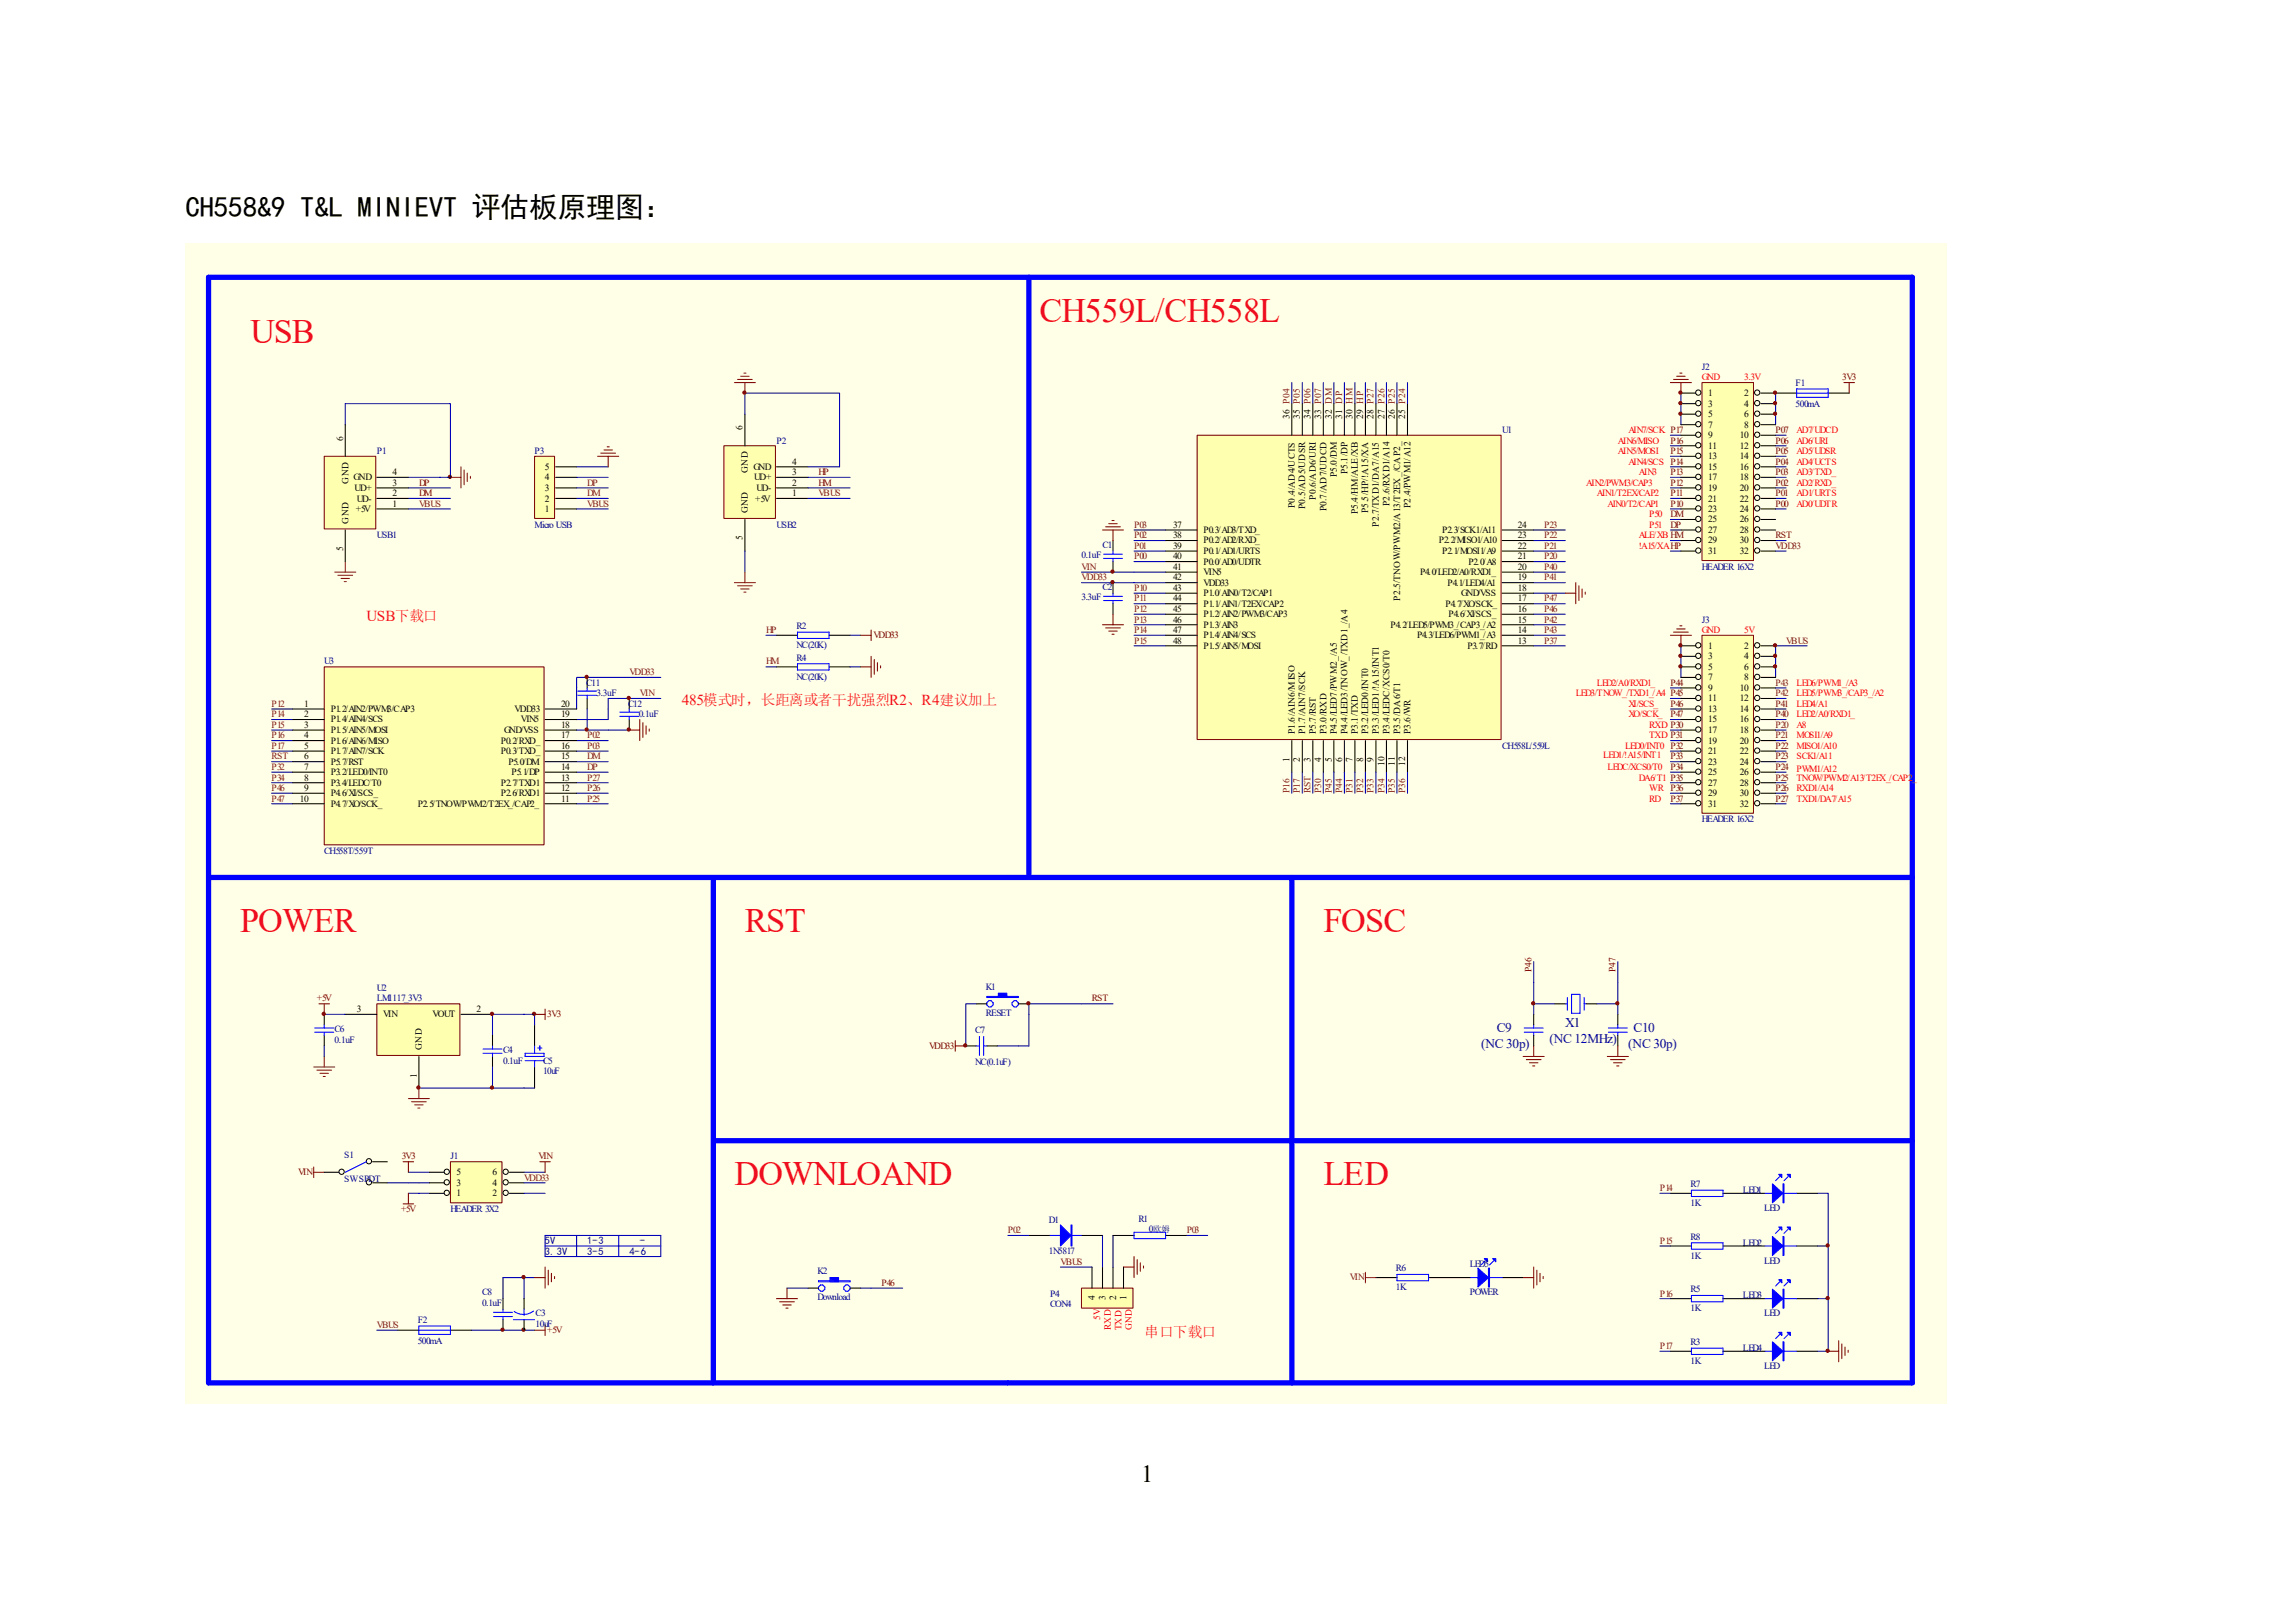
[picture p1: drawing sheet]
<svg xmlns="http://www.w3.org/2000/svg" width="297mm" height="210mm" viewBox="0 0 297 210" stroke-linecap="round" stroke-linejoin="round" font-family="sans-serif">
<defs><g id="words">
<g font-size="4.4" fill="#ee0e22">
<text x="134.5" y="41.7">CH559L/CH558L</text>
<text x="32.4" y="44.4">USB</text>
<text x="31.1" y="120.6">POWER</text>
<text x="96.4" y="120.6">RST</text>
<text x="171.3" y="120.6">FOSC</text>
<text x="95" y="153.4">DOWNLOAND</text>
<text x="171.3" y="153.4">LED</text>
</g>
<text font-size="3.7" x="24" y="28.1">CH558&amp;9 T&amp;L MINIEVT 评估板原理图：</text>
<text font-size="3.2" x="147.7" y="191.7">1</text>
<g font-size="2" fill="#ee0e22">
<text x="47.4" y="80.4">USB下载口</text>
<text x="88.2" y="91.3">485模式时，长距离或者干扰强烈R2、R4建议加上</text>
</g>
<text font-size="1.9" fill="#ee0e22" x="148.1" y="173">串口下载口</text>
<g font-size="1.7" fill="#000080">
<text x="191.7" y="135.6">(NC 30p)</text>
<text x="193.7" y="133.6">C9</text>
<text x="200.5" y="135">(NC 12MHz)</text>
<text x="202.6" y="132.9">X1</text>
<text x="210.7" y="135.6">(NC 30p)</text>
<text x="211.4" y="133.6">C10</text>
</g>
<g font-size="1.4" fill="#000080">
<text x="70.5" y="161">5V</text>
<text x="76" y="161">1-3</text>
<text x="82.8" y="161">-</text>
<text x="70.5" y="162.4">3.3V</text>
<text x="76" y="162.4">3-5</text>
<text x="81.4" y="162.4">4-6</text>
</g>
<g font-size="1.2" fill="#000080">
<text x="220.3" y="47.8">J2</text>
<text x="232.4" y="49.9">F1</text>
<text x="232.4" y="52.6">500mA</text>
<text x="48.8" y="58.8">P1</text>
<text x="69.2" y="58.8">P3</text>
<text x="100.5" y="57.4">P2</text>
<text x="194.4" y="56">U1</text>
<text x="48.8" y="69.6">USB1</text>
<text x="69.2" y="68.3">Micro USB</text>
<text x="100.5" y="68.3">USB2</text>
<text x="142.7" y="70.9">C1</text>
<text x="140" y="72.2">0.1uF</text>
<text x="140" y="77.7">3.3uF</text>
<text x="142.7" y="76.3">C2</text>
<text x="220.3" y="73.7">HEADER 16X2</text>
<text x="103.1" y="81.4">R2</text>
<text x="103.1" y="83.8">NC(20K)</text>
<text x="220.3" y="80.6">J3</text>
<text x="42" y="86">U3</text>
<text x="75.9" y="88.7">C11</text>
<text x="103.1" y="85.5">R4</text>
<text x="103.1" y="87.9">NC(20K)</text>
<text x="77.2" y="90.1">3.3uF</text>
<text x="81.3" y="91.4">C12</text>
<text x="82.7" y="92.8">0.1uF</text>
<text x="194.4" y="96.9">CH558L/559L</text>
<text x="220.3" y="106.4">HEADER 16X2</text>
<text x="42" y="110.5">CH558T/559T</text>
<text x="48.8" y="128.2">U2</text>
<text x="48.8" y="129.6">LM1117_3V3</text>
<text x="127.6" y="128.1">K1</text>
<text x="127.6" y="131.5">RESET</text>
<text x="43.3" y="133.6">C6</text>
<text x="43.3" y="134.9">0.1uF</text>
<text x="65.1" y="136.3">C4</text>
<text x="65.1" y="137.6">0.1uF</text>
<text x="70.3" y="137.6">C5</text>
<text x="126.2" y="133.7">C7</text>
<text x="126.2" y="137.8">NC(0.1uF)</text>
<text x="70.3" y="139">10uF</text>
<text x="44.5" y="149.9">S1</text>
<text x="44.5" y="152.9">SW SPDT</text>
<text x="58.3" y="150">J1</text>
<text x="218.8" y="153.6">R7</text>
<text x="225.6" y="154.4">LED1</text>
<text x="58.3" y="156.8">HEADER 3X2</text>
<text x="135.7" y="158.2">D1</text>
<text x="147.3" y="158.1">R1</text>
<text x="148.7" y="159.4">0</text>
<text x="218.8" y="160.4">R8</text>
<text x="218.8" y="156">1K</text>
<text x="225.6" y="161.2">LED2</text>
<text x="228.3" y="156.7">LED</text>
<text x="62.4" y="167.6">C8</text>
<text x="105.8" y="164.9">K2</text>
<text x="135.7" y="162.3">1N5817</text>
<text x="135.9" y="167.8">P4</text>
<text x="180.6" y="164.5">R6</text>
<text x="180.6" y="166.9">1K</text>
<text x="190.2" y="163.9">LED5</text>
<text x="190.2" y="167.6">POWER</text>
<text x="218.8" y="167.2">R5</text>
<text x="218.8" y="162.9">1K</text>
<text x="228.3" y="163.5">LED</text>
<text x="54.1" y="171.2">F2</text>
<text x="54.1" y="173.9">500mA</text>
<text x="62.4" y="169">0.1uF</text>
<text x="69.3" y="170.4">C3</text>
<text x="69.3" y="171.7">10uF</text>
<text x="105.8" y="168.3">Download</text>
<text x="135.9" y="169.1">CON4</text>
<text x="218.8" y="169.7">1K</text>
<text x="225.6" y="168">LED3</text>
<text x="228.3" y="170.4">LED</text>
<text x="218.8" y="174">R3</text>
<text x="218.8" y="176.5">1K</text>
<text x="225.6" y="174.8">LED4</text>
<text x="228.3" y="177.2">LED</text>
</g>
<g font-size="1.2" fill="#f00">
<text x="220.3" y="49.2">GND</text>
<text x="225.7" y="49.2">3.3V</text>
<text x="209.4" y="58.8">AIN5/MOSI</text>
<text x="209.4" y="57.4">AIN6/MISO</text>
<text x="210.7" y="56">AIN7/SCK P17</text>
<text x="232.5" y="58.8">AD5/UDSR</text>
<text x="232.5" y="57.4">AD6/URI</text>
<text x="232.5" y="56">AD7/UDCD</text>
<text x="205.3" y="62.8">AIN2/PWM3/CAP3</text>
<text x="206.7" y="64.2">AIN1/T2EX/CAP2</text>
<text x="208" y="65.6">AIN0/T2/CAP1</text>
<text x="210.7" y="60.1">AIN4/SCS P14</text>
<text x="212.1" y="61.5">AIN3</text>
<text x="232.5" y="65.6">AD0/UDTR</text>
<text x="232.5" y="64.2">AD1/URTS</text>
<text x="232.5" y="62.8">AD2/RXD_</text>
<text x="232.5" y="61.5">AD3/TXD_</text>
<text x="232.5" y="60.1">AD4/UCTS</text>
<text x="212.1" y="69.6">ALE/XB HM</text>
<text x="212.1" y="71">!A15/XAHP</text>
<text x="213.4" y="66.9">P50</text>
<text x="213.4" y="68.3">P51</text>
<text x="220.3" y="81.9">GND</text>
<text x="225.7" y="81.9">5V</text>
<text x="206.7" y="88.7">LED2/A0/RXD1_</text>
<text x="232.5" y="88.7">LED6/PWM1_/A3</text>
<text x="203.9" y="90.1">LED3/TNOW_/TXD1_/A4 P45</text>
<text x="210.7" y="92.8">XO/SCK_</text>
<text x="210.7" y="91.4">XI/SCS_</text>
<text x="213.4" y="94.2">RXD P30</text>
<text x="213.4" y="95.5">TXD P31</text>
<text x="232.5" y="94.2">A8</text>
<text x="232.5" y="95.5">MOSI1/A9</text>
<text x="232.5" y="92.8">LED2/A0/RXD1_</text>
<text x="232.5" y="91.4">LED4/A1</text>
<text x="232.5" y="90.1">LED5/PWM3_/CAP3_/A2</text>
<text x="207.5" y="98.1">LED1/!A15/INT1</text>
<text x="208" y="99.6">LEDC/XCS0/T0</text>
<text x="210.3" y="96.9">LED0/INT0 P32</text>
<text x="212.1" y="101">DA6/T1 P35</text>
<text x="232.5" y="96.9">MISO1/A10</text>
<text x="232.5" y="98.3">SCK1/A11</text>
<text x="232.5" y="99.9">PWM1/A12</text>
<text x="232.5" y="101">TNOW/PWM2/A13/T2EX_/CAP2_</text>
<text x="213.4" y="102.4">WR P36</text>
<text x="213.4" y="103.7">RD</text>
<text x="232.5" y="102.4">RXD1/A14</text>
<text x="232.5" y="103.7">TXD1/DA7/A15</text>
<text x="142.4" y="170.8" transform="rotate(-90 142.4 170.8)">5V</text>
<text x="143.8" y="172.1" transform="rotate(-90 143.8 172.1)">RXD</text>
<text x="145.1" y="172.1" transform="rotate(-90 145.1 172.1)">TXD</text>
<text x="146.5" y="172.1" transform="rotate(-90 146.5 172.1)">GND</text>
</g>
<g font-size="1.2">
<text x="221.1" y="51.3">1</text>
<text x="221.1" y="52.6">3</text>
<text x="221.1" y="54">5</text>
<text x="225.7" y="51.3">2</text>
<text x="225.7" y="52.6">4</text>
<text x="225.7" y="54">6</text>
<text x="44.4" y="57" transform="rotate(-90 44.4 57)">6</text>
<text x="96.1" y="55.6" transform="rotate(-90 96.1 55.6)">6</text>
<text x="166.9" y="54.3" transform="rotate(-90 166.9 54.3)">36 P04</text>
<text x="168.2" y="54.3" transform="rotate(-90 168.2 54.3)">35 P05</text>
<text x="169.6" y="54.3" transform="rotate(-90 169.6 54.3)">34 P06</text>
<text x="171" y="54.3" transform="rotate(-90 171 54.3)">33 P07</text>
<text x="172.3" y="54.3" transform="rotate(-90 172.3 54.3)">32 DM</text>
<text x="173.7" y="54.3" transform="rotate(-90 173.7 54.3)">31 DP</text>
<text x="175.1" y="54.3" transform="rotate(-90 175.1 54.3)">30 HM</text>
<text x="176.4" y="54.3" transform="rotate(-90 176.4 54.3)">29 HP</text>
<text x="177.8" y="54.3" transform="rotate(-90 177.8 54.3)">28 P27</text>
<text x="179.2" y="54.3" transform="rotate(-90 179.2 54.3)">27 P26</text>
<text x="180.5" y="54.3" transform="rotate(-90 180.5 54.3)">26 P25</text>
<text x="181.9" y="54.3" transform="rotate(-90 181.9 54.3)">25 P24</text>
<text x="221.1" y="55.3">7</text>
<text x="221.1" y="56.7">9</text>
<text x="221.1" y="58.1">11</text>
<text x="221.1" y="59.4">13</text>
<text x="225.2" y="56.7">10</text>
<text x="225.2" y="58.1">12</text>
<text x="225.2" y="59.4">14</text>
<text x="225.7" y="55.3">8</text>
<text x="45.1" y="62.6" transform="rotate(-90 45.1 62.6)">GND</text>
<text x="45.8" y="62.1">GND</text>
<text x="45.9" y="63.5">UD+</text>
<text x="46.2" y="64.9">UD-</text>
<text x="50.8" y="65.6">1</text>
<text x="50.8" y="61.5">4</text>
<text x="50.8" y="62.8">3</text>
<text x="50.8" y="64.2">2</text>
<text x="70.5" y="64.9">2</text>
<text x="70.5" y="63.5">3</text>
<text x="70.5" y="62.1">4</text>
<text x="70.5" y="60.8">5</text>
<text x="96.8" y="61.2" transform="rotate(-90 96.8 61.2)">GND</text>
<text x="97.5" y="60.8">GND</text>
<text x="97.6" y="62.1">UD+</text>
<text x="97.7" y="64.9">+5V</text>
<text x="97.9" y="63.5">UD-</text>
<text x="102.5" y="64.2">1</text>
<text x="102.5" y="60.1">4</text>
<text x="102.5" y="61.5">3</text>
<text x="102.5" y="62.8">2</text>
<text x="167.6" y="65.7" transform="rotate(-90 167.6 65.7)">P0.4/AD4/UCTS</text>
<text x="168.9" y="65.9" transform="rotate(-90 168.9 65.9)">P0.5/AD5/UDSR</text>
<text x="170.3" y="64.6" transform="rotate(-90 170.3 64.6)">P0.6/AD6/URI</text>
<text x="173" y="61.8" transform="rotate(-90 173 61.8)">P5.0/DM</text>
<text x="174.4" y="61.3" transform="rotate(-90 174.4 61.3)">P5.1/DP</text>
<text x="179.8" y="65.4" transform="rotate(-90 179.8 65.4)">P2.6/RXD1/A14</text>
<text x="182.5" y="65.7" transform="rotate(-90 182.5 65.7)">P2.4/PWM1/A12</text>
<text x="221.1" y="60.8">15</text>
<text x="221.1" y="62.1">17</text>
<text x="221.1" y="63.5">19</text>
<text x="221.1" y="64.9">21</text>
<text x="225.2" y="60.8">16</text>
<text x="225.2" y="62.1">18</text>
<text x="225.2" y="63.5">20</text>
<text x="225.2" y="64.9">22</text>
<text x="44.4" y="71.3" transform="rotate(-90 44.4 71.3)">5</text>
<text x="45.1" y="67.8" transform="rotate(-90 45.1 67.8)">GND</text>
<text x="46.1" y="66.3">+5V</text>
<text x="70.5" y="66.3">1</text>
<text x="96.1" y="69.9" transform="rotate(-90 96.1 69.9)">5</text>
<text x="96.8" y="66.4" transform="rotate(-90 96.8 66.4)">GND</text>
<text x="151.8" y="68.3">37</text>
<text x="151.8" y="69.6">38</text>
<text x="151.8" y="71">39</text>
<text x="155.7" y="69">P0.3/AD3/TXD_</text>
<text x="155.7" y="70.3">P0.2/AD2/RXD_</text>
<text x="155.7" y="71.7">P0.1/AD1/URTS</text>
<text x="171.7" y="66.1" transform="rotate(-90 171.7 66.1)">P0.7/AD7/UDCD</text>
<text x="175.7" y="66.5" transform="rotate(-90 175.7 66.5)">P5.4/HM/ALE/XB</text>
<text x="177.1" y="66.4" transform="rotate(-90 177.1 66.4)">P5.5/HP/!A15/XA</text>
<text x="178.4" y="68.2" transform="rotate(-90 178.4 68.2)">P2.7/TXD1/DA7/A15</text>
<text x="186.2" y="70.3">P2.2/MISO1/A10</text>
<text x="186.7" y="71.7">P2.1/MOSI1/A9</text>
<text x="186.7" y="69">P2.3/SCK1/A11</text>
<text x="196.4" y="71">22</text>
<text x="196.4" y="69.6">23</text>
<text x="196.4" y="68.3">24</text>
<text x="221.1" y="66.3">23</text>
<text x="221.1" y="67.6">25</text>
<text x="221.1" y="69">27</text>
<text x="221.1" y="70.3">29</text>
<text x="221.1" y="71.7">31</text>
<text x="225.2" y="66.3">24</text>
<text x="225.2" y="67.6">26</text>
<text x="225.2" y="69">28</text>
<text x="225.2" y="70.3">30</text>
<text x="225.2" y="71.7">32</text>
<text x="151.8" y="72.4">40</text>
<text x="151.8" y="73.7">41</text>
<text x="151.8" y="75.1">42</text>
<text x="151.8" y="76.5">43</text>
<text x="151.8" y="77.8">44</text>
<text x="155.7" y="73.1">P0.0/AD0/UDTR</text>
<text x="155.7" y="74.4">VIN5</text>
<text x="155.7" y="75.8">VDD33</text>
<text x="155.7" y="77.1">P1.0/AIN0/T2/CAP1</text>
<text x="181.2" y="77.7" transform="rotate(-90 181.2 77.7)">P2.5/TNOW/PWM2/A13/T2EX_/CAP2_</text>
<text x="183.8" y="74.4">P4.0/LED2/A0/RXD1_</text>
<text x="187.3" y="75.8">P4.1/LED4/A1</text>
<text x="189.1" y="77.1">GND/VSS</text>
<text x="190" y="73.1">P2.0/A8</text>
<text x="196.4" y="77.8">17</text>
<text x="196.4" y="76.5">18</text>
<text x="196.4" y="73.7">20</text>
<text x="196.4" y="72.4">21</text>
<text x="196.4" y="75.1">19</text>
<text x="151.8" y="83.3">48</text>
<text x="151.8" y="79.2">45</text>
<text x="151.8" y="80.6">46</text>
<text x="151.8" y="81.9">47</text>
<text x="155.7" y="83.9">P1.5/AIN5/MOSI</text>
<text x="155.7" y="78.5">P1.1/AIN1/T2EX/CAP2</text>
<text x="155.7" y="79.9">P1.2/AIN2/PWM3/CAP3</text>
<text x="155.7" y="81.2">P1.3/AIN3</text>
<text x="155.7" y="82.6">P1.4/AIN4/SCS</text>
<text x="180" y="81.2">P4.2/LED5/PWM3_/CAP3_/A2</text>
<text x="183.4" y="82.6">P4.3/LED6/PWM1_/A3</text>
<text x="187.1" y="78.5">P4.7/XO/SCK_</text>
<text x="187.5" y="79.9">P4.6/XI/SCS_</text>
<text x="189.9" y="83.9">P3.7/RD</text>
<text x="196.4" y="83.3">13</text>
<text x="196.4" y="79.2">16</text>
<text x="196.4" y="81.9">14</text>
<text x="196.4" y="80.6">15</text>
<text x="221.1" y="83.9">1</text>
<text x="225.7" y="83.9">2</text>
<text x="221.1" y="85.3">3</text>
<text x="221.1" y="86.7">5</text>
<text x="221.1" y="88.1">7</text>
<text x="221.1" y="89.4">9</text>
<text x="225.2" y="89.4">10</text>
<text x="225.7" y="85.3">4</text>
<text x="225.7" y="86.7">6</text>
<text x="225.7" y="88.1">8</text>
<text x="39.4" y="94.2">3</text>
<text x="39.4" y="95.5">4</text>
<text x="39.4" y="91.4">1</text>
<text x="39.4" y="92.8">2</text>
<text x="42.8" y="94.9">P1.5/AIN5/MOSI</text>
<text x="42.8" y="92.1">P1.2/AIN2/PWM3/CAP3</text>
<text x="42.8" y="93.5">P1.4/AIN4/SCS</text>
<text x="65.2" y="94.9">GND/VSS</text>
<text x="66.6" y="92.1">VDD33</text>
<text x="67.4" y="93.5">VIN5</text>
<text x="72.6" y="94.2">18</text>
<text x="72.6" y="95.5">17</text>
<text x="72.6" y="92.8">19</text>
<text x="72.6" y="91.4">20</text>
<text x="167.6" y="95" transform="rotate(-90 167.6 95)">P1.6/AIN6/MISO</text>
<text x="168.9" y="95" transform="rotate(-90 168.9 95)">P1.7/AIN7/SCK</text>
<text x="170.3" y="95" transform="rotate(-90 170.3 95)">P5.7/RST</text>
<text x="171.7" y="95" transform="rotate(-90 171.7 95)">P3.0/RXD</text>
<text x="173" y="95" transform="rotate(-90 173 95)">P4.5/LED7/PWM2_/A5</text>
<text x="174.4" y="95" transform="rotate(-90 174.4 95)">P4.4/LED3/TNOW_/TXD1_/A4</text>
<text x="175.7" y="95" transform="rotate(-90 175.7 95)">P3.1/TXD</text>
<text x="177.1" y="95" transform="rotate(-90 177.1 95)">P3.2/LED0/INT0</text>
<text x="178.4" y="95" transform="rotate(-90 178.4 95)">P3.3/LED1/!A15/INT1</text>
<text x="179.8" y="95" transform="rotate(-90 179.8 95)">P3.4/LEDC/XCS0/T0</text>
<text x="181.2" y="95" transform="rotate(-90 181.2 95)">P3.5/DA6/T1</text>
<text x="182.5" y="95" transform="rotate(-90 182.5 95)">P3.6/WR</text>
<text x="221.1" y="90.8">11</text>
<text x="221.1" y="92.1">13</text>
<text x="221.1" y="93.5">15</text>
<text x="221.1" y="94.9">17</text>
<text x="225.2" y="90.8">12</text>
<text x="225.2" y="92.1">14</text>
<text x="225.2" y="93.5">16</text>
<text x="225.2" y="94.9">18</text>
<text x="39.4" y="96.9">5</text>
<text x="39.4" y="98.3">6</text>
<text x="39.4" y="99.6">7</text>
<text x="39.4" y="101">8</text>
<text x="42.8" y="96.2">P1.6/AIN6/MISO</text>
<text x="42.8" y="97.6">P1.7/AIN7/SCK</text>
<text x="42.8" y="98.9">P5.7/RST</text>
<text x="42.8" y="100.3">P3.2/LED0/INT0</text>
<text x="42.8" y="101.7">P3.4/LEDC/T0</text>
<text x="64.8" y="101.7">P2.7/TXD1</text>
<text x="64.8" y="97.6">P0.3/TXD_</text>
<text x="64.8" y="96.2">P0.2/RXD_</text>
<text x="65.8" y="98.9">P5.0/DM</text>
<text x="66.2" y="100.3">P5.1/DP</text>
<text x="72.6" y="101">13</text>
<text x="72.6" y="99.6">14</text>
<text x="72.6" y="98.3">15</text>
<text x="72.6" y="96.9">16</text>
<text x="166.9" y="98.6" transform="rotate(-90 166.9 98.6)">1</text>
<text x="168.2" y="98.6" transform="rotate(-90 168.2 98.6)">2</text>
<text x="169.6" y="98.6" transform="rotate(-90 169.6 98.6)">3</text>
<text x="171" y="98.6" transform="rotate(-90 171 98.6)">4</text>
<text x="172.3" y="98.6" transform="rotate(-90 172.3 98.6)">5</text>
<text x="173.7" y="98.6" transform="rotate(-90 173.7 98.6)">6</text>
<text x="175.1" y="98.6" transform="rotate(-90 175.1 98.6)">7</text>
<text x="176.4" y="98.6" transform="rotate(-90 176.4 98.6)">8</text>
<text x="177.8" y="98.6" transform="rotate(-90 177.8 98.6)">9</text>
<text x="179.2" y="99.1" transform="rotate(-90 179.2 99.1)">10</text>
<text x="180.5" y="99.1" transform="rotate(-90 180.5 99.1)">11</text>
<text x="181.9" y="99.1" transform="rotate(-90 181.9 99.1)">12</text>
<text x="221.1" y="96.2">19</text>
<text x="221.1" y="97.6">21</text>
<text x="221.1" y="98.9">23</text>
<text x="221.1" y="100.3">25</text>
<text x="221.1" y="101.7">27</text>
<text x="225.2" y="96.2">20</text>
<text x="225.2" y="97.6">22</text>
<text x="225.2" y="98.9">24</text>
<text x="225.2" y="100.3">26</text>
<text x="225.2" y="101.7">28</text>
<text x="38.8" y="103.7">10</text>
<text x="39.4" y="102.4">9</text>
<text x="42.8" y="103">P4.6/XI/SCS_</text>
<text x="42.8" y="104.4">P4.7/XO/SCK_</text>
<text x="54.1" y="104.4">P2.5/TNOW/PWM2/T2EX_/CAP2_</text>
<text x="64.8" y="103">P2.6/RXD1</text>
<text x="72.6" y="103.7">11</text>
<text x="72.6" y="102.4">12</text>
<text x="221.1" y="103">29</text>
<text x="221.1" y="104.4">31</text>
<text x="225.2" y="103">30</text>
<text x="225.2" y="104.4">32</text>
<text x="46.2" y="131">3</text>
<text x="49.6" y="131.7">VIN</text>
<text x="56" y="131.7">VOUT</text>
<text x="61.7" y="131">2</text>
<text x="54.6" y="135.9" transform="rotate(-90 54.6 135.9)">GND</text>
<text x="53.9" y="139.4" transform="rotate(-90 53.9 139.4)">1</text>
<text x="59.1" y="154.8">1</text>
<text x="59.1" y="153.5">3</text>
<text x="59.1" y="152.1">5</text>
<text x="63.8" y="154.8">2</text>
<text x="63.8" y="153.5">4</text>
<text x="63.8" y="152.1">6</text>
<text x="141.7" y="168.2" transform="rotate(-90 141.7 168.2)">4</text>
<text x="143.1" y="168.2" transform="rotate(-90 143.1 168.2)">3</text>
<text x="144.4" y="168.2" transform="rotate(-90 144.4 168.2)">2</text>
<text x="145.8" y="168.2" transform="rotate(-90 145.8 168.2)">1</text>
</g>
<g font-size="1.2" fill="#800000">
<text x="238.4" y="49.2">3V3</text>
<text x="216.2" y="58.8">P15</text>
<text x="216.2" y="57.4">P16</text>
<text x="229.8" y="58.8">P05</text>
<text x="229.8" y="57.4">P06</text>
<text x="229.8" y="56">P07</text>
<text x="54.2" y="62.8">DP</text>
<text x="54.2" y="64.2">DM</text>
<text x="105.9" y="61.5">HP</text>
<text x="105.9" y="62.8">HM</text>
<text x="216.2" y="65.6">P10</text>
<text x="216.2" y="64.2">P11</text>
<text x="216.2" y="62.8">P12</text>
<text x="216.2" y="61.5">P13</text>
<text x="229.8" y="65.6">P00</text>
<text x="229.8" y="64.2">P01</text>
<text x="229.8" y="62.8">P02</text>
<text x="229.8" y="61.5">P03</text>
<text x="229.8" y="60.1">P04</text>
<text x="216.2" y="66.9">DM</text>
<text x="216.2" y="68.3">DP</text>
<text x="229.8" y="69.6">RST</text>
<text x="113" y="82.6">VDD33</text>
<text x="216.2" y="88.7">P44</text>
<text x="216.2" y="91.4">P46</text>
<text x="216.2" y="92.8">P47</text>
<text x="229.8" y="92.8">P40</text>
<text x="229.8" y="91.4">P41</text>
<text x="216.2" y="98.3">P33</text>
<text x="216.2" y="99.6">P34</text>
<text x="229.8" y="96.9">P22</text>
<text x="229.8" y="98.3">P23</text>
<text x="229.8" y="99.6">P24</text>
<text x="229.8" y="101">P25</text>
<text x="216.2" y="103.7">P37</text>
<text x="229.8" y="102.4">P26</text>
<text x="229.8" y="103.7">P27</text>
<text x="198.2" y="125.8" transform="rotate(-90 198.2 125.8)">P46</text>
<text x="209.1" y="125.8" transform="rotate(-90 209.1 125.8)">P47</text>
<text x="41" y="129.6">+5V</text>
<text x="70.8" y="131.7">3V3</text>
<text x="141.3" y="129.6">RST</text>
<text x="120.2" y="135.7">VDD33</text>
<text x="38.6" y="152.1">VIN</text>
<text x="52" y="150">3V3</text>
<text x="69.7" y="150">VIN</text>
<text x="51.9" y="156.8">+5V</text>
<text x="114.1" y="166.4">P46</text>
<text x="70.8" y="172.5">+5V</text>
</g>
<g font-size="1.2" fill="#781915">
<text x="54.2" y="65.6">VBUS</text>
<text x="76" y="65.6">VBUS</text>
<text x="76" y="64.2">DM</text>
<text x="76" y="62.8">DP</text>
<text x="105.9" y="64.2">VBUS</text>
<text x="146.8" y="68.3">P03</text>
<text x="146.8" y="69.6">P02</text>
<text x="146.8" y="71">P01</text>
<text x="199.9" y="71">P21</text>
<text x="199.9" y="69.6">P22</text>
<text x="199.9" y="68.3">P23</text>
<text x="229.8" y="71">VDD33</text>
<text x="140" y="75.1">VDD33</text>
<text x="140" y="73.7">VIN</text>
<text x="146.8" y="72.4">P00</text>
<text x="146.8" y="76.5">P10</text>
<text x="146.8" y="77.8">P11</text>
<text x="199.9" y="72.4">P20</text>
<text x="199.9" y="73.7">P40</text>
<text x="199.9" y="75.1">P41</text>
<text x="199.9" y="77.8">P47</text>
<text x="99.1" y="81.9">HP</text>
<text x="146.8" y="79.2">P12</text>
<text x="146.8" y="80.6">P13</text>
<text x="146.8" y="81.9">P14</text>
<text x="146.8" y="83.3">P15</text>
<text x="199.9" y="79.2">P46</text>
<text x="199.9" y="83.3">P37</text>
<text x="199.9" y="80.6">P42</text>
<text x="199.9" y="81.9">P43</text>
<text x="231.1" y="83.3">VBUS</text>
<text x="81.5" y="87.4">VDD33</text>
<text x="99.1" y="86">HM</text>
<text x="229.8" y="88.7">P43</text>
<text x="35.1" y="91.4">P12</text>
<text x="35.1" y="92.8">P14</text>
<text x="35.1" y="94.2">P15</text>
<text x="35.1" y="95.5">P16</text>
<text x="76" y="95.5">P02</text>
<text x="82.8" y="90.1">VIN</text>
<text x="229.8" y="94.2">P20</text>
<text x="229.8" y="95.5">P21</text>
<text x="229.8" y="90.1">P42</text>
<text x="35.1" y="96.9">P17</text>
<text x="35.1" y="98.3">RST</text>
<text x="35.1" y="99.6">P32</text>
<text x="35.1" y="101">P34</text>
<text x="76" y="96.9">P03</text>
<text x="76" y="98.3">DM</text>
<text x="76" y="99.6">DP</text>
<text x="76" y="101">P27</text>
<text x="35.1" y="102.4">P46</text>
<text x="35.1" y="103.7">P47</text>
<text x="76" y="102.4">P26</text>
<text x="76" y="103.7">P25</text>
<text x="166.9" y="102.7" transform="rotate(-90 166.9 102.7)">P16</text>
<text x="168.2" y="102.7" transform="rotate(-90 168.2 102.7)">P17</text>
<text x="169.6" y="102.7" transform="rotate(-90 169.6 102.7)">RST</text>
<text x="171" y="102.7" transform="rotate(-90 171 102.7)">P30</text>
<text x="172.3" y="102.7" transform="rotate(-90 172.3 102.7)">P45</text>
<text x="173.7" y="102.7" transform="rotate(-90 173.7 102.7)">P44</text>
<text x="175.1" y="102.7" transform="rotate(-90 175.1 102.7)">P31</text>
<text x="176.4" y="102.7" transform="rotate(-90 176.4 102.7)">P32</text>
<text x="177.8" y="102.7" transform="rotate(-90 177.8 102.7)">P33</text>
<text x="179.2" y="102.7" transform="rotate(-90 179.2 102.7)">P34</text>
<text x="180.5" y="102.7" transform="rotate(-90 180.5 102.7)">P35</text>
<text x="181.9" y="102.7" transform="rotate(-90 181.9 102.7)">P36</text>
<text x="67.8" y="152.8">VDD33</text>
<text x="214.8" y="154.1">P14</text>
<text x="130.4" y="159.6">P02</text>
<text x="153.6" y="159.6">P03</text>
<text x="214.8" y="161">P15</text>
<text x="137.2" y="163.7">VBUS</text>
<text x="174.7" y="165.7">VIN</text>
<text x="214.8" y="167.8">P16</text>
<text x="48.8" y="171.8">VBUS</text>
<text x="214.8" y="174.5">P17</text>
</g>
<text font-size="1.1" fill="#000080" x="149.2" y="159.4">欧姆</text>
</g></defs>
<path d="M24 31.5h228v150.1h-228z" fill-rule="evenodd" fill="#ffffe8"/>
<g fill="none" stroke="#00f" stroke-width=".14">
<path d="M197.3 133.6h2.4M197.3 133h2.4M198.5 132.6v.4M198.5 133.6v.4M202.6 129.9h.2M202.8 129.1v1.6M203.4 128.7h1.1v2.4h-1.1zM205 129.1v1.6M205 129.9h.3M208.1 133.6h2.5M208.1 133h2.5M209.4 132.6v.4"/>
<path d="M209.4 133.6v.4"/>
</g>
<path d="M198.5 131.3v1.3M198.5 134v1.3M201.2 129.9h1.4M205.3 129.9h1.4M209.4 131.3v1.3M209.4 134v1.3" fill="none" stroke="#000" stroke-width=".14"/>
<path d="M197.1 136.7h2.7M197.5 137.1h1.9M197.9 137.5h1.1M198.3 137.9h.3M198.5 135.3v1.4M208 136.7h2.7M208.4 137.1h1.9M208.8 137.5h1.1M209.2 137.9h.3M209.4 135.3v1.4" fill="none" stroke="#800000" stroke-width=".14"/>
<path d="M42 59h6.6v9.4h-6.6z" fill-rule="evenodd" fill="#ffffb0" stroke="#800000" stroke-width=".13"/>
<path d="M44.7 55v4M44.7 68.6v4.1M48.8 65.9h4.1M48.8 61.8h4.1M48.8 63.1h4.1M48.8 64.5h4.1M51.5 172.1h2.7M58.3 172.1h2.7M65.1 168v1.4M65.1 170.8v1.3" fill="none" stroke="#000" stroke-width=".14"/>
<path d="M44.7 52.2v2.8M52.9 61.8h4M52.9 63.1h5.4M52.9 64.5h5.4" fill="none" stroke="#000080" stroke-width=".14"/>
<path d="M43.3 74h2.7M43.7 74.4h1.9M44.1 74.9h1.1M44.5 75.3h.3M44.7 72.7v1.3M58.3 61.8h1.4M59.7 60.4v2.7M60.1 60.8v1.9M60.5 61.2v1.1M60.9 61.6v.3" fill="none" stroke="#781915" stroke-width=".14"/>
<path d="M54.2 171.6h4.1v1.1h-4.1zM54.2 172.1h4.1M63.9 169.8h2.4M63.9 170.4h2.4M65.1 169.4v.4M65.1 170.4v.4" fill="none" stroke="#00f" stroke-width=".14"/>
<path d="M93.7 57.7h6.7v9.4h-6.7z" fill-rule="evenodd" fill="#ffffb0" stroke="#800000" stroke-width=".13"/>
<path d="M96.4 53.6v4.1M96.4 67.2v4.1M100.5 64.5h4.1M100.5 60.4h4.1M100.5 61.8h4.1M100.5 63.1h4.1M69.2 132.6v2.7M69.2 138.1v2.7" fill="none" stroke="#000" stroke-width=".14"/>
<path d="M96.4 50.9v2.7M96.4 71.3v2.7M104.6 60.4h4.1M104.6 61.8h5.4M104.6 63.1h5.4" fill="none" stroke="#000080" stroke-width=".14"/>
<path d="M95 75.4h2.8M95.5 75.8h1.9M95.9 76.2h1M96.3 76.6h.2M96.4 74v1.4" fill="none" stroke="#781915" stroke-width=".14"/>
<circle cx="58.2" cy="61.7" r=".21" fill="#800000" stroke="#800000" stroke-width=".13"/>
<path d="M68 136.3h2.4v.4h-2.4zM68 137.3h2.4M69.2 135.3v1M69.2 137.3v.8M69.6 135.6h.5M69.9 135.3v.6" fill="none" stroke="#00f" stroke-width=".14"/>
<path d="M41.3 129.9h1.3M42 129.9v1.4" fill="none" stroke="#800000" stroke-width=".14"/>
<path d="M48.8 129.9h10.7v6.7h-10.7z" fill-rule="evenodd" fill="#ffffb0" stroke="#800000" stroke-width=".13"/>
<g fill="none" stroke="#000" stroke-width=".14">
<path d="M42 131.3v1.3M42 134v1.3M44.7 131.3h4.1M54.2 136.7v4.1M59.7 131.3h4M63.7 134v1.3M63.7 136.7v1.4M125 135.3h1.3M126.3 129.9h1.4M127.7 135.3h1.4M131.8 129.9h1.4M216.2 154.4h2.7"/>
<path d="M223 154.4h5.4M232.5 154.4h2.7M178.1 165.3h2.7M184.9 165.3h5.4M194.4 165.3h2.7M216.2 174.9h2.7M216.2 168h2.7M216.2 161.2h2.7M223 174.9h5.4M223 168h5.4M223 161.2h5.4M232.5 174.9h2.7"/>
<path d="M232.5 168h2.7M232.5 161.2h2.7"/>
</g>
<g fill="none" stroke="#000080" stroke-width=".14">
<path d="M44.7 52.2h13.6v9.6M42 131.3h2.7M42 135.3v1.4M63.7 138.1v2.7M69.2 132.6v-1.3h-5.5v2.7M126.3 129.9h-1.3v5.4M144 129.9h-10.8v5.4h-4.1M198.5 127.2v2.7M201.2 129.9h-2.7v1.4M206.7 129.9h2.7v1.4M209.4 127.2v2.7M52.9 154.4h2.7"/>
<path d="M52.9 153.1h2.7M52.9 151.7h2.7M54.2 140.8h15M235.2 154.4h1.4M235.2 161.2h1.4M235.2 168h1.4M235.2 174.9h1.4"/>
</g>
<g fill="none" stroke="#00f" stroke-width=".14">
<path d="M40.7 133.6h2.5M40.7 133h2.5M42 132.6v.4M42 133.6v.4M62.5 136.3h2.5M62.5 135.8h2.5M63.7 135.3v.5M63.7 136.3v.4M126.3 135.3h.5M126.8 134.1v2.5M127.3 135.3h.4M127.3 134.1v2.5"/>
<path d="M127.7 128.9h4.1v.2h-4.1zM128 129.5h.3l.2 .3v.2l-.2 .3h-.3l-.3-.3v-.2zM129.2 129.1v-.6h1.1v.6M129.2 128.8h1.1M129.2 128.7h1.1M129.3 128.5v.6M129.5 128.5v.6M129.6 128.5v.6M129.8 128.5v.6M129.9 128.5v.6M130 128.5v.6M130.2 128.5v.6"/>
<path d="M131 129.8l.2-.3h.3l.3 .3v.2l-.3 .3h-.3l-.2-.3zM218.9 154h4.1v.8h-4.1zM228.4 154.4h4.1M230.3 159.1l-.5 .5M230.3 152.2l-.5 .6M231.4 159.1l-.5 .5M231.4 152.2l-.5 .6M180.8 164.9h4.1v.8h-4.1zM190.3 165.3h4.1M192.2 163.1l-.5 .6M193.3 163.1l-.5 .6M218.9 160.8h4.1v.8h-4.1z"/>
<path d="M218.9 167.6h4.1v.9h-4.1zM218.9 174.4h4.1v.9h-4.1zM228.4 174.9h4.1M228.4 168h4.1M228.4 161.2h4.1M230.3 172.7l-.5 .5M230.3 165.9l-.5 .5M231.4 172.7l-.5 .5M231.4 165.9l-.5 .5"/>
</g>
<path d="M40.6 138.1h2.7M41 138.5h1.9M41.4 138.9h1.1M41.8 139.3h.3M42 136.7v1.4M52.9 142.2h2.7M53.3 142.6h1.9M53.7 143h1.1M54.1 143.4h.2M54.2 140.8v1.4M176.7 164.6v1.4M176.7 165.3h1.4" fill="none" stroke="#781915" stroke-width=".14"/>
<circle cx="69.1" cy="131.2" r=".21" fill="#800000" stroke="#800000" stroke-width=".13"/>
<g fill="none" stroke="#800000" stroke-width=".14">
<path d="M69.2 131.3h1.3M70.5 130.6v1.3M123.6 134.7v1.3M123.6 135.3h1.4M52.2 150.3h1.3M52.2 155.8h1.3M52.9 150.3v1.4M52.9 154.4v1.4M197.1 165.3h1.4M198.5 164v2.7M198.9 164.4v1.9M199.3 164.8v1.1"/>
<path d="M199.7 165.2v.3"/>
</g>
<g fill="#00f" stroke="#00f" stroke-width=".14">
<path d="M229.4 173.6l1.3 1.3-1.3 1.2z"/>
<path d="M231.3 172.4h.4v.4z"/>
<path d="M230.2 172.4h.4v.4z"/>
<path d="M229.4 166.8l1.3 1.2-1.3 1.3z"/>
<path d="M231.3 165.6h.4v.4z"/>
<path d="M230.2 165.6h.4v.4z"/>
<path d="M229.4 160l1.3 1.2-1.3 1.3z"/>
<path d="M231.3 158.8h.4v.4z"/>
<path d="M230.2 158.8h.4v.4z"/>
<path d="M229.4 153.2l1.3 1.2-1.3 1.2z"/>
<path d="M231.3 152h.4v.4z"/>
<path d="M230.2 152h.4v.4z"/>
<path d="M191.3 164.1l1.3 1.2-1.3 1.2z"/>
<path d="M193.2 162.9h.4v.4z"/>
<path d="M192.1 162.9h.4v.4z"/>
<path d="M230.7 173.6h.2v2.5h-.2z" fill-rule="evenodd"/>
<path d="M230.7 166.8h.2v2.5h-.2z" fill-rule="evenodd"/>
<path d="M230.7 160h.2v2.5h-.2z" fill-rule="evenodd"/>
<path d="M230.7 153.2h.2v2.4h-.2z" fill-rule="evenodd"/>
<path d="M192.6 164.1h.2v2.4h-.2z" fill-rule="evenodd"/>
</g>
<path d="M133.2 35.9v77.6M247.5 35.9v77.6h-220.5" fill="none" stroke="#00f" stroke-width=".68"/>
<path d="M58.3 150.3h6.7v5.3h-6.7z" fill-rule="evenodd" fill="#ffffb0" stroke="#800000" stroke-width=".13"/>
<g fill="none" stroke="#000" stroke-width=".13">
<circle cx="44.2" cy="151.6" r=".34"/>
<circle cx="47.7" cy="150.3" r=".34"/>
<circle cx="47.7" cy="153" r=".34"/>
<circle cx="57.8" cy="154.4" r=".34"/>
<circle cx="57.8" cy="153" r=".34"/>
<circle cx="57.8" cy="151.6" r=".34"/>
<circle cx="65.4" cy="154.4" r=".34"/>
<circle cx="65.4" cy="153" r=".34"/>
<circle cx="65.4" cy="151.6" r=".34"/>
</g>
<g fill="none" stroke="#000" stroke-width=".14">
<path d="M100.5 82.2h2.7M100.5 86.3h2.7M107.3 82.2h2.7M107.3 86.3h2.7M42 151.7h1.9M48.2 153.1h1.9M48.2 150.3h1.9M55.6 154.4h1.9M55.6 153.1h1.9M55.6 151.7h1.9M65.9 154.4h1.9M65.9 153.1h1.9"/>
<path d="M65.9 151.7h1.9M104.6 166.7h1.3M110 166.7h1.4"/>
</g>
<g fill="none" stroke="#000080" stroke-width=".14">
<path d="M217.5 50.9v4.1M229.8 50.9v4.1M99.1 82.2h1.4M99.1 86.3h1.4M110 82.2h1.4M110 86.3h1.4M217.5 83.6v4.1M229.8 83.6h4.1M198.5 124.4v2.8M209.4 124.4v2.8M67.8 153.1h2.7M67.8 154.4h2.7"/>
<path d="M67.8 151.7h2.7M101.8 166.7h2.8M111.4 166.7h5.4"/>
</g>
<path d="M70.5 159.9h15v2.7h-15zM74.6 159.9v2.7M80.1 159.9v2.7M70.5 161.2h15" fill="none" stroke="#0000b4" stroke-width=".14"/>
<g fill="none" stroke="#800000" stroke-width=".14">
<path d="M216.2 49.5h2.7M216.6 49.1h1.9M217 48.7h1.1M217.4 48.3h.3M217.5 49.5v1.4M238.6 49.5h1.4M239.3 49.5v1.4M111.4 82.2h1.3M111.4 86.3h1.3M112.7 81.5v1.4M112.7 84.9v2.8M113.1 85.3v1.9"/>
<path d="M113.6 85.7v1.1M114 86.2v.2M216.2 82.2h2.7M216.6 81.8h1.9M217 81.4h1.1M217.4 81h.3M217.5 82.2v1.4M40.6 151v1.4M40.6 151.7h1.4M69.9 150.3h1.3M70.5 150.3v1.4M100.5 168h2.7"/>
<path d="M100.9 168.5h1.9M101.3 168.9h1.1M101.7 169.3h.3M101.8 166.7v1.3"/>
</g>
<g fill="none" stroke="#00f" stroke-width=".14">
<path d="M103.2 81.8h4.1v.8h-4.1zM103.2 85.9h4.1v.8h-4.1zM47.4 150.3l-2.7 1.4M105.9 165.7h4.1v.2h-4.1zM106.2 166.3h.3l.2 .2v.3l-.2 .3h-.3l-.3-.3v-.3zM107.4 165.9v-.6h1.1v.6M107.4 165.6h1.1M107.4 165.5h1.1M107.6 165.3v.6M107.7 165.3v.6M107.8 165.3v.6M108 165.3v.6"/>
<path d="M108.1 165.3v.6M108.2 165.3v.6M108.4 165.3v.6M109.5 166.3h.2l.3 .2v.3l-.3 .3h-.2l-.3-.3v-.3z"/>
</g>
<path d="M247.5 35.9h-220.5v143h220.5v-65.4M92.3 113.5v65.4M92.3 147.6h155.2" fill="none" stroke="#00f" stroke-width=".68"/>
<path d="M69.2 59h2.6v8.1h-2.6z" fill-rule="evenodd" fill="#ffffb0" stroke="#800000" stroke-width=".13"/>
<path d="M71.9 65.9h2.7M71.9 64.5h2.7M71.9 63.1h2.7M71.9 61.8h2.7M71.9 60.4h2.7" fill="none" stroke="#000" stroke-width=".14"/>
<path d="M52.9 65.9h5.4M56.9 61.8h1.4M74.6 65.9h4.1M74.6 64.5h4.1M74.6 63.1h4.1M74.6 61.8h4.1M74.6 60.4h4.1M48.8 172.1h2.7M61 172.1h8.2M69.2 165.3h-4.1v2.7" fill="none" stroke="#000080" stroke-width=".14"/>
<path d="M77.3 59h2.8M77.8 58.6h1.9M78.2 58.2h1.1M78.6 57.8h.2M78.7 59v1.4M69.2 165.3h1.3M69.2 172.1h1.3M70.5 164v2.7M70.5 171.4v1.4M71 164.4v1.9M71.4 164.8v1.1M71.8 165.2v.3" fill="none" stroke="#800000" stroke-width=".14"/>
<path d="M167.2 113.5v65.4" fill="none" stroke="#00f" stroke-width=".68"/>
<path d="M140 166.7h6.6v2.6h-6.6z" fill-rule="evenodd" fill="#ffffb0" stroke="#800000" stroke-width=".13"/>
<path d="M229.8 50.9h2.7M236.6 50.9h2.7M133.2 159.9h2.7M140 159.9h2.7M144 159.9h2.8M150.8 159.9h2.8M141.3 164v2.7M142.7 164v2.7M144 164v2.7M145.4 164v2.7" fill="none" stroke="#000" stroke-width=".14"/>
<path d="M232.5 50.3h4.1v1.1h-4.1zM232.5 50.9h4.1M135.9 159.9h4.1M146.8 159.5h4v.8h-4z" fill="none" stroke="#00f" stroke-width=".14"/>
<g fill="#00f" stroke="#00f" stroke-width=".14">
<path d="M137.2 158.5l1.4 1.4-1.4 1.3z"/>
<path d="M138.6 158.5h.1v2.7h-.1z" fill-rule="evenodd"/>
</g>
<path d="M145.4 164h1.4M146.8 162.6v2.7M147.2 163v1.9M147.6 163.4v1.1M148 163.8v.3M236.6 174.9h1.4M238 173.5v2.7M238.4 173.9v1.9M238.8 174.3v1.1M239.2 174.7v.3" fill="none" stroke="#800000" stroke-width=".14"/>
<path d="M229.8 83.6v4.1M130.4 159.9h2.8M142.7 159.9v4.1M144 159.9v4.1M153.6 159.9h2.7M214.8 154.4h1.4M236.6 154.4v20.5M137.2 164h4.1M214.8 161.2h1.4M214.8 168h1.4M214.8 174.9h1.4" fill="none" stroke="#000080" stroke-width=".14"/>
<g fill="#800000" stroke="#800000" stroke-width=".13">
<circle cx="41.9" cy="131.2" r=".21"/>
<circle cx="54.1" cy="140.7" r=".21"/>
<circle cx="63.7" cy="131.2" r=".21"/>
<circle cx="63.7" cy="140.7" r=".21"/>
<circle cx="124.9" cy="135.3" r=".21"/>
<circle cx="133.1" cy="129.8" r=".21"/>
<circle cx="209.3" cy="129.8" r=".21"/>
<circle cx="198.4" cy="129.8" r=".21"/>
<circle cx="236.5" cy="168" r=".21"/>
<circle cx="236.5" cy="161.2" r=".21"/>
<circle cx="236.5" cy="174.8" r=".21"/>
</g>
<path d="M154.9 56.3h39.4v39.4h-39.4z" fill-rule="evenodd" fill="#ffffb0" stroke="#800000" stroke-width=".14"/>
<g fill="none" stroke="#000" stroke-width=".14">
<path d="M167.2 52.2v4.1M168.5 52.2v4.1M169.9 52.2v4.1M171.3 52.2v4.1M172.6 52.2v4.1M174 52.2v4.1M175.3 52.2v4.1M176.7 52.2v4.1M178.1 52.2v4.1M179.4 52.2v4.1M180.8 52.2v4.1M182.2 52.2v4.1"/>
<path d="M144 69.9v1.4M144 72.7v1.3M144 75.4v1.4M144 78.1v1.4M150.8 79.5h4.1M150.8 78.1h4.1M150.8 76.8h4.1M150.8 74h4.1M150.8 72.7h4.1M150.8 71.3h4.1M150.8 69.9h4.1M150.8 68.6h4.1"/>
<path d="M150.8 75.4h4.1M194.4 79.5h4.1M194.4 78.1h4.1M194.4 76.8h4.1M194.4 74h4.1M194.4 72.7h4.1M194.4 71.3h4.1M194.4 69.9h4.1M194.4 68.6h4.1M194.4 75.4h4.1M150.8 83.6h4.1M150.8 80.8h4.1"/>
<path d="M150.8 82.2h4.1M167.2 95.8v4.1M168.5 95.8v4.1M169.9 95.8v4.1M171.3 95.8v4.1M172.6 95.8v4.1M174 95.8v4.1M175.3 95.8v4.1M176.7 95.8v4.1M178.1 95.8v4.1M179.4 95.8v4.1M180.8 95.8v4.1"/>
<path d="M182.2 95.8v4.1M194.4 83.6h4.1M194.4 80.8h4.1M194.4 82.2h4.1"/>
</g>
<g fill="none" stroke="#000080" stroke-width=".14">
<path d="M167.2 49.5v2.7M168.5 49.5v2.7M169.9 49.5v2.7M171.3 49.5v2.7M172.6 49.5v2.7M174 49.5v2.7M175.3 49.5v2.7M176.7 49.5v2.7M178.1 49.5v2.7M179.4 49.5v2.7M180.8 49.5v2.7M182.2 49.5v2.7"/>
<path d="M216.2 56.3h1.3M216.2 57.7h1.3M216.2 59h1.3M229.8 56.3h1.4M229.8 57.7h1.4M229.8 59h1.4M140 75.4h10.8M140 74h10.8M146.8 68.6h4M146.8 69.9h4M146.8 79.5h4M146.8 76.8h4"/>
<path d="M146.8 71.3h4M146.8 72.7h4M146.8 78.1h4M198.5 68.6h4.1M198.5 69.9h4.1M198.5 79.5h4.1M198.5 76.8h4.1M198.5 75.4h4.1M198.5 71.3h4.1M198.5 72.7h4.1M198.5 78.1h4.1M198.5 74h4.1"/>
<path d="M216.2 68.6h1.3M216.2 69.9h1.3M216.2 71.3h1.3M216.2 67.2h1.3M216.2 60.4h1.3M216.2 61.8h1.3M216.2 63.1h1.3M216.2 64.5h1.3M216.2 65.9h1.3M229.8 69.9h1.4M229.8 60.4h1.4M229.8 61.8h1.4"/>
<path d="M229.8 63.1h1.4M229.8 64.5h1.4M229.8 65.9h1.4M146.8 80.8h4M146.8 82.2h4M146.8 83.6h4M167.2 99.9v2.7M168.5 99.9v2.7M169.9 99.9v2.7M171.3 99.9v2.7M172.6 99.9v2.7M174 99.9v2.7"/>
<path d="M175.3 99.9v2.7M176.7 99.9v2.7M178.1 99.9v2.7M179.4 99.9v2.7M180.8 99.9v2.7M182.2 99.9v2.7M198.5 80.8h4.1M198.5 82.2h4.1M198.5 83.6h4.1M216.2 89h1.3M216.2 90.4h1.3M216.2 91.7h1.3"/>
<path d="M216.2 93.1h1.3M216.2 99.9h1.3M216.2 98.6h1.3M216.2 97.2h1.3M216.2 95.8h1.3M216.2 94.5h1.3M229.8 89h1.4M229.8 90.4h1.4M229.8 91.7h1.4M229.8 93.1h1.4M229.8 99.9h1.4M229.8 98.6h1.4"/>
<path d="M229.8 97.2h1.4M229.8 95.8h1.4M229.8 94.5h1.4M216.2 104h1.3M216.2 102.6h1.3M216.2 101.3h1.3M229.8 104h1.4M229.8 102.6h1.4M229.8 101.3h1.4"/>
</g>
<path d="M142.8 72.3h2.5M142.8 71.7h2.5M142.8 77.7h2.5M142.8 77.2h2.5M144 71.3v.4M144 72.3v.4M144 76.8v.4M144 77.7v.4" fill="none" stroke="#00f" stroke-width=".14"/>
<g fill="none" stroke="#800000" stroke-width=".14">
<path d="M142.7 68.6h2.7M143.1 68.2h1.9M143.5 67.8h1.1M143.9 67.4h.3M144 68.6v1.3M144 79.5v1.3M202.6 76.8h1.3M203.9 75.4v2.7M204.3 75.8v1.9M204.7 76.2v1.1M205.2 76.6v.3M142.7 80.8h2.7"/>
<path d="M143.1 81.3h1.9M143.5 81.7h1.1M143.9 82.1h.3"/>
</g>
<path d="M220.3 49.5h6.6v23h-6.6z" fill-rule="evenodd" fill="#ffffb0" stroke="#800000" stroke-width=".13"/>
<g fill="none" stroke="#000" stroke-width=".13">
<circle cx="219.8" cy="54.9" r=".34"/>
<circle cx="219.8" cy="59" r=".34"/>
<circle cx="219.8" cy="50.8" r=".34"/>
<circle cx="219.8" cy="53.5" r=".34"/>
<circle cx="219.8" cy="56.3" r=".34"/>
<circle cx="219.8" cy="57.6" r=".34"/>
<circle cx="219.8" cy="52.2" r=".34"/>
<circle cx="227.4" cy="59" r=".34"/>
<circle cx="227.4" cy="54.9" r=".34"/>
<circle cx="227.4" cy="56.3" r=".34"/>
<circle cx="227.4" cy="53.5" r=".34"/>
<circle cx="227.4" cy="57.6" r=".34"/>
<circle cx="227.4" cy="50.8" r=".34"/>
<circle cx="227.4" cy="52.2" r=".34"/>
<circle cx="219.8" cy="65.8" r=".34"/>
<circle cx="219.8" cy="71.2" r=".34"/>
<circle cx="219.8" cy="68.5" r=".34"/>
<circle cx="219.8" cy="64.4" r=".34"/>
<circle cx="219.8" cy="67.1" r=".34"/>
<circle cx="219.8" cy="61.7" r=".34"/>
<circle cx="219.8" cy="69.9" r=".34"/>
<circle cx="219.8" cy="60.3" r=".34"/>
<circle cx="219.8" cy="63.1" r=".34"/>
<circle cx="227.4" cy="65.8" r=".34"/>
<circle cx="227.4" cy="67.1" r=".34"/>
<circle cx="227.4" cy="69.9" r=".34"/>
<circle cx="227.4" cy="60.3" r=".34"/>
<circle cx="227.4" cy="61.7" r=".34"/>
<circle cx="227.4" cy="64.4" r=".34"/>
<circle cx="227.4" cy="68.5" r=".34"/>
<circle cx="227.4" cy="71.2" r=".34"/>
<circle cx="227.4" cy="63.1" r=".34"/>
</g>
<g fill="none" stroke="#000" stroke-width=".14">
<path d="M217.5 50.9h1.9M217.5 52.2h1.9M217.5 53.6h1.9M217.5 55h1.9M217.5 56.3h1.9M217.5 57.7h1.9M217.5 59h1.9M227.9 50.9h1.9M227.9 52.2h1.9M227.9 53.6h1.9M227.9 55h1.9M227.9 56.3h1.9"/>
<path d="M227.9 57.7h1.9M227.9 59h1.9M217.5 60.4h1.9M217.5 61.8h1.9M217.5 63.1h1.9M217.5 64.5h1.9M217.5 65.9h1.9M217.5 67.2h1.9M217.5 68.6h1.9M217.5 69.9h1.9M217.5 71.3h1.9M227.9 60.4h1.9"/>
<path d="M227.9 61.8h1.9M227.9 63.1h1.9M227.9 64.5h1.9M227.9 65.9h1.9M227.9 67.2h1.9M227.9 68.6h1.9M227.9 69.9h1.9M227.9 71.3h1.9"/>
</g>
<path d="M220.3 82.2h6.6v23h-6.6z" fill-rule="evenodd" fill="#ffffb0" stroke="#800000" stroke-width=".13"/>
<g fill="none" stroke="#000" stroke-width=".13">
<circle cx="219.8" cy="91.7" r=".34"/>
<circle cx="219.8" cy="93" r=".34"/>
<circle cx="219.8" cy="95.8" r=".34"/>
<circle cx="219.8" cy="84.9" r=".34"/>
<circle cx="219.8" cy="90.3" r=".34"/>
<circle cx="219.8" cy="97.1" r=".34"/>
<circle cx="219.8" cy="99.8" r=".34"/>
<circle cx="219.8" cy="87.6" r=".34"/>
<circle cx="219.8" cy="98.5" r=".34"/>
<circle cx="219.8" cy="83.5" r=".34"/>
<circle cx="219.8" cy="86.2" r=".34"/>
<circle cx="219.8" cy="89" r=".34"/>
<circle cx="219.8" cy="94.4" r=".34"/>
<circle cx="227.4" cy="87.6" r=".34"/>
<circle cx="227.4" cy="90.3" r=".34"/>
<circle cx="227.4" cy="91.7" r=".34"/>
<circle cx="227.4" cy="98.5" r=".34"/>
<circle cx="227.4" cy="89" r=".34"/>
<circle cx="227.4" cy="86.2" r=".34"/>
<circle cx="227.4" cy="94.4" r=".34"/>
<circle cx="227.4" cy="97.1" r=".34"/>
<circle cx="227.4" cy="83.5" r=".34"/>
<circle cx="227.4" cy="84.9" r=".34"/>
<circle cx="227.4" cy="93" r=".34"/>
<circle cx="227.4" cy="95.8" r=".34"/>
<circle cx="227.4" cy="99.8" r=".34"/>
<circle cx="219.8" cy="102.6" r=".34"/>
<circle cx="219.8" cy="101.2" r=".34"/>
<circle cx="219.8" cy="103.9" r=".34"/>
<circle cx="227.4" cy="102.6" r=".34"/>
<circle cx="227.4" cy="103.9" r=".34"/>
<circle cx="227.4" cy="101.2" r=".34"/>
</g>
<g fill="none" stroke="#000" stroke-width=".14">
<path d="M81.4 90.4v1.3M81.4 93.1v1.4M217.5 83.6h1.9M217.5 84.9h1.9M217.5 86.3h1.9M217.5 87.7h1.9M217.5 89h1.9M217.5 90.4h1.9M217.5 91.7h1.9M217.5 93.1h1.9M217.5 94.5h1.9M217.5 95.8h1.9"/>
<path d="M217.5 97.2h1.9M217.5 98.6h1.9M217.5 99.9h1.9M227.9 83.6h1.9M227.9 84.9h1.9M227.9 86.3h1.9M227.9 87.7h1.9M227.9 89h1.9M227.9 90.4h1.9M227.9 91.7h1.9M227.9 93.1h1.9M227.9 94.5h1.9"/>
<path d="M227.9 95.8h1.9M227.9 97.2h1.9M227.9 98.6h1.9M227.9 99.9h1.9M217.5 101.3h1.9M217.5 102.6h1.9M217.5 104h1.9M227.9 101.3h1.9M227.9 102.6h1.9M227.9 104h1.9M67.8 168v1.4M67.8 170.8v1.3"/>
</g>
<g fill="#800000" stroke="#800000" stroke-width=".13">
<circle cx="217.5" cy="50.8" r=".21"/>
<circle cx="229.7" cy="50.8" r=".21"/>
<circle cx="217.5" cy="52.2" r=".21"/>
<circle cx="229.7" cy="52.2" r=".21"/>
<circle cx="217.5" cy="53.5" r=".21"/>
<circle cx="229.7" cy="53.5" r=".21"/>
<circle cx="217.5" cy="83.5" r=".21"/>
<circle cx="229.7" cy="83.5" r=".21"/>
<circle cx="217.5" cy="84.9" r=".21"/>
<circle cx="217.5" cy="86.2" r=".21"/>
<circle cx="229.7" cy="86.2" r=".21"/>
<circle cx="229.7" cy="84.9" r=".21"/>
<circle cx="144" cy="74" r=".21"/>
<circle cx="144" cy="75.3" r=".21"/>
<circle cx="65" cy="172.1" r=".21"/>
<circle cx="67.8" cy="172.1" r=".21"/>
<circle cx="67.8" cy="165.2" r=".21"/>
<circle cx="96.3" cy="50.8" r=".21"/>
</g>
<g fill="none" stroke="#000080" stroke-width=".14">
<path d="M96.4 50.9h12.3v9.5M104.6 64.5h5.4M229.8 71.3h1.4M35.2 94.5h2.7M35.2 93.1h2.7M35.2 95.8h2.7M35.2 97.2h2.7M35.2 98.6h2.7M35.2 99.9h2.7M35.2 91.7h2.7M74.6 94.5h6.8M74.6 93.1h4.1"/>
<path d="M74.6 89v2.7M74.6 95.8h4.1M74.6 97.2h4.1M74.6 98.6h4.1M74.6 99.9h4.1M82.8 90.4h-4.1v1.3M35.2 102.6h2.7M35.2 101.3h2.7M35.2 104h2.7M74.6 102.6h4.1M74.6 101.3h4.1M74.6 104h4.1"/>
<path d="M50.1 153.1h2.8M67.8 165.3v2.7"/>
</g>
<path d="M80.2 92.7h2.5M80.2 92.2h2.5M81.4 91.7v.5M81.4 92.7v.4M66.5 170.8h2.7M67.8 169.4v.8M69.1 169.6a2.11 2.11 0 0 1-2.6 .1" fill="none" stroke="#00f" stroke-width=".14"/>
<path d="M95 49.5h2.8M95.5 49.1h1.9M95.9 48.7h1M96.3 48.3h.2M96.4 49.5v1.4" fill="none" stroke="#781915" stroke-width=".14"/>
<path d="M42 86.3h28.4v23h-28.4z" fill-rule="evenodd" fill="#ffffb0" stroke="#800000" stroke-width=".14"/>
<g fill="none" stroke="#000" stroke-width=".14">
<path d="M37.9 94.5h4.1M37.9 95.8h4.1M37.9 97.2h4.1M37.9 98.6h4.1M37.9 99.9h4.1M37.9 93.1h4.1M37.9 91.7h4.1M70.5 94.5h4.1M70.5 95.8h4.1M70.5 97.2h4.1M70.5 98.6h4.1M70.5 99.9h4.1"/>
<path d="M70.5 93.1h4.1M70.5 91.7h4.1M76 87.7v1.3M76 90.4v1.3M37.9 101.3h4.1M37.9 102.6h4.1M37.9 104h4.1M70.5 101.3h4.1M70.5 102.6h4.1M70.5 104h4.1"/>
</g>
<path d="M76 91.7v2.8M78.7 91.7v1.4M82.8 90.4h2.7M85.5 87.7h-10.9v1.3" fill="none" stroke="#000080" stroke-width=".14"/>
<path d="M81.4 94.5h1.4M82.8 93.1v2.7M83.2 93.5v1.9M83.6 93.9v1.1M84 94.3v.3" fill="none" stroke="#800000" stroke-width=".14"/>
<path d="M74.8 90h2.4M74.8 89.4h2.4M76 89v.4M76 90v.4" fill="none" stroke="#00f" stroke-width=".14"/>
<g fill="#800000" stroke="#800000" stroke-width=".13">
<circle cx="81.4" cy="90.3" r=".21"/>
<circle cx="81.4" cy="94.4" r=".21"/>
<circle cx="75.9" cy="87.6" r=".21"/>
<circle cx="75.9" cy="94.4" r=".21"/>
</g>
<use href="#words"/>
</svg>
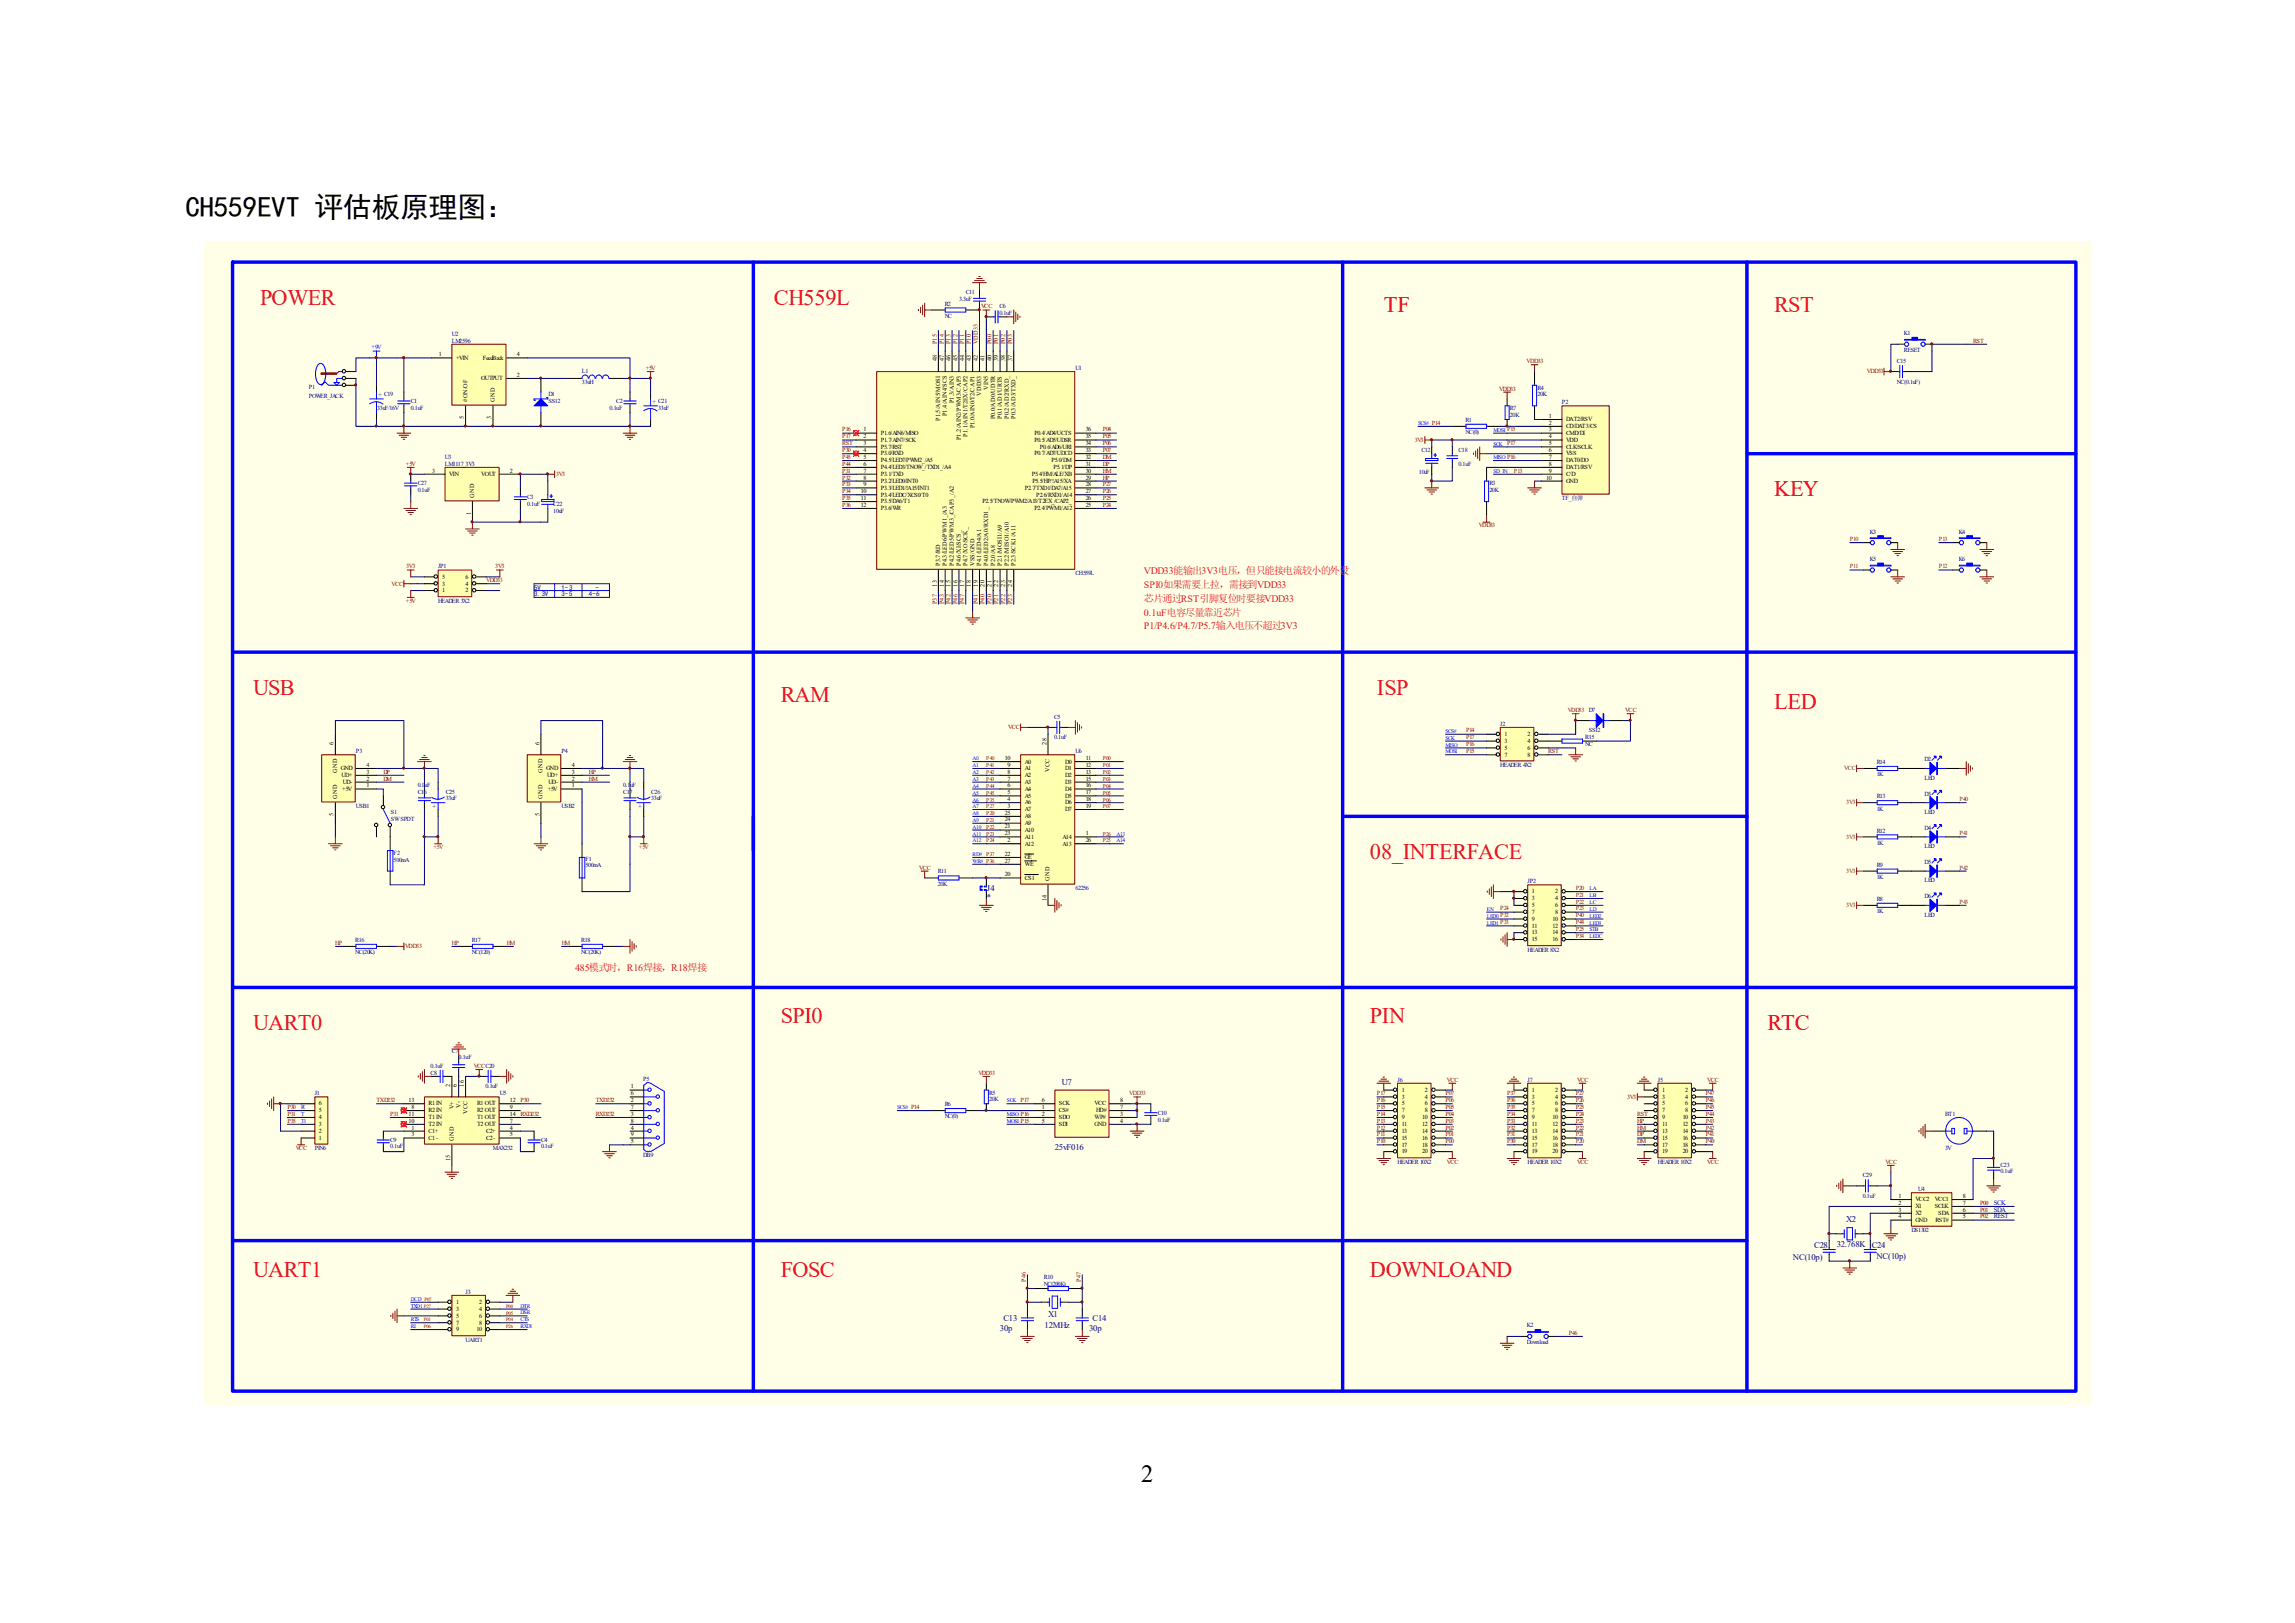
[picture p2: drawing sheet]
<svg xmlns="http://www.w3.org/2000/svg" width="297mm" height="210mm" viewBox="0 0 297 210" stroke-linecap="round" stroke-linejoin="round" font-family="sans-serif">
<defs><g id="words">
<text font-size="3.7" x="24" y="28.1">CH559EVT 评估板原理图：</text>
<text font-size="3.2" x="147.7" y="191.7">2</text>
<g font-size="2.9" fill="#ee0e22">
<text x="33.7" y="39.5">POWER</text>
<text x="100.2" y="39.5">CH559L</text>
<text x="229.6" y="40.3">RST</text>
<text x="32.8" y="89.9">USB</text>
<text x="178.2" y="89.9">ISP</text>
<text x="101.1" y="90.8">RAM</text>
<text x="229.6" y="91.7">LED</text>
<text x="177.3" y="111.2">08_INTERFACE</text>
<text x="32.8" y="133.3">UART0</text>
<text x="101.1" y="132.4">SPI0</text>
<text x="177.3" y="132.4">PIN</text>
<text x="32.8" y="165.2">UART1</text>
<text x="101.1" y="165.2">FOSC</text>
<text x="177.3" y="165.2">DOWNLOAND</text>
</g>
<g font-size="2.9" fill="#f00">
<text x="179.1" y="40.3">TF</text>
<text x="229.6" y="64.2">KEY</text>
<text x="228.7" y="133.3">RTC</text>
</g>
<g font-size="1.3" fill="#ee0e22">
<text x="148" y="74.3">VDD33能输出3V3电压，但只能接电流较小的外设</text>
<text x="148" y="76.1">SPI0如果需要上拉，需接到VDD33</text>
<text x="148" y="77.9">芯片通过RST引脚复位时要接VDD33</text>
<text x="148" y="81.5">P1/P4.6/P4.7/P5.7输入电压不超过3V3</text>
<text x="148" y="79.7">0.1uF电容尽量靠近芯片</text>
<text x="74.4" y="125.7">485模式时，R16焊接，R18焊接</text>
</g>
<g font-size="1.1" fill="#000080">
<text x="127.7" y="115.3">J4</text>
<text x="127.7" y="116.5">*</text>
<text x="137.4" y="140.4">U7</text>
<text x="136.5" y="148.8">25vF016</text>
<text x="234.8" y="161.5">C28</text>
<text x="237.7" y="161.3">32.768K</text>
<text x="238.9" y="158.1">X2</text>
<text x="242.2" y="161.5">C24</text>
<text x="232" y="163.1">NC(10p)</text>
<text x="242.9" y="162.9">NC(10p)</text>
<text x="129.4" y="172.3">30p</text>
<text x="129.9" y="170.9">C13</text>
<text x="135.2" y="171.8">12MHz</text>
<text x="135.6" y="170.5">X1</text>
<text x="141" y="172.3">30p</text>
<text x="141.4" y="170.9">C14</text>
</g>
<g font-size=".9" fill="#000080">
<text x="69.1" y="76.3">5V</text>
<text x="69.1" y="77.2">3.3V</text>
<text x="72.7" y="76.3">1-3</text>
<text x="72.7" y="77.2">3-5</text>
<text x="76.2" y="77.2">4-6</text>
<text x="77.1" y="76.3">-</text>
</g>
<g font-size=".9" fill="#0000bf">
<text x="258" y="155.9">SCK</text>
<text x="258" y="156.8">SDA</text>
<text x="258" y="157.7">REST</text>
</g>
<g font-size=".8" fill="#000080">
<text x="122.3" y="39.5">R2</text>
<text x="122.3" y="41.1">NC</text>
<text x="124.1" y="38.9">3.3uF</text>
<text x="125" y="38.1">C11</text>
<text x="129.3" y="39.9">C6</text>
<text x="129.3" y="40.8">0.1uF</text>
<text x="58.5" y="43.4">U2</text>
<text x="58.5" y="44.3">LM2596</text>
<text x="139.2" y="47.9">U1</text>
<text x="245.5" y="47">C15</text>
<text x="246.4" y="43.3">K1</text>
<text x="246.4" y="45.5">RESET</text>
<text x="40" y="50.3">P1</text>
<text x="40" y="51.5">POWER_JACK</text>
<text x="48.8" y="53.1">33uF/16V</text>
<text x="49" y="51.4">+ C19</text>
<text x="53.2" y="52.2">C1</text>
<text x="53.2" y="53.1">0.1uF</text>
<text x="71" y="51.3">D1</text>
<text x="71" y="52.2">SS12</text>
<text x="75.3" y="48.3">L1</text>
<text x="75.3" y="49.7">33uH</text>
<text x="78.9" y="53.1">0.1uF</text>
<text x="79.8" y="52.2">C2</text>
<text x="84.5" y="52.3">+ C21</text>
<text x="85.2" y="53.1">33uF</text>
<text x="195.4" y="53.1">R7</text>
<text x="195.4" y="54">20K</text>
<text x="199" y="50.5">R4</text>
<text x="199" y="51.3">20K</text>
<text x="202.1" y="52.3">P2</text>
<text x="245.5" y="49.7">NC(0.1uF)</text>
<text x="57.6" y="59.4">U3</text>
<text x="184" y="58.5">C12</text>
<text x="188.8" y="58.5">C18</text>
<text x="189.7" y="54.6">R1</text>
<text x="189.7" y="56.2">NC(0)</text>
<text x="54.1" y="62.8">C27</text>
<text x="54.1" y="63.7">0.1uF</text>
<text x="57.6" y="60.3">LM1117_3V3</text>
<text x="68.2" y="64.6">C3</text>
<text x="68.2" y="65.5">0.1uF</text>
<text x="71.6" y="65.5">C22</text>
<text x="183.6" y="61.3">10uF</text>
<text x="188.8" y="60.3">0.1uF</text>
<text x="192.7" y="62.8">R3</text>
<text x="192.7" y="63.7">20K</text>
<text x="202.1" y="64.7">TF_自弹</text>
<text x="71.6" y="66.4">10uF</text>
<text x="242" y="69">K3</text>
<text x="253.5" y="69">K4</text>
<text x="56.7" y="73.5">JP1</text>
<text x="56.7" y="78">HEADER 3X2</text>
<text x="139.2" y="74.4">CH559L</text>
<text x="242" y="72.6">K5</text>
<text x="253.5" y="72.6">K6</text>
<text x="136.4" y="93">C5</text>
<text x="136.4" y="95.7">0.1uF</text>
<text x="194.1" y="93.9">J2</text>
<text x="205.2" y="95.6">R15</text>
<text x="205.6" y="94.8">SS12</text>
<text x="46.1" y="97.4">P3</text>
<text x="54.1" y="101.8">0.1uF</text>
<text x="72.7" y="97.4">P4</text>
<text x="80.6" y="101.8">0.1uF</text>
<text x="139.2" y="97.4">U6</text>
<text x="194.1" y="99.2">HEADER 4X2</text>
<text x="205.2" y="96.5">NC</text>
<text x="242.9" y="98.9">R14</text>
<text x="242.9" y="100.5">1K</text>
<text x="249.1" y="98.5">D2</text>
<text x="249.1" y="100.9">LED</text>
<text x="46.1" y="104.5">USB1</text>
<text x="50.6" y="105.3">S1</text>
<text x="50.6" y="106.2">SW SPDT</text>
<text x="54.1" y="102.7">C16</text>
<text x="56.4" y="104.1" transform="rotate(-180 56.4 104.1)">+</text>
<text x="57.7" y="102.7">C25</text>
<text x="57.7" y="103.5">33uF</text>
<text x="72.7" y="104.5">USB2</text>
<text x="80.6" y="102.7">C17</text>
<text x="83.1" y="104.1" transform="rotate(-180 83.1 104.1)">+</text>
<text x="84.3" y="102.7">C26</text>
<text x="84.3" y="103.5">33uF</text>
<text x="242.9" y="107.7">R12</text>
<text x="242.9" y="103.3">R13</text>
<text x="242.9" y="104.9">1K</text>
<text x="249.1" y="107.4">D4</text>
<text x="249.1" y="103">D3</text>
<text x="249.1" y="105.3">LED</text>
<text x="50.9" y="110.7">F2</text>
<text x="50.9" y="111.5">500mA</text>
<text x="75.8" y="111.5">F1</text>
<text x="75.8" y="112.2">500mA</text>
<text x="121.4" y="113">R11</text>
<text x="242.9" y="112.1">R9</text>
<text x="242.9" y="113.7">1K</text>
<text x="242.9" y="109.3">1K</text>
<text x="249.1" y="111.8">D5</text>
<text x="249.1" y="109.8">LED</text>
<text x="121.4" y="114.6">20K</text>
<text x="139.2" y="115.1">62256</text>
<text x="197.7" y="114.3">JP2</text>
<text x="242.9" y="116.6">R8</text>
<text x="242.9" y="118.2">1K</text>
<text x="249.1" y="116.2">D6</text>
<text x="249.1" y="118.6">LED</text>
<text x="249.1" y="114.2">LED</text>
<text x="46" y="121.9">R16</text>
<text x="46" y="123.5">NC(20K)</text>
<text x="61" y="121.9">R17</text>
<text x="61" y="123.5">NC(120)</text>
<text x="75.2" y="121.9">R18</text>
<text x="75.2" y="123.5">NC(20K)</text>
<text x="197.7" y="123.1">HEADER 8X2</text>
<text x="58.5" y="136.2">C7</text>
<text x="59.4" y="137">0.1uF</text>
<text x="40.7" y="141.7">J1</text>
<text x="55.7" y="139.1">C8</text>
<text x="55.7" y="138.2">0.1uF</text>
<text x="62.8" y="140.8">0.1uF</text>
<text x="64.7" y="141.7">U5</text>
<text x="83.2" y="139.9">P5</text>
<text x="122.3" y="143.1">R6</text>
<text x="128" y="141.6">R5</text>
<text x="128" y="142.5">20K</text>
<text x="180.9" y="139.9">J6</text>
<text x="197.7" y="139.9">J7</text>
<text x="214.6" y="139.9">J5</text>
<text x="40.7" y="148.8">PIN6</text>
<text x="50.5" y="147.7">C9</text>
<text x="50.5" y="148.5">0.1uF</text>
<text x="63.8" y="148.8">MAX232</text>
<text x="70" y="147.7">C4</text>
<text x="70" y="148.5">0.1uF</text>
<text x="83.2" y="149.8">DB9</text>
<text x="122.3" y="144.7">NC(0)</text>
<text x="149.8" y="144.3">C10</text>
<text x="149.8" y="145.2">0.1uF</text>
<text x="251.7" y="144.4">BT1</text>
<text x="251.7" y="148.8">3V</text>
<text x="180.9" y="150.6">HEADER 10X2</text>
<text x="197.7" y="150.6">HEADER 10X2</text>
<text x="214.6" y="150.6">HEADER 10X2</text>
<text x="241.1" y="152.4">C29</text>
<text x="241.1" y="155">0.1uF</text>
<text x="248.2" y="154.1">U4</text>
<text x="258.9" y="151">C23</text>
<text x="258.9" y="151.8">0.1uF</text>
<text x="247.4" y="159.4">DS1302</text>
<text x="60.2" y="167.4">J3</text>
<text x="135.1" y="165.6">R10</text>
<text x="135.1" y="166.4">NC(200K)</text>
<text x="60.2" y="173.6">UART1</text>
<text x="197.6" y="171.7">K2</text>
<text x="197.6" y="173.9">Download</text>
</g>
<g font-size=".8" fill="#800000">
<text x="127" y="39.9">VCC</text>
<text x="83.6" y="47.9">+5V</text>
<text x="121.2" y="44.5" transform="rotate(-90 121.2 44.5)">P15</text>
<text x="122.1" y="44.5" transform="rotate(-90 122.1 44.5)">P14</text>
<text x="123" y="44.5" transform="rotate(-90 123 44.5)">P13</text>
<text x="123.9" y="44.5" transform="rotate(-90 123.9 44.5)">P12</text>
<text x="124.8" y="44.5" transform="rotate(-90 124.8 44.5)">P11</text>
<text x="125.6" y="44.5" transform="rotate(-90 125.6 44.5)">P10</text>
<text x="128.3" y="44.5" transform="rotate(-90 128.3 44.5)">P00</text>
<text x="129.2" y="44.5" transform="rotate(-90 129.2 44.5)">P01</text>
<text x="130.1" y="44.5" transform="rotate(-90 130.1 44.5)">P02</text>
<text x="131" y="44.5" transform="rotate(-90 131 44.5)">P03</text>
<text x="197.6" y="47">VDD33</text>
<text x="255.4" y="44.3">RST</text>
<text x="194" y="50.5">VDD33</text>
<text x="241.6" y="48.3">VDD33</text>
<text x="109" y="55.8">P16</text>
<text x="109" y="56.7">P17</text>
<text x="109" y="58.5">P30</text>
<text x="109" y="59.4">P45</text>
<text x="109" y="57.6">RST</text>
<text x="142.7" y="55.8">P04</text>
<text x="142.7" y="56.7">P05</text>
<text x="142.7" y="57.6">P06</text>
<text x="142.7" y="58.5">P07</text>
<text x="142.7" y="59.4">DM</text>
<text x="183.1" y="57.1">3V3</text>
<text x="52.5" y="60.3">+5V</text>
<text x="72" y="61.6">3V3</text>
<text x="109" y="61.2">P31</text>
<text x="109" y="62.1">P32</text>
<text x="109" y="62.9">P33</text>
<text x="109" y="63.8">P34</text>
<text x="109" y="64.7">P35</text>
<text x="109" y="65.6">P36</text>
<text x="109" y="60.3">P44</text>
<text x="142.7" y="65.6">P24</text>
<text x="142.7" y="64.7">P25</text>
<text x="142.7" y="63.8">P26</text>
<text x="142.7" y="62.9">P27</text>
<text x="142.7" y="60.3">DP</text>
<text x="142.7" y="61.2">HM</text>
<text x="142.7" y="62.1">HP</text>
<text x="191.4" y="68.2">VDD33</text>
<text x="50.7" y="75.8">VCC</text>
<text x="52.5" y="78">+5V</text>
<text x="52.6" y="73.5">3V3</text>
<text x="64.1" y="73.5">3V3</text>
<text x="121.2" y="78.2" transform="rotate(-90 121.2 78.2)">P37</text>
<text x="122.1" y="78.2" transform="rotate(-90 122.1 78.2)">P43</text>
<text x="123" y="78.2" transform="rotate(-90 123 78.2)">P42</text>
<text x="123.9" y="78.2" transform="rotate(-90 123.9 78.2)">P46</text>
<text x="124.8" y="78.2" transform="rotate(-90 124.8 78.2)">P47</text>
<text x="126.5" y="78.2" transform="rotate(-90 126.5 78.2)">P41</text>
<text x="127.4" y="78.2" transform="rotate(-90 127.4 78.2)">P40</text>
<text x="128.3" y="78.2" transform="rotate(-90 128.3 78.2)">P20</text>
<text x="129.2" y="78.2" transform="rotate(-90 129.2 78.2)">P21</text>
<text x="130.1" y="78.2" transform="rotate(-90 130.1 78.2)">P22</text>
<text x="131" y="78.2" transform="rotate(-90 131 78.2)">P23</text>
<text x="130.5" y="94.4">VCC</text>
<text x="189.7" y="94.8">P14</text>
<text x="189.7" y="95.7">P17</text>
<text x="210.3" y="92.2">VCC</text>
<text x="49.6" y="100.1">DP</text>
<text x="49.6" y="101">DM</text>
<text x="76.2" y="100.1">HP</text>
<text x="76.2" y="101">HM</text>
<text x="189.7" y="97.4">P15</text>
<text x="189.7" y="96.6">P16</text>
<text x="200.4" y="97.4">RST</text>
<text x="119" y="112.5">VCC</text>
<text x="52.5" y="122.7">VDD33</text>
<text x="37.2" y="143.5">P30</text>
<text x="48.7" y="142.6">TXD232</text>
<text x="61.3" y="138.2">VCCC20</text>
<text x="67.4" y="142.6">P30</text>
<text x="77.1" y="142.6">TXD232</text>
<text x="126.6" y="139.1">VDD33</text>
<text x="178.2" y="143.5">P15</text>
<text x="178.2" y="142.6">P16</text>
<text x="178.2" y="141.7">P17</text>
<text x="187.1" y="143.5">P05</text>
<text x="187.1" y="142.6">P06</text>
<text x="187.1" y="141.7">P07</text>
<text x="187.2" y="139.9">VCC</text>
<text x="195" y="143.5">P35</text>
<text x="195" y="142.6">P36</text>
<text x="195" y="141.7">P37</text>
<text x="203.9" y="143.5">P25</text>
<text x="203.9" y="142.6">P26</text>
<text x="203.9" y="141.7">P27</text>
<text x="204.1" y="139.9">VCC</text>
<text x="210.6" y="142.2">3V3</text>
<text x="220.8" y="143.5">P45</text>
<text x="220.8" y="142.6">P46</text>
<text x="220.8" y="141.7">P47</text>
<text x="220.9" y="139.9">VCC</text>
<text x="37.2" y="144.4">P31</text>
<text x="37.2" y="145.3">P35</text>
<text x="38.3" y="148.8">VCC</text>
<text x="50.5" y="144.4">P31</text>
<text x="67.4" y="144.4">RXD232</text>
<text x="77.1" y="144.4">RXD232</text>
<text x="178.2" y="147.9">P10</text>
<text x="178.2" y="147">P11</text>
<text x="178.2" y="146.2">P12</text>
<text x="178.2" y="145.3">P13</text>
<text x="178.2" y="144.4">P14</text>
<text x="187.1" y="147.9">P00</text>
<text x="187.1" y="147">P01</text>
<text x="187.1" y="146.2">P02</text>
<text x="187.1" y="145.3">P03</text>
<text x="187.1" y="144.4">P04</text>
<text x="195" y="147.9">P30</text>
<text x="195" y="147">P31</text>
<text x="195" y="146.2">P32</text>
<text x="195" y="145.3">P33</text>
<text x="195" y="144.4">P34</text>
<text x="203.9" y="146.2">P22</text>
<text x="203.9" y="145.3">P23</text>
<text x="203.9" y="144.4">P24</text>
<text x="211.9" y="147.9">DM</text>
<text x="211.9" y="147">DP</text>
<text x="211.9" y="146.2">HM</text>
<text x="211.9" y="145.3">HP</text>
<text x="211.9" y="144.4">RST</text>
<text x="220.8" y="147.9">P40</text>
<text x="220.8" y="147">P41</text>
<text x="220.8" y="144.4">P44</text>
<text x="187.2" y="150.6">VCC</text>
<text x="204.1" y="150.6">VCC</text>
<text x="220.9" y="150.6">VCC</text>
<text x="244" y="150.6">VCC</text>
<text x="256.2" y="155.9">P00</text>
<text x="256.2" y="156.8">P01</text>
<text x="256.2" y="157.6">P02</text>
<text x="132.8" y="165.9" transform="rotate(-90 132.8 165.9)">P46</text>
<text x="139.9" y="165.9" transform="rotate(-90 139.9 165.9)">P47</text>
<text x="203" y="172.7">P46</text>
</g>
<g font-size=".8" fill="#00f">
<text x="48.1" y="45.2">+9V</text>
<text x="39" y="143.5">R</text>
</g>
<g font-size=".8">
<text x="56.8" y="46.1">1</text>
<text x="59" y="46.5">+VIN</text>
<text x="62.5" y="46.5">FeedBack</text>
<text x="66.9" y="46.1">4</text>
<text x="121.2" y="46.7" transform="rotate(-90 121.2 46.7)">48</text>
<text x="122.1" y="46.7" transform="rotate(-90 122.1 46.7)">47</text>
<text x="123" y="46.7" transform="rotate(-90 123 46.7)">46</text>
<text x="123.9" y="46.7" transform="rotate(-90 123.9 46.7)">45</text>
<text x="124.8" y="46.7" transform="rotate(-90 124.8 46.7)">44</text>
<text x="125.6" y="46.7" transform="rotate(-90 125.6 46.7)">43</text>
<text x="126.5" y="46.7" transform="rotate(-90 126.5 46.7)">42</text>
<text x="127.4" y="46.7" transform="rotate(-90 127.4 46.7)">41</text>
<text x="128.3" y="46.7" transform="rotate(-90 128.3 46.7)">40</text>
<text x="129.2" y="46.7" transform="rotate(-90 129.2 46.7)">39</text>
<text x="130.1" y="46.7" transform="rotate(-90 130.1 46.7)">38</text>
<text x="131" y="46.7" transform="rotate(-90 131 46.7)">37</text>
<text x="60.5" y="52" transform="rotate(-90 60.5 52)">#ON/OF</text>
<text x="62.3" y="49.2">OUTPUT</text>
<text x="64" y="52" transform="rotate(-90 64 52)">GND</text>
<text x="66.9" y="48.8">2</text>
<text x="122.6" y="53.8" transform="rotate(-90 122.6 53.8)">P1.4/AIN4/SCS</text>
<text x="123.4" y="52.2" transform="rotate(-90 123.4 52.2)">P1.3/AIN3</text>
<text x="127" y="51.2" transform="rotate(-90 127 51.2)">VDD33</text>
<text x="127.9" y="50.5" transform="rotate(-90 127.9 50.5)">VIN5</text>
<text x="60" y="54.3" transform="rotate(-90 60 54.3)">5</text>
<text x="63.6" y="54.3" transform="rotate(-90 63.6 54.3)">3</text>
<text x="111.8" y="55.8">1</text>
<text x="111.8" y="56.7">2</text>
<text x="111.8" y="57.6">3</text>
<text x="111.8" y="58.5">4</text>
<text x="111.8" y="59.4">5</text>
<text x="114" y="56.3">P1.6/AIN6/MISO</text>
<text x="114" y="57.1">P1.7/AIN7/SCK</text>
<text x="114" y="58">P5.7/RST</text>
<text x="114" y="58.9">P3.0/RXD</text>
<text x="114" y="59.8">P4.5/LED7/PWM2_/A5</text>
<text x="121.7" y="54.4" transform="rotate(-90 121.7 54.4)">P1.5/AIN5/MOSI</text>
<text x="124.3" y="56.9" transform="rotate(-90 124.3 56.9)">P1.2/AIN2/PWM3/CAP3</text>
<text x="125.2" y="56.5" transform="rotate(-90 125.2 56.5)">P1.1/AIN1/T2EX/CAP2</text>
<text x="126.1" y="55.4" transform="rotate(-90 126.1 55.4)">P1.0/AIN0/T2/CAP1</text>
<text x="128.8" y="54.3" transform="rotate(-90 128.8 54.3)">P0.0/AD0/UDTR</text>
<text x="129.7" y="54.2" transform="rotate(-90 129.7 54.2)">P0.1/AD1/URTS</text>
<text x="130.6" y="54.2" transform="rotate(-90 130.6 54.2)">P0.2/AD2/RXD_</text>
<text x="131.4" y="54.2" transform="rotate(-90 131.4 54.2)">P0.3/AD3/TXD_</text>
<text x="133.9" y="58.9">P0.7/AD7/UDCD</text>
<text x="133.9" y="57.1">P0.5/AD5/UDSR</text>
<text x="133.9" y="56.3">P0.4/AD4/UCTS</text>
<text x="134.6" y="58">P0.6/AD6/URI</text>
<text x="136.1" y="59.8">P5.0/DM</text>
<text x="140.5" y="59.4">32</text>
<text x="140.5" y="58.5">33</text>
<text x="140.5" y="57.6">34</text>
<text x="140.5" y="56.7">35</text>
<text x="140.5" y="55.8">36</text>
<text x="200.5" y="54.1">1</text>
<text x="200.5" y="54.9">2</text>
<text x="200.5" y="55.8">3</text>
<text x="200.5" y="56.7">4</text>
<text x="200.5" y="57.6">5</text>
<text x="200.5" y="58.5">6</text>
<text x="200.5" y="59.4">7</text>
<text x="202.7" y="54.5">DAT2/RSV</text>
<text x="202.7" y="55.4">CD/DAT3/CS</text>
<text x="202.7" y="56.3">CMD/DI</text>
<text x="202.7" y="57.1">VDD</text>
<text x="202.7" y="58">CLK/SCLK</text>
<text x="202.7" y="58.9">VSS</text>
<text x="202.7" y="59.8">DAT0/DO</text>
<text x="55.9" y="61.2">3</text>
<text x="58.1" y="61.6">VIN</text>
<text x="61.4" y="64.4" transform="rotate(-90 61.4 64.4)">GND</text>
<text x="62.3" y="61.6">VOUT</text>
<text x="66" y="61.2">2</text>
<text x="111.4" y="63.8">10</text>
<text x="111.4" y="64.7">11</text>
<text x="111.4" y="65.6">12</text>
<text x="111.8" y="60.3">6</text>
<text x="111.8" y="61.2">7</text>
<text x="111.8" y="62.1">8</text>
<text x="111.8" y="62.9">9</text>
<text x="114" y="60.7">P4.4/LED3/TNOW_/TXD1_/A4</text>
<text x="114" y="61.6">P3.1/TXD</text>
<text x="114" y="62.5">P3.2/LED0/INT0</text>
<text x="114" y="63.4">P3.3/LED1/!A15/INT1</text>
<text x="114" y="64.3">P3.4/LEDC/XCS0/T0</text>
<text x="114" y="65.1">P3.5/DA6/T1</text>
<text x="127.1" y="65.1">P2.5/TNOW/PWM2/A13/T2EX_/CAP2_</text>
<text x="132.6" y="63.4">P2.7/TXD1/DA7/A15</text>
<text x="133.5" y="61.6">P5.4/HM/ALE/XB</text>
<text x="133.6" y="62.5">P5.5/HP/!A15/XA</text>
<text x="134.1" y="64.3">P2.6/RXD1/A14</text>
<text x="136.4" y="60.7">P5.1/DP</text>
<text x="140.5" y="65.6">25</text>
<text x="140.5" y="64.7">26</text>
<text x="140.5" y="63.8">27</text>
<text x="140.5" y="62.9">28</text>
<text x="140.5" y="62.1">29</text>
<text x="140.5" y="61.2">30</text>
<text x="140.5" y="60.3">31</text>
<text x="200.1" y="62.1">10</text>
<text x="200.5" y="60.3">8</text>
<text x="200.5" y="61.2">9</text>
<text x="202.7" y="60.7">DAT1/RSV</text>
<text x="202.7" y="61.6">C/D</text>
<text x="202.7" y="62.5">GND</text>
<text x="60.9" y="66.7" transform="rotate(-90 60.9 66.7)">1</text>
<text x="114" y="66">P3.6/WR</text>
<text x="133.9" y="66">P2.4/PWM1/A12</text>
<text x="57.2" y="76.7">1</text>
<text x="57.2" y="75.8">3</text>
<text x="57.2" y="74.9">5</text>
<text x="60.2" y="76.7">2</text>
<text x="60.2" y="75.8">4</text>
<text x="60.2" y="74.9">6</text>
<text x="121.2" y="75.9" transform="rotate(-90 121.2 75.9)">13</text>
<text x="121.7" y="73.2" transform="rotate(-90 121.7 73.2)">P3.7/RD</text>
<text x="122.1" y="75.9" transform="rotate(-90 122.1 75.9)">14</text>
<text x="122.6" y="73.2" transform="rotate(-90 122.6 73.2)">P4.3/LED6/PWM1_/A3</text>
<text x="123" y="75.9" transform="rotate(-90 123 75.9)">15</text>
<text x="123.4" y="73.2" transform="rotate(-90 123.4 73.2)">P4.2/LED5/PWM3_/CAP3_/A2</text>
<text x="123.9" y="75.9" transform="rotate(-90 123.9 75.9)">16</text>
<text x="124.3" y="73.2" transform="rotate(-90 124.3 73.2)">P4.6/XI/SCS_</text>
<text x="124.8" y="75.9" transform="rotate(-90 124.8 75.9)">17</text>
<text x="125.2" y="73.2" transform="rotate(-90 125.2 73.2)">P4.7/XO/SCK_</text>
<text x="125.6" y="75.9" transform="rotate(-90 125.6 75.9)">18</text>
<text x="126.1" y="73.2" transform="rotate(-90 126.1 73.2)">VSS/GND</text>
<text x="126.5" y="75.9" transform="rotate(-90 126.5 75.9)">19</text>
<text x="127" y="73.2" transform="rotate(-90 127 73.2)">P4.1/LED4/A1</text>
<text x="127.4" y="75.9" transform="rotate(-90 127.4 75.9)">20</text>
<text x="127.9" y="73.2" transform="rotate(-90 127.9 73.2)">P4.0/LED2/A0/RXD1_</text>
<text x="128.3" y="75.9" transform="rotate(-90 128.3 75.9)">21</text>
<text x="128.8" y="73.2" transform="rotate(-90 128.8 73.2)">P2.0/A8</text>
<text x="129.2" y="75.9" transform="rotate(-90 129.2 75.9)">22</text>
<text x="129.7" y="73.2" transform="rotate(-90 129.7 73.2)">P2.1/MOSI1/A9</text>
<text x="130.1" y="75.9" transform="rotate(-90 130.1 75.9)">23</text>
<text x="130.6" y="73.2" transform="rotate(-90 130.6 73.2)">P2.2/MISO1/A10</text>
<text x="131" y="75.9" transform="rotate(-90 131 75.9)">24</text>
<text x="131.4" y="73.2" transform="rotate(-90 131.4 73.2)">P2.3/SCK1/A11</text>
<text x="194.7" y="95.2">1</text>
<text x="197.7" y="95.2">2</text>
<text x="43.2" y="96.4" transform="rotate(-90 43.2 96.4)">6</text>
<text x="43.6" y="100" transform="rotate(-90 43.6 100)">GND</text>
<text x="44.1" y="99.6">GND</text>
<text x="44.2" y="100.5">UD+</text>
<text x="44.4" y="101.4">UD-</text>
<text x="47.4" y="101.9">1</text>
<text x="47.4" y="99.2">4</text>
<text x="47.4" y="100.1">3</text>
<text x="47.4" y="101">2</text>
<text x="69.8" y="96.4" transform="rotate(-90 69.8 96.4)">6</text>
<text x="70.2" y="100" transform="rotate(-90 70.2 100)">GND</text>
<text x="70.7" y="99.6">GND</text>
<text x="70.8" y="100.5">UD+</text>
<text x="71" y="101.4">UD-</text>
<text x="74" y="101.9">1</text>
<text x="74" y="99.2">4</text>
<text x="74" y="100.1">3</text>
<text x="74" y="101">2</text>
<text x="130.1" y="98.3">10</text>
<text x="130.4" y="99.2">9</text>
<text x="130.4" y="100.1">8</text>
<text x="130.4" y="101">7</text>
<text x="130.4" y="101.9">6</text>
<text x="132.6" y="98.8">A0</text>
<text x="132.6" y="99.6">A1</text>
<text x="132.6" y="100.5">A2</text>
<text x="132.6" y="101.4">A3</text>
<text x="135.4" y="96.4" transform="rotate(-90 135.4 96.4)">28</text>
<text x="135.8" y="99.9" transform="rotate(-90 135.8 99.9)">VCC</text>
<text x="137.8" y="98.8">D0</text>
<text x="137.8" y="99.6">D1</text>
<text x="137.8" y="100.5">D2</text>
<text x="137.8" y="101.4">D3</text>
<text x="140.5" y="98.3">11</text>
<text x="140.5" y="99.2">12</text>
<text x="140.5" y="100.1">13</text>
<text x="140.5" y="101">15</text>
<text x="140.5" y="101.9">16</text>
<text x="194.7" y="96.1">3</text>
<text x="194.7" y="97">5</text>
<text x="194.7" y="97.9">7</text>
<text x="197.7" y="96.1">4</text>
<text x="197.7" y="97">6</text>
<text x="197.7" y="97.9">8</text>
<text x="43.2" y="105.6" transform="rotate(-90 43.2 105.6)">5</text>
<text x="43.6" y="103.3" transform="rotate(-90 43.6 103.3)">GND</text>
<text x="44.3" y="102.3">+5V</text>
<text x="69.8" y="105.6" transform="rotate(-90 69.8 105.6)">5</text>
<text x="70.2" y="103.3" transform="rotate(-90 70.2 103.3)">GND</text>
<text x="70.9" y="102.3">+5V</text>
<text x="130.1" y="105.4">25</text>
<text x="130.1" y="106.3">24</text>
<text x="130.1" y="107.2">21</text>
<text x="130.4" y="102.8">5</text>
<text x="130.4" y="103.7">4</text>
<text x="130.4" y="104.5">3</text>
<text x="132.6" y="102.3">A4</text>
<text x="132.6" y="103.2">A5</text>
<text x="132.6" y="104.1">A6</text>
<text x="132.6" y="105">A7</text>
<text x="132.6" y="105.9">A8</text>
<text x="132.6" y="106.8">A9</text>
<text x="132.6" y="107.7">A10</text>
<text x="137.8" y="102.3">D4</text>
<text x="137.8" y="103.2">D5</text>
<text x="137.8" y="104.1">D6</text>
<text x="137.8" y="105">D7</text>
<text x="140.5" y="102.8">17</text>
<text x="140.5" y="103.7">18</text>
<text x="140.5" y="104.5">19</text>
<text x="130.1" y="108.1">23</text>
<text x="130.1" y="113.4">20</text>
<text x="130.1" y="111.6">27</text>
<text x="130.1" y="110.7">22</text>
<text x="130.4" y="109">2</text>
<text x="132.6" y="108.5">A11</text>
<text x="132.6" y="109.4">A12</text>
<text x="132.6" y="113.8">CS1</text>
<text x="132.6" y="112.1">WE</text>
<text x="132.6" y="111.2">OE</text>
<text x="135.8" y="114" transform="rotate(-90 135.8 114)">GND</text>
<text x="137.5" y="108.5">A14</text>
<text x="137.5" y="109.4">A13</text>
<text x="140.5" y="108.1">1</text>
<text x="140.5" y="109">26</text>
<text x="135.4" y="116.6" transform="rotate(-90 135.4 116.6)">14</text>
<text x="198.3" y="115.6">1</text>
<text x="198.3" y="116.5">3</text>
<text x="198.3" y="117.4">5</text>
<text x="198.3" y="118.3">7</text>
<text x="198.3" y="119.2">9</text>
<text x="200.9" y="119.2">10</text>
<text x="201.3" y="115.6">2</text>
<text x="201.3" y="116.5">4</text>
<text x="201.3" y="117.4">6</text>
<text x="201.3" y="118.3">8</text>
<text x="198.3" y="120.1">11</text>
<text x="198.3" y="120.9">13</text>
<text x="198.3" y="121.8">15</text>
<text x="200.9" y="120.1">12</text>
<text x="200.9" y="120.9">14</text>
<text x="200.9" y="121.8">16</text>
<text x="41.3" y="143.9">5</text>
<text x="41.3" y="143">6</text>
<text x="52.9" y="142.6">13</text>
<text x="53.3" y="143.5">8</text>
<text x="55.5" y="143">R1 IN</text>
<text x="55.5" y="143.9">R2 IN</text>
<text x="58.2" y="140.6" transform="rotate(-90 58.2 140.6)">2</text>
<text x="58.7" y="143.6" transform="rotate(-90 58.7 143.6)">V+</text>
<text x="59.1" y="140.6" transform="rotate(-90 59.1 140.6)">6</text>
<text x="59.6" y="143.3" transform="rotate(-90 59.6 143.3)">V-</text>
<text x="60" y="140.6" transform="rotate(-90 60 140.6)">16</text>
<text x="61.8" y="143">R1 OUT</text>
<text x="61.8" y="143.9">R2 OUT</text>
<text x="66" y="142.6">12</text>
<text x="66" y="143.5">9</text>
<text x="81.6" y="140.8">1</text>
<text x="81.6" y="141.7">6</text>
<text x="81.6" y="142.6">2</text>
<text x="81.6" y="143.5">7</text>
<text x="134.8" y="142.6">6</text>
<text x="134.8" y="143.5">1</text>
<text x="137" y="143">SCK</text>
<text x="137" y="143.9">CS#</text>
<text x="141.7" y="143">VCC</text>
<text x="141.9" y="143.9">HD#</text>
<text x="145" y="142.6">8</text>
<text x="145" y="143.5">7</text>
<text x="181.4" y="141.3">1</text>
<text x="181.4" y="142.2">3</text>
<text x="181.4" y="143">5</text>
<text x="181.4" y="143.9">7</text>
<text x="184.4" y="141.3">2</text>
<text x="184.4" y="142.2">4</text>
<text x="184.4" y="143">6</text>
<text x="184.4" y="143.9">8</text>
<text x="198.3" y="141.3">1</text>
<text x="198.3" y="142.2">3</text>
<text x="198.3" y="143">5</text>
<text x="198.3" y="143.9">7</text>
<text x="201.3" y="141.3">2</text>
<text x="201.3" y="142.2">4</text>
<text x="201.3" y="143">6</text>
<text x="201.3" y="143.9">8</text>
<text x="215.1" y="141.3">1</text>
<text x="215.1" y="142.2">3</text>
<text x="215.1" y="143">5</text>
<text x="215.1" y="143.9">7</text>
<text x="218.1" y="141.3">2</text>
<text x="218.1" y="142.2">4</text>
<text x="218.1" y="143">6</text>
<text x="218.1" y="143.9">8</text>
<text x="41.3" y="147.5">1</text>
<text x="41.3" y="146.6">2</text>
<text x="41.3" y="145.7">3</text>
<text x="41.3" y="144.8">4</text>
<text x="52.9" y="144.4">11</text>
<text x="52.9" y="145.3">10</text>
<text x="53.3" y="146.2">1</text>
<text x="53.3" y="147">3</text>
<text x="55.5" y="144.8">T1 IN</text>
<text x="55.5" y="145.7">T2 IN</text>
<text x="55.5" y="146.6">C1+</text>
<text x="55.5" y="147.5">C1 -</text>
<text x="58.7" y="147.6" transform="rotate(-90 58.7 147.6)">GND</text>
<text x="60.5" y="144.1" transform="rotate(-90 60.5 144.1)">VCC</text>
<text x="61.8" y="144.8">T1 OUT</text>
<text x="61.8" y="145.7">T2 OUT</text>
<text x="62.9" y="146.6">C2+</text>
<text x="62.9" y="147.5">C2 -</text>
<text x="66" y="144.4">14</text>
<text x="66" y="145.3">7</text>
<text x="66" y="146.2">4</text>
<text x="66" y="147">5</text>
<text x="81.6" y="144.4">3</text>
<text x="81.6" y="145.3">8</text>
<text x="81.6" y="146.2">4</text>
<text x="81.6" y="147">9</text>
<text x="81.6" y="147.9">5</text>
<text x="134.8" y="144.4">2</text>
<text x="134.8" y="145.3">5</text>
<text x="137" y="144.8">SDO</text>
<text x="137" y="145.7">SDI</text>
<text x="141.7" y="145.7">GND</text>
<text x="141.7" y="144.8">WP#</text>
<text x="145" y="145.3">4</text>
<text x="145" y="144.4">3</text>
<text x="181.4" y="144.8">9</text>
<text x="181.4" y="145.7">11</text>
<text x="181.4" y="146.6">13</text>
<text x="181.4" y="147.5">15</text>
<text x="181.4" y="148.4">17</text>
<text x="181.4" y="149.3">19</text>
<text x="184.1" y="144.8">10</text>
<text x="184.1" y="145.7">12</text>
<text x="184.1" y="146.6">14</text>
<text x="184.1" y="147.5">16</text>
<text x="184.1" y="148.4">18</text>
<text x="184.1" y="149.3">20</text>
<text x="198.3" y="144.8">9</text>
<text x="198.3" y="145.7">11</text>
<text x="198.3" y="146.6">13</text>
<text x="198.3" y="147.5">15</text>
<text x="198.3" y="148.4">17</text>
<text x="198.3" y="149.3">19</text>
<text x="200.9" y="144.8">10</text>
<text x="200.9" y="145.7">12</text>
<text x="200.9" y="146.6">14</text>
<text x="200.9" y="147.5">16</text>
<text x="200.9" y="148.4">18</text>
<text x="200.9" y="149.3">20</text>
<text x="215.1" y="144.8">9</text>
<text x="215.1" y="145.7">11</text>
<text x="215.1" y="146.6">13</text>
<text x="215.1" y="147.5">15</text>
<text x="215.1" y="148.4">17</text>
<text x="215.1" y="149.3">19</text>
<text x="217.8" y="144.8">10</text>
<text x="217.8" y="145.7">12</text>
<text x="217.8" y="146.6">14</text>
<text x="217.8" y="147.5">16</text>
<text x="217.8" y="148.4">18</text>
<text x="217.8" y="149.3">20</text>
<text x="58.2" y="150.3" transform="rotate(-90 58.2 150.3)">15</text>
<text x="245.7" y="155">1</text>
<text x="245.7" y="155.9">2</text>
<text x="247.9" y="155.4">VCC2</text>
<text x="250.4" y="155.4">VCC1</text>
<text x="254" y="155">8</text>
<text x="254" y="155.9">7</text>
<text x="245.7" y="156.8">3</text>
<text x="245.7" y="157.6">4</text>
<text x="247.9" y="156.3">X1</text>
<text x="247.9" y="157.2">X2</text>
<text x="247.9" y="158.1">GND</text>
<text x="250.4" y="156.3">SCLK</text>
<text x="250.5" y="158.1">RST#</text>
<text x="250.8" y="157.2">SDA</text>
<text x="254" y="156.8">6</text>
<text x="254" y="157.6">5</text>
<text x="59" y="168.7">1</text>
<text x="59" y="169.6">3</text>
<text x="59" y="170.5">5</text>
<text x="59" y="171.4">7</text>
<text x="59" y="172.3">9</text>
<text x="61.7" y="172.3">10</text>
<text x="62" y="168.7">2</text>
<text x="62" y="169.6">4</text>
<text x="62" y="170.5">6</text>
<text x="62" y="171.4">8</text>
</g>
<g font-size=".8" fill="#781915">
<text x="126.5" y="44.5" transform="rotate(-90 126.5 44.5)">VDD33</text>
<text x="195.9" y="61.2">P13</text>
<text x="239.4" y="70">P10</text>
<text x="250.9" y="70">P13</text>
<text x="62.9" y="75.3">VDD33</text>
<text x="239.4" y="73.5">P11</text>
<text x="250.9" y="73.5">P12</text>
<text x="202.9" y="92.2">VDD33 D7</text>
<text x="238.7" y="99.6">VCC</text>
<text x="238.9" y="104.1">3V3</text>
<text x="253.6" y="103.7">P40</text>
<text x="56.1" y="109.9">+5V</text>
<text x="82.7" y="109.9">+5V</text>
<text x="238.9" y="112.9">3V3</text>
<text x="238.9" y="108.5">3V3</text>
<text x="253.6" y="108.1">P41</text>
<text x="253.6" y="112.5">P42</text>
<text x="194.1" y="117.8">P24</text>
<text x="203.9" y="119.6">P44</text>
<text x="203.9" y="118.7">P40</text>
<text x="203.9" y="115.1">P20</text>
<text x="203.9" y="116">P21</text>
<text x="203.9" y="116.9">P22</text>
<text x="203.9" y="117.8">P23</text>
<text x="238.9" y="117.4">3V3</text>
<text x="253.6" y="116.9">P43</text>
<text x="43.4" y="122.3">HP</text>
<text x="58.5" y="122.3">HP</text>
<text x="65.6" y="122.3">HM</text>
<text x="72.7" y="122.3">HM</text>
<text x="203.9" y="121.4">P34</text>
<text x="203.9" y="120.5">P25</text>
<text x="146.1" y="141.7">VDD33</text>
<text x="203.9" y="147.9">P20</text>
<text x="203.9" y="147">P21</text>
<text x="220.8" y="146.2">P42</text>
<text x="220.8" y="145.3">P43</text>
</g>
<g font-size=".7" fill="#00f">
<text x="183.5" y="55">SCS# P14</text>
<text x="193.3" y="55.9">MOSI P15</text>
<text x="193.3" y="57.7">SCK P17</text>
<text x="193.3" y="59.4">MISO P16</text>
<text x="187.1" y="94.8">SCS#</text>
<text x="187.1" y="95.7">SCK</text>
<text x="125.9" y="98.4">A0</text>
<text x="125.9" y="99.3">A1</text>
<text x="125.9" y="100.2">A2</text>
<text x="125.9" y="101">A3</text>
<text x="125.9" y="101.9">A4</text>
<text x="187.1" y="97.5">MOSI</text>
<text x="187.1" y="96.6">MISO</text>
<text x="125.9" y="102.8">A5</text>
<text x="125.9" y="103.7">A6</text>
<text x="125.9" y="104.6">A7</text>
<text x="125.9" y="105.5">A8</text>
<text x="125.9" y="106.3">A9</text>
<text x="125.9" y="107.2">A10</text>
<text x="125.9" y="108.1">A11</text>
<text x="125.9" y="109">A12</text>
<text x="125.9" y="110.8">RD#</text>
<text x="125.9" y="111.7">WR# P36</text>
<text x="144.5" y="108.1">A13</text>
<text x="144.5" y="109">A14</text>
<text x="192.4" y="117.9">EN</text>
<text x="192.4" y="118.7">LED0 P32</text>
<text x="192.4" y="119.6">LED1 P33</text>
<text x="205.7" y="118.7">LED2</text>
<text x="205.7" y="115.2">LA</text>
<text x="205.7" y="116.1">LB</text>
<text x="205.7" y="117">LC</text>
<text x="205.7" y="117.9">LD</text>
<text x="205.7" y="119.6">LED3</text>
<text x="205.7" y="120.5">STB</text>
<text x="205.7" y="121.4">LEDC</text>
<text x="116.1" y="143.6">SCS# P14</text>
<text x="130.3" y="142.7">SCK P17</text>
<text x="39" y="144.4">T</text>
<text x="39" y="145.3">T1</text>
<text x="130.3" y="144.4">MISO P16</text>
<text x="130.3" y="145.3">MOSI P15</text>
<text x="53.2" y="168.3">DCD</text>
<text x="53.2" y="171.9">RI</text>
<text x="53.2" y="169.2">TXD1</text>
<text x="53.2" y="171">RTS</text>
<text x="67.4" y="169.2">DTR</text>
<text x="67.4" y="170.1">DSR</text>
<text x="67.4" y="171">CTS</text>
<text x="67.4" y="171.9">RXD1</text>
</g>
<text font-size=".7" fill="#0000bf" x="193.3" y="61.2">SD_IN</text>
<g font-size=".7" fill="#781915">
<text x="127.6" y="98.4">P40</text>
<text x="127.6" y="99.3">P41</text>
<text x="127.6" y="100.2">P42</text>
<text x="127.6" y="101">P43</text>
<text x="127.6" y="101.9">P44</text>
<text x="127.6" y="102.8">P45</text>
<text x="127.6" y="103.7">P35</text>
<text x="127.6" y="104.6">P27</text>
</g>
<g font-size=".7" fill="#800000">
<text x="142.7" y="98.4">P00</text>
<text x="142.7" y="99.3">P01</text>
<text x="142.7" y="100.2">P02</text>
<text x="142.7" y="101">P03</text>
<text x="142.7" y="101.9">P04</text>
<text x="127.6" y="105.5">P20</text>
<text x="127.6" y="106.3">P21</text>
<text x="127.6" y="107.2">P22</text>
<text x="142.7" y="102.8">P05</text>
<text x="142.7" y="103.7">P06</text>
<text x="142.7" y="104.6">P07</text>
<text x="127.6" y="110.8">P37</text>
<text x="127.6" y="108.1">P23</text>
<text x="127.6" y="109">P24</text>
<text x="142.7" y="108.1">P26</text>
<text x="142.7" y="109">P25</text>
</g>
<g font-size=".6" fill="#800000">
<text x="54.9" y="171.9">P06</text>
<text x="54.9" y="169.2">P27</text>
<text x="54.9" y="171">P01</text>
<text x="54.9" y="168.3">P07</text>
<text x="65.5" y="171.9">P26</text>
<text x="65.5" y="169.2">P00</text>
<text x="65.5" y="170.1">P05</text>
<text x="65.5" y="171">P04</text>
</g>
</g></defs>
<path d="M26.4 31.2h244.2v150.6h-244.2z" fill-rule="evenodd" fill="#ffffe8"/>
<g fill="none" stroke="#800000" stroke-width=".13">
<path d="M125 80h1.8M125.9 79.1v.9M125.3 80.2h1.2M125.5 80.5h.7M125.8 80.8h.2M132.1 172.9h1.8M132.3 173.2h1.3M132.6 173.5h.7M132.9 173.7h.2M133 172v.9M139.2 172.9h1.8M139.4 173.2h1.3"/>
<path d="M139.7 173.5h.7M140 173.7h.2M140.1 172v.9"/>
</g>
<g fill="none" stroke="#00f" stroke-width=".13">
<path d="M132.2 170.9h1.6M132.2 170.5h1.6M133 170.3v.2M133 170.9v.3M135.6 168.5h.2M135.8 168v1M136.2 167.7h.7v1.6h-.7zM137.2 168v1M137.2 168.5h.2M139.3 170.9h1.6M139.3 170.5h1.6M140.1 170.3v.2"/>
<path d="M140.1 170.9v.3"/>
</g>
<path d="M133 169.4v.9M133 171.2v.8M134.7 168.5h.9M137.4 168.5h.9M140.1 169.4v.9M140.1 171.2v.8" fill="none" stroke="#000" stroke-width=".13"/>
<path d="M41.6 97.7h4.4v6.1h-4.4z" fill-rule="evenodd" fill="#ffffb0" stroke="#800000" stroke-width=".13"/>
<path d="M43.4 95v2.7M46.1 99.4h2.6M43.4 103.9v2.6M46.1 102.1h2.6M46.1 100.3h2.6M46.1 101.2h2.6M50.5 108.3v1.8M50.5 112.7v1.8M54.9 102.1v.9M54.9 103.9v.9M56.7 101.2v.9M56.7 104.8v.8" fill="none" stroke="#000" stroke-width=".13"/>
<path d="M43.4 93.2v1.8M48.7 99.4h6.2v2.7M54.9 99.4h1.8v1.8M43.4 106.5v1.8M48.7 100.3h3.6M48.7 101.2h3.6M54.9 104.8v9.7M56.7 105.6v2.7h-1.8" fill="none" stroke="#000080" stroke-width=".13"/>
<path d="M54 98.6h1.8M54.3 98.3h1.3M54.6 98h.7M54.8 97.8h.2M54.9 98.6v.8M42.5 109.2h1.8M42.8 109.4h1.2M43 109.7h.8M43.3 110h.2M43.4 108.3v.9M56.3 109.2h.8M56.7 108.3v.9" fill="none" stroke="#781915" stroke-width=".13"/>
<path d="M50.1 110.1h.8v2.6h-.8zM50.5 110.1v2.6M54.1 103.6h1.6M54.1 103.2h1.6M54.9 103v.2M54.9 103.6v.3M55.8 103.9h1.8M56.7 102.1v1.4M56.7 103.9v.9M57.5 103.1a1.38 1.38 0 0 1-1.6 .1" fill="none" stroke="#00f" stroke-width=".13"/>
<path d="M68.2 97.7h4.4v6.1h-4.4z" fill-rule="evenodd" fill="#ffffb0" stroke="#800000" stroke-width=".13"/>
<path d="M70 95v2.7M72.7 99.4h2.6M70 103.9v2.6M72.7 102.1h2.6M72.7 100.3h2.6M72.7 101.2h2.6M75.3 109.2v1.8M75.3 113.6v1.8M81.5 102.1v.9M81.5 103.9v.9M83.3 101.2v.9M83.3 104.8v.8" fill="none" stroke="#000" stroke-width=".13"/>
<path d="M70 93.2v1.8M75.3 99.4h6.2v2.7M81.5 99.4h1.8v1.8M70 106.5v1.8M75.3 100.3h3.6M75.3 101.2h3.6M81.5 104.8v3.5h1.8v-2.7" fill="none" stroke="#000080" stroke-width=".13"/>
<path d="M80.6 98.6h1.8M80.9 98.3h1.3M81.2 98h.7M81.4 97.8h.2M81.5 98.6v.8M69.1 109.2h1.8M69.4 109.4h1.2M69.7 109.7h.7M69.9 110h.2M70 108.3v.9M82.9 109.2h.9M83.3 108.3v.9" fill="none" stroke="#781915" stroke-width=".13"/>
<path d="M75 111h.7v2.6h-.7zM75.3 111v2.6M80.7 103.6h1.6M80.7 103.2h1.6M81.5 103v.2M81.5 103.6v.3M82.4 103.9h1.8M83.3 102.1v1.4M83.3 103.9v.9M84.1 103.1a1.38 1.38 0 0 1-1.6 .1" fill="none" stroke="#00f" stroke-width=".13"/>
<path d="M58.5 167.6h4.3v5.2h-4.3z" fill-rule="evenodd" fill="#ffffb0" stroke="#800000" stroke-width=".13"/>
<g fill="none" stroke="#000" stroke-width=".13">
<path d="M56.7 168.5h1.2M56.7 169.4h1.2M56.7 170.3h1.2M56.7 171.2h1.2M56.7 172h1.2M63.4 168.5h1.3M63.4 169.4h1.3M63.4 170.3h1.3M63.4 171.2h1.3M63.4 172h1.3"/>
<circle cx="58.2" cy="172" r=".22"/>
<circle cx="58.2" cy="170.2" r=".22"/>
<circle cx="58.2" cy="168.5" r=".22"/>
<circle cx="58.2" cy="169.3" r=".22"/>
<circle cx="58.2" cy="171.1" r=".22"/>
<circle cx="63.1" cy="170.2" r=".22"/>
<circle cx="63.1" cy="172" r=".22"/>
<circle cx="63.1" cy="171.1" r=".22"/>
<circle cx="63.1" cy="169.3" r=".22"/>
<circle cx="63.1" cy="168.5" r=".22"/>
</g>
<path d="M36.3 142.8h2.7M37.2 143.7h1.8M37.2 144.6h1.8M53.2 168.5h3.5M53.2 169.4h3.5M53.2 171.2h3.5M53.2 172h3.5M64.7 168.5h1.7M64.7 169.4h3.5M64.7 171.2h3.5M64.7 172h3.5M64.7 170.3h3.5" fill="none" stroke="#000080" stroke-width=".13"/>
<path d="M40.7 141.9h1.7v6.2h-1.7z" fill-rule="evenodd" fill="#ffffb0" stroke="#800000" stroke-width=".13"/>
<path d="M39 147.3h1.7M39 146.4h1.7M39 145.5h1.7M39 144.6h1.7M39 143.7h1.7M39 142.8h1.7" fill="none" stroke="#000" stroke-width=".13"/>
<path d="M37.2 145.5h1.8" fill="none" stroke="#000080" stroke-width=".13"/>
<g fill="#800000" stroke="#800000" stroke-width=".13">
<circle cx="77.9" cy="99.4" r=".13"/>
<circle cx="52.2" cy="99.4" r=".13"/>
</g>
<path d="M50.6 170.2v.2M50.9 169.9v.7M51.1 169.7v1.2M51.4 169.4v1.8M51.4 170.3h.9" fill="none" stroke="#800000" stroke-width=".13"/>
<path d="M136.5 141.1h7v6.1h-7z" fill-rule="evenodd" fill="#ffffb0" stroke="#800000" stroke-width=".13"/>
<g fill="none" stroke="#000" stroke-width=".13">
<path d="M70.9 62.3v1.7M70.9 65.8v1.8M120.6 143.7h1.7M125 143.7h1.8M127.6 140.2v.9M127.6 142.8v.9M133.9 142.8h2.6M133.9 143.7h2.6M133.9 144.6h2.6M133.9 145.5h2.6M143.6 142.8h2.7M143.6 143.7h2.7"/>
<path d="M143.6 144.6h2.7M143.6 145.5h2.7"/>
</g>
<path d="M52.7 60.5h.9M53.2 60.5v.9M127.2 139.3h.9M127.6 139.3v.9M146.3 146.4h1.7M146.5 146.6h1.3M146.8 146.9h.7M147.1 147.2h.1M147.2 145.5v.9" fill="none" stroke="#800000" stroke-width=".13"/>
<path d="M130.3 145.5h3.6M130.3 142.8h3.6M130.3 144.6h3.6M132.1 143.7h1.8M146.3 145.5h.9M146.3 143.7h.9v.9h-.9" fill="none" stroke="#000080" stroke-width=".13"/>
<path d="M146.7 141.9h.9M147.2 141.9v.9" fill="none" stroke="#781915" stroke-width=".13"/>
<path d="M70.1 64.6h1.6v.3h-1.6zM70.1 65.3h1.6M70.9 64v.6M70.9 65.3v.5M71.2 64.2h.3M71.3 64v.4M122.3 143.4h2.7v.6h-2.7zM127.4 141.1h.5v1.7h-.5z" fill="none" stroke="#00f" stroke-width=".13"/>
<path d="M57.6 60.5h7v4.3h-7z" fill-rule="evenodd" fill="#ffffb0" stroke="#800000" stroke-width=".13"/>
<g fill="none" stroke="#000" stroke-width=".13">
<path d="M44.8 48.1h1.3M44.8 49h1.3M44.8 49.9h1.3M54.9 61.4h2.7M61.1 64.9v2.7M64.7 61.4h2.6"/>
<circle cx="44.5" cy="48.9" r=".22"/>
<circle cx="44.5" cy="49.8" r=".22"/>
<circle cx="44.5" cy="48" r=".22"/>
</g>
<path d="M70 61.4h-2.7v1.7" fill="none" stroke="#000080" stroke-width=".13"/>
<path d="M43.2 49.5h.7l-.3 .4zM44.3 49h-.7v.5" fill="none" stroke="#00f" stroke-width=".13"/>
<path d="M41.5 48.3h2.1v.1h-2.1z" fill-rule="evenodd" fill="#11037f" stroke="#800000" stroke-width=".13"/>
<path d="M41.3 47.1l.2-.1a.95 .95 0 0 1 .6 1 2.05 2.05 0 0 1-.4 1.7l-.2 .1a.95 .95 0 0 1-.6-1 2.05 2.05 0 0 1 .4-1.7zM41.6 49.9l.5-.5 .4 .5h1.8M44.3 48.1h-.5l-.1 .2M52.4 62.9h1.6M52.4 62.5h1.6M53.2 62.3v.2M53.2 62.9v.2M66.5 64.6h1.6M66.5 64.3h1.6M67.3 64v.3M67.3 64.6v.3" fill="none" stroke="#00f" stroke-width=".13"/>
<path d="M53.2 61.4h1.7M53.2 64v.9M61.1 67.6h8.9M67.3 65.8v1.8M70.9 61.4v.9" fill="none" stroke="#000080" stroke-width=".13"/>
<path d="M53.2 61.4v.9M53.2 63.1v.9M67.3 63.1v.9M67.3 64.9v.9" fill="none" stroke="#000" stroke-width=".13"/>
<path d="M52.3 65.8h1.7M52.5 66.1h1.3M52.8 66.3h.7M53.1 66.6h.1M53.2 64.9v.9" fill="none" stroke="#781915" stroke-width=".13"/>
<circle cx="70.9" cy="61.3" r=".13" fill="#800000" stroke="#800000" stroke-width=".13"/>
<path d="M58.5 44.5h7v7.9h-7z" fill-rule="evenodd" fill="#ffffb0" stroke="#800000" stroke-width=".13"/>
<g fill="none" stroke="#000" stroke-width=".13">
<path d="M48.7 49.9v.8M48.7 53.4v.9M52.3 50.7v.9M52.3 52.5v.9M55.8 46.3h2.7M60.3 52.5v2.7M63.8 52.5v2.7M65.6 46.3h2.6M65.6 49h2.6M70 49v1.7M70 53.4v1.8M73.6 49h1.7"/>
<path d="M78.9 49h1.7M81.5 50.7v.9M81.5 52.5v.9M84.2 50.7v.9M84.2 54.3v.9M245.6 44.5h.9M249.1 44.5h.9M241.2 99.4h1.7M245.6 99.4h3.5M251.8 99.4h1.8M241.2 117.1h1.7M241.2 112.7h1.7"/>
<path d="M241.2 108.3h1.7M241.2 103.9h1.7M245.6 117.1h3.5M245.6 112.7h3.5M245.6 108.3h3.5M245.6 103.9h3.5M251.8 117.1h1.8M251.8 112.7h1.8M251.8 108.3h1.8M251.8 103.9h1.8"/>
</g>
<g fill="none" stroke="#000080" stroke-width=".13">
<path d="M46.1 49v6.2h2.6M48.7 45.4v4.5M48.7 54.3v.9M48.7 55.2h35.5M52.3 46.3v4.4M52.3 53.4v1.8M55.8 46.3h-9.7v1.8M68.2 46.3h13.3v2.7h-.9M68.2 49h5.4M81.5 53.4v1.8M109 56.1h1.8M109 56.9h1.8"/>
<path d="M109 57.8h1.8M109 58.7h1.8M121.4 42.8v2.6M122.3 42.8v2.6M123.2 42.8v2.6M124.1 42.8v2.6M125 42.8v2.6M125.9 42.8v2.6M126.8 40.1v5.3M128.5 42.8v2.6M129.4 42.8v2.6M130.3 42.8v2.6"/>
<path d="M131.2 42.8v2.6M141.8 56.1h2.7M141.8 56.9h2.7M141.8 57.8h2.7M141.8 58.7h2.7M141.8 59.6h2.7M245.6 44.5h-.9v3.6M250 44.5v.9M109 60.5h1.8M109 61.4h1.8M109 62.3h1.8M109 63.1h1.8"/>
<path d="M109 64h1.8M109 64.9h1.8M109 65.8h1.8M121.4 76.4v1.8M122.3 76.4v1.8M123.2 76.4v1.8M124.1 76.4v1.8M125 76.4v1.8M125.9 76.4v2.7M126.8 76.4v1.8M127.6 76.4v1.8M128.5 76.4v1.8"/>
<path d="M129.4 76.4v1.8M130.3 76.4v1.8M131.2 76.4v1.8M141.8 60.5h2.7M141.8 61.4h2.7M141.8 62.3h2.7M141.8 63.1h2.7M141.8 64h2.7M141.8 65.8h2.7M127.6 98.6h1.8M127.6 99.4h1.8M141.8 98.6h1.8"/>
<path d="M141.8 99.4h1.8M187.1 95.9h5.3M187.1 96.8h5.3M187.1 97.7h5.3M200.4 96.8h3.5M127.6 100.3h1.8M127.6 101.2h1.8M127.6 102.1h1.8M127.6 103h1.8M127.6 103.9h1.8M127.6 104.8h1.8M127.6 105.6h1.8"/>
<path d="M127.6 106.5h1.8M127.6 107.4h1.8M127.6 108.3h1.8M127.6 109.2h1.8M127.6 111h1.8M127.6 111.8h1.8M127.6 113.6h1.8M141.8 100.3h1.8M141.8 101.2h1.8M141.8 102.1h1.8M141.8 103h1.8M141.8 103.9h1.8"/>
<path d="M141.8 104.8h1.8M141.8 108.3h1.8M141.8 109.2h1.8M192.4 118.9h3.5M203.9 119.8h3.6M203.9 118.9h3.6M253.6 103.9h.9M253.6 108.3h.9M253.6 112.7h.9M253.6 117.1h.9M203.9 120.7h3.6M36.3 146.4h2.7"/>
<path d="M116.1 143.7h4.5M126.8 143.7h.8M178.2 143.7h.9M178.2 141.9h.9M178.2 142.8h.9M178.2 144.6h.9M178.2 145.5h.9M178.2 146.4h.9M178.2 147.3h.9M178.2 148.1h.9M187.1 143.7h.9M187.1 141.9h.9"/>
<path d="M187.1 142.8h.9M187.1 144.6h.9M187.1 145.5h.9M187.1 146.4h.9M187.1 147.3h.9M187.1 148.1h.9M187.1 149h.9M187.1 141.1h.9M195 143.7h.9M195 141.9h.9M195 142.8h.9M195 144.6h.9"/>
<path d="M195 145.5h.9M195 146.4h.9M195 147.3h.9M195 148.1h.9M203.9 143.7h.9M203.9 141.9h.9M203.9 142.8h.9M203.9 144.6h.9M203.9 145.5h.9M203.9 146.4h.9M203.9 147.3h.9M203.9 148.1h.9"/>
<path d="M203.9 149h.9M203.9 141.1h.9M211.9 144.6h.9M211.9 145.5h.9M211.9 146.4h.9M211.9 147.3h.9M211.9 148.1h.9M220.8 143.7h.8M220.8 141.9h.8M220.8 142.8h.8M220.8 144.6h.8M220.8 145.5h.8"/>
<path d="M220.8 146.4h.8M220.8 147.3h.8M133 166.7v1.8M134.7 168.5h-1.7v.9M138.3 168.5h1.8v.9M140.1 166.7v1.8"/>
</g>
<g fill="none" stroke="#00f" stroke-width=".13">
<path d="M47.8 51.6h1.8M48.3 45.4h.9M48.7 45.4v.9M48.7 50.7v.9M48.7 52v1.4M48.7 52h.3l.6 .3M48.7 52h-.3l-.6 .3M51.5 52.2h1.6M51.5 51.9h1.6M52.3 51.6v.3M52.3 52.2v.3M70 50.7v.9"/>
<path d="M70 52.5v.9M70.7 51.4h.2v.2h-1.8v.2h.2M76.1 49a.4 .4 0 0 0-.4-.5 .4 .4 0 0 0-.4 .5M77 49a.4 .4 0 0 0-.4-.5 .4 .4 0 0 0-.4 .5M77.9 49a.4 .4 0 0 0-.4-.5 .4 .4 0 0 0-.4 .5M78.8 49a.4 .4 0 0 0-.4-.5 .4 .4 0 0 0-.4 .5M80.7 52.2h1.6M80.7 51.9h1.6M81.5 51.6v.3M81.5 52.2v.3M83.3 52.5h1.8M84.2 51.6v.9"/>
<path d="M84.2 52.9v1.4M84.2 52.9l.6 .1 .2 .2M84.2 52.9h-.3l-.6 .2M246.5 43.9h2.6v.1h-2.6zM246.7 44.3h.1l.2 .2v.1l-.2 .2h-.1l-.2-.2v-.1zM247.5 44v-.3h.7v.3M247.5 43.8h.7M247.5 43.7h.7M247.5 43.7v.3M247.6 43.7v.3M247.7 43.7v.3M247.8 43.7v.3"/>
<path d="M247.9 43.7v.3M248 43.7v.3M248.1 43.7v.3M248.8 44.3h.2l.1 .2v.1l-.1 .2h-.2l-.2-.2v-.1zM242.9 99.2h2.7v.5h-2.7zM249.1 99.4h2.7M250.4 98l-.4 .4M251.1 98l-.4 .4M242.9 103.6h2.7v.5h-2.7zM242.9 108h2.7v.6h-2.7zM242.9 112.5h2.7v.5h-2.7zM242.9 116.9h2.7v.5h-2.7z"/>
<path d="M249.1 117.1h2.7M249.1 112.7h2.7M249.1 108.3h2.7M249.1 103.9h2.7M250.4 115.7l-.4 .4M250.4 111.3l-.4 .4M250.4 106.9l-.4 .3M250.4 102.4l-.4 .4M251.1 115.7l-.4 .4M251.1 111.3l-.4 .4M251.1 106.9l-.4 .3M251.1 102.4l-.4 .4"/>
</g>
<g fill="#00f" stroke="#00f" stroke-width=".13">
<path d="M69.1 52.5l.9-.9 .9 .9z"/>
<path d="M249.8 116.4l.9 .7-.9 .8z"/>
<path d="M251 115.6h.3v.2z"/>
<path d="M250.3 115.6h.3v.2z"/>
<path d="M249.8 111.9l.9 .8-.9 .8z"/>
<path d="M251 111.1h.3v.3z"/>
<path d="M250.3 111.1h.3v.3z"/>
<path d="M249.8 107.5l.9 .8-.9 .8z"/>
<path d="M251 106.7h.3v.3z"/>
<path d="M250.3 106.7h.3v.3z"/>
<path d="M249.8 103.1l.9 .8-.9 .8z"/>
<path d="M251 102.3h.3v.2z"/>
<path d="M250.3 102.3h.3v.2z"/>
<path d="M249.8 98.6l.9 .8-.9 .8z"/>
<path d="M251 97.8h.3v.3z"/>
<path d="M250.3 97.8h.3v.3z"/>
<path d="M250.7 116.4v1.5z" fill-rule="evenodd"/>
<path d="M250.7 111.9v1.6z" fill-rule="evenodd"/>
<path d="M250.7 107.5v1.6z" fill-rule="evenodd"/>
<path d="M250.7 103.1v1.6z" fill-rule="evenodd"/>
<path d="M250.7 98.6v1.6z" fill-rule="evenodd"/>
</g>
<g fill="none" stroke="#800000" stroke-width=".13">
<path d="M51.4 56.1h1.8M51.6 56.3h1.3M51.9 56.6h.7M52.2 56.8h.2M52.3 55.2v.9M80.6 56.1h1.8M80.9 56.3h1.3M81.2 56.6h.7M81.4 56.8h.2M81.5 55.2v.9M83.8 48.1h.8M84.2 48.1v.9"/>
<path d="M243.8 48.1h.9M243.8 47.6v.9M253.6 99.4h.9M254.5 98.6v1.7M254.7 98.8v1.3M255 99.1v.7M255.3 99.4v.1M178.5 139.9h1.2M178.7 139.6h.7M179 139.4h.2M195.3 139.9h1.3M195.6 139.6h.7"/>
<path d="M195.8 139.4h.2M212.2 139.9h1.2M212.4 139.6h.7M212.7 139.4h.2M34.6 142.7v.2M34.9 142.5v.7M35.2 142.2v1.2M35.4 141.9v1.8M35.4 142.8h.9M178.2 140.2h1.8M178.2 149.9h1.8M178.5 150.2h1.2"/>
<path d="M178.7 150.4h.7M179 150.7h.2M179.1 140.2v.9M179.1 149v.9M187.5 140.2h.9M187.5 149.9h.9M188 140.2v.9M188 149v.9M195 140.2h1.8M195 149.9h1.8M195.3 150.2h1.3M195.6 150.4h.7"/>
<path d="M195.8 150.7h.2M195.9 140.2v.9M195.9 149v.9M204.4 140.2h.8M204.4 149.9h.8M204.8 140.2v.9M204.8 149v.9M211.9 140.2h1.8M212.8 140.2v.9M221.2 140.2h.9M221.6 140.2v.9"/>
</g>
<path d="M240.3 99v.9M240.3 99.4h.9M240.3 103.4v.9M240.3 107.9v.8M240.3 112.3v.9M240.3 116.7v.9M240.3 117.1h.9M240.3 112.7h.9M240.3 108.3h.9M240.3 103.9h.9" fill="none" stroke="#781915" stroke-width=".13"/>
<path d="M173.8 33.9v50.5h-76.3" fill="none" stroke="#00f" stroke-width=".44"/>
<path d="M194.2 94.1h4.3v4.4h-4.3z" fill-rule="evenodd" fill="#ffffb0" stroke="#800000" stroke-width=".13"/>
<g fill="none" stroke="#000" stroke-width=".13">
<path d="M126.8 37.5v.8M126.8 39.2v.9M192.4 95h1.2M192.4 95.9h1.2M192.4 96.8h1.2M192.4 97.7h1.2M199.1 95h1.3M199.1 95.9h3M199.1 96.8h1.3M199.1 97.7h1.3M203.9 93.2h1.8M204.8 95.9h1.8"/>
<path d="M208.3 93.2h1.8"/>
<circle cx="193.9" cy="95" r=".22"/>
<circle cx="193.9" cy="95.9" r=".22"/>
<circle cx="193.9" cy="97.6" r=".22"/>
<circle cx="193.9" cy="96.7" r=".22"/>
<circle cx="198.8" cy="95.9" r=".22"/>
<circle cx="198.8" cy="95" r=".22"/>
<circle cx="198.8" cy="96.7" r=".22"/>
<circle cx="198.8" cy="97.6" r=".22"/>
</g>
<g fill="none" stroke="#000080" stroke-width=".13">
<path d="M127.6 42.8v2.6M247.4 48.1h1.7M250 44.5h4.5M250 45.4v2.7M187.1 95h5.3M200.4 97.7h1.7M203.9 93.2v1.8h-3.5M210.1 93.2h.9v2.7h-4.4M194.2 115.4h1.7M203.9 121.6h3.6M220.8 148.1h.8M220.8 149h.8"/>
<path d="M220.8 141.1h.8"/>
</g>
<path d="M203.5 92.4h.9M203.9 92.4v.8" fill="none" stroke="#781915" stroke-width=".13"/>
<path d="M126 38.6h1.6M126 39h1.6M126.8 38.3v.3M126.8 39v.2M202.1 95.6h2.7v.6h-2.7zM205.7 93.2h2.6" fill="none" stroke="#00f" stroke-width=".13"/>
<g fill="none" stroke="#800000" stroke-width=".13">
<path d="M125.9 36.6h1.7M126.1 36.3h1.3M126.4 36h.7M126.7 35.8h.2M126.8 36.6v.9M203 97.7h1.8M203.3 97.9h1.2M203.6 98.2h.7M203.8 98.5h.2M203.9 96.8v.9M210.6 92.4h.9M211 92.4v.8"/>
<path d="M192.5 115.3v.2M192.7 115v.7M193 114.8v1.2M193.3 114.5v1.8M193.3 115.4h.9M211.9 149.9h1.8M212.2 150.2h1.2M212.4 150.4h.7M212.7 150.7h.2M212.8 149v.9M221.2 149.9h.9M221.6 149v.9"/>
</g>
<g fill="#00f" stroke="#00f" stroke-width=".13">
<path d="M206.6 92.4l.9 .8-.9 .9z"/>
<path d="M207.5 92.4v1.7z" fill-rule="evenodd"/>
</g>
<path d="M97.5 127.8v52.2M30.1 160.5h67.4" fill="none" stroke="#00f" stroke-width=".44"/>
<path d="M132.1 97.7h7v16.7h-7z" fill-rule="evenodd" fill="#ffffb0" stroke="#800000" stroke-width=".13"/>
<g fill="none" stroke="#000" stroke-width=".13">
<path d="M129.4 98.6h2.7M129.4 99.4h2.7M135.6 95v2.7M135.6 94.1h.9M137.4 94.1h.9M139.2 98.6h2.6M139.2 99.4h2.6M129.4 100.3h2.7M129.4 101.2h2.7M129.4 102.1h2.7M129.4 103h2.7M129.4 103.9h2.7"/>
<path d="M129.4 104.8h2.7M129.4 105.6h2.7M129.4 106.5h2.7M129.4 107.4h2.7M129.4 108.3h2.7M129.4 109.2h2.7M129.4 113.6h2.7M129.4 111.8h2.7M129.4 111h2.7M132.6 113.2h1.8M132.6 111.4h1.5M132.6 110.5h1.2"/>
<path d="M135.6 114.5v2.6M139.2 100.3h2.6M139.2 101.2h2.6M139.2 102.1h2.6M139.2 103h2.6M139.2 103.9h2.6M139.2 104.8h2.6M139.2 108.3h2.6M139.2 109.2h2.6"/>
</g>
<path d="M136.5 94.1h.3M136.8 93.3v1.6M137.1 94.1h.3M137.1 93.3v1.6" fill="none" stroke="#00f" stroke-width=".13"/>
<path d="M138.3 94.1h.9M139.2 93.2v1.8M139.4 93.5v1.2M139.7 93.8v.7M140 94v.2M135.6 117.1h.9M136.5 116.3v1.7M136.8 116.5v1.3M137 116.8v.7M137.3 117.1v.1" fill="none" stroke="#800000" stroke-width=".13"/>
<path d="M180.9 140.2h4.3v9.6h-4.3z" fill-rule="evenodd" fill="#ffffb0" stroke="#800000" stroke-width=".13"/>
<g fill="none" stroke="#000" stroke-width=".13">
<path d="M179.1 141.1h1.2M179.1 141.9h1.2M179.1 142.8h1.2M179.1 143.7h1.2M179.1 144.6h1.2M179.1 145.5h1.2M179.1 146.4h1.2M179.1 147.3h1.2M179.1 148.1h1.2M179.1 149h1.2M185.8 141.1h1.3M185.8 141.9h1.3"/>
<path d="M185.8 142.8h1.3M185.8 143.7h1.3M185.8 144.6h1.3M185.8 145.5h1.3M185.8 146.4h1.3M185.8 147.3h1.3M185.8 148.1h1.3M185.8 149h1.3"/>
<circle cx="180.5" cy="141.9" r=".22"/>
<circle cx="180.5" cy="142.8" r=".22"/>
<circle cx="180.5" cy="145.4" r=".22"/>
<circle cx="180.5" cy="146.3" r=".22"/>
<circle cx="180.5" cy="147.2" r=".22"/>
<circle cx="180.5" cy="149" r=".22"/>
<circle cx="180.5" cy="148.1" r=".22"/>
<circle cx="180.5" cy="143.7" r=".22"/>
<circle cx="180.5" cy="141" r=".22"/>
<circle cx="180.5" cy="144.6" r=".22"/>
<circle cx="185.5" cy="141" r=".22"/>
<circle cx="185.5" cy="142.8" r=".22"/>
<circle cx="185.5" cy="147.2" r=".22"/>
<circle cx="185.5" cy="146.3" r=".22"/>
<circle cx="185.5" cy="141.9" r=".22"/>
<circle cx="185.5" cy="143.7" r=".22"/>
<circle cx="185.5" cy="149" r=".22"/>
<circle cx="185.5" cy="144.6" r=".22"/>
<circle cx="185.5" cy="145.4" r=".22"/>
<circle cx="185.5" cy="148.1" r=".22"/>
</g>
<path d="M197.7 140.2h4.4v9.6h-4.4z" fill-rule="evenodd" fill="#ffffb0" stroke="#800000" stroke-width=".13"/>
<g fill="none" stroke="#000" stroke-width=".13">
<path d="M195.9 141.1h1.3M195.9 141.9h1.3M195.9 142.8h1.3M195.9 143.7h1.3M195.9 144.6h1.3M195.9 145.5h1.3M195.9 146.4h1.3M195.9 147.3h1.3M195.9 148.1h1.3M195.9 149h1.3M202.7 141.1h1.2M202.7 141.9h1.2"/>
<path d="M202.7 142.8h1.2M202.7 143.7h1.2M202.7 144.6h1.2M202.7 145.5h1.2M202.7 146.4h1.2M202.7 147.3h1.2M202.7 148.1h1.2M202.7 149h1.2"/>
<circle cx="197.4" cy="141.9" r=".22"/>
<circle cx="197.4" cy="143.7" r=".22"/>
<circle cx="197.4" cy="147.2" r=".22"/>
<circle cx="197.4" cy="149" r=".22"/>
<circle cx="197.4" cy="141" r=".22"/>
<circle cx="197.4" cy="142.8" r=".22"/>
<circle cx="197.4" cy="148.1" r=".22"/>
<circle cx="197.4" cy="144.6" r=".22"/>
<circle cx="197.4" cy="145.4" r=".22"/>
<circle cx="197.4" cy="146.3" r=".22"/>
<circle cx="202.4" cy="142.8" r=".22"/>
<circle cx="202.4" cy="146.3" r=".22"/>
<circle cx="202.4" cy="141" r=".22"/>
<circle cx="202.4" cy="144.6" r=".22"/>
<circle cx="202.4" cy="147.2" r=".22"/>
<circle cx="202.4" cy="148.1" r=".22"/>
<circle cx="202.4" cy="149" r=".22"/>
<circle cx="202.4" cy="143.7" r=".22"/>
<circle cx="202.4" cy="145.4" r=".22"/>
<circle cx="202.4" cy="141.9" r=".22"/>
</g>
<path d="M214.6 140.2h4.3v9.6h-4.3z" fill-rule="evenodd" fill="#ffffb0" stroke="#800000" stroke-width=".13"/>
<g fill="none" stroke="#000" stroke-width=".13">
<path d="M244.7 48.1h.9M246.5 48.1h.9M44.3 122.5h1.8M48.7 122.5h1.8M59.4 122.5h1.7M63.8 122.5h1.8M73.6 122.5h1.7M78 122.5h1.8M81.5 141.1h1.8M81.5 141.9h1.8M81.5 142.8h1.8M81.5 143.7h1.8"/>
<path d="M81.5 144.6h1.8M81.5 145.5h1.8M81.5 146.4h1.8M81.5 147.3h1.8M81.5 148.1h1.8M212.8 141.1h1.2M212.8 141.9h1.2M212.8 142.8h1.2M212.8 143.7h1.2M212.8 144.6h1.2M212.8 145.5h1.2M212.8 146.4h1.2"/>
<path d="M212.8 147.3h1.2M212.8 148.1h1.2M212.8 149h1.2M219.5 141.1h1.3M219.5 141.9h1.3M219.5 142.8h1.3M219.5 143.7h1.3M219.5 144.6h1.3M219.5 145.5h1.3M219.5 146.4h1.3M219.5 147.3h1.3M219.5 148.1h1.3"/>
<path d="M219.5 149h1.3"/>
<circle cx="214.2" cy="141" r=".22"/>
<circle cx="214.2" cy="142.8" r=".22"/>
<circle cx="214.2" cy="144.6" r=".22"/>
<circle cx="214.2" cy="147.2" r=".22"/>
<circle cx="214.2" cy="141.9" r=".22"/>
<circle cx="214.2" cy="149" r=".22"/>
<circle cx="214.2" cy="146.3" r=".22"/>
<circle cx="214.2" cy="148.1" r=".22"/>
<circle cx="214.2" cy="145.4" r=".22"/>
<circle cx="214.2" cy="143.7" r=".22"/>
<circle cx="219.2" cy="141" r=".22"/>
<circle cx="219.2" cy="142.8" r=".22"/>
<circle cx="219.2" cy="144.6" r=".22"/>
<circle cx="219.2" cy="141.9" r=".22"/>
<circle cx="219.2" cy="147.2" r=".22"/>
<circle cx="219.2" cy="149" r=".22"/>
<circle cx="219.2" cy="146.3" r=".22"/>
<circle cx="219.2" cy="148.1" r=".22"/>
<circle cx="219.2" cy="143.7" r=".22"/>
<circle cx="219.2" cy="145.4" r=".22"/>
</g>
<g fill="none" stroke="#00f" stroke-width=".13">
<path d="M245.6 48.1h.3M245.9 47.3v1.6M246.2 48.1h.3M246.2 47.3v1.6M46.1 122.2h2.6v.5h-2.6zM61.1 122.2h2.7v.5h-2.7zM75.3 122.2h2.7v.5h-2.7zM83.3 148.1h.5M83.3 147.3h1.6M83.3 146.4h.5M83.3 145.5h1.6M83.3 144.6h.5"/>
<path d="M83.3 143.7h1.6M83.3 142.8h.5M83.3 141.9h1.6M83.3 141.1h.5M84.1 148.9l-.2 .1h-.2M84.2 140.2l-.4-.1-.5 .3v8.4l.4 .2M84.2 140.2l1.8 1v6.8l-1.8 1"/>
<circle cx="84.1" cy="144.6" r=".22"/>
<circle cx="84.1" cy="146.3" r=".22"/>
<circle cx="84.1" cy="141" r=".22"/>
<circle cx="84.1" cy="142.8" r=".22"/>
<circle cx="84.1" cy="148.1" r=".22"/>
<circle cx="85.1" cy="141.9" r=".22"/>
<circle cx="85.1" cy="147.2" r=".22"/>
<circle cx="85.1" cy="143.7" r=".22"/>
<circle cx="85.1" cy="145.4" r=".22"/>
</g>
<g fill="none" stroke="#000080" stroke-width=".13">
<path d="M249.1 48.1h.9M254.5 44.5h2.6M53.2 76.4h1.7M53.2 75.5h1.7M53.2 74.6h1.7M70 61.4h.9M70 67.6h.9M43.4 93.2h8.9v6.2M70 93.2h8v6.2M133 94.1h2.6v.9M48.7 102.1h.9v.9M43.4 122.5h.9"/>
<path d="M50.5 122.5h.9M58.5 122.5h.9M65.6 122.5h.9M72.7 122.5h.9M79.8 122.5h.8M77.1 142.8h4.4M77.1 144.6h4.4M78.9 148.1h2.6M52.3 170.3h4.4"/>
</g>
<path d="M30.1 33.9h238.6v146.1h-238.6zM97.5 33.9v50.5h-67.4M97.5 127.8h76.3" fill="none" stroke="#00f" stroke-width=".44"/>
<g fill="none" stroke="#800000" stroke-width=".13">
<path d="M52.7 73.8h.9M52.7 77.3h.9M53.2 73.8v.8M53.2 76.4v.9M70.9 61.4h.9M71.8 60.9v.9M51.4 122.5h.9M52.3 122v.9M80.6 122.5h.9M81.5 121.6v1.7M81.8 121.8v1.3M82.1 122.1v.7"/>
<path d="M82.3 122.4v.1M78 149h1.8M78.3 149.3h1.2M78.5 149.6h.7M78.8 149.8h.2M78.9 148.1v.9"/>
</g>
<path d="M60.3 68.4h1.7M60.5 68.7h1.3M60.8 69h.7M61 69.2h.2M61.1 67.6v.8" fill="none" stroke="#781915" stroke-width=".13"/>
<path d="M54.9 141.9h9.7v6.2h-9.7z" fill-rule="evenodd" fill="#ffffb0" stroke="#800000" stroke-width=".13"/>
<g fill="none" stroke="#000" stroke-width=".13">
<path d="M55.8 139.3h.9M57.6 139.3h.9v2.6M59.4 136.6v.9M59.4 138.4v3.5M60.3 139.3v2.6M49.6 146.4v.9M49.6 148.1v.9M52.3 142.8h2.6M52.3 143.7h2.6M52.3 144.6h2.6M52.3 145.5h2.6M52.3 146.4h2.6"/>
<path d="M52.3 147.3h2.6M58.5 148.1v2.7M64.7 142.8h2.6M64.7 143.7h2.6M64.7 144.6h2.6M64.7 145.5h2.6M64.7 146.4h2.6M64.7 147.3h2.6M69.1 146.4v.9M69.1 148.1v.9"/>
</g>
<path d="M48.7 142.8h3.6M49.6 146.4h2.7M50.5 144.6h1.8M52.3 147.3v1.7h-2.7M67.3 147.3v1.7h1.8M67.3 144.6h2.7M67.3 142.8h2.7M67.3 146.4h1.8" fill="none" stroke="#000080" stroke-width=".13"/>
<g fill="none" stroke="#800000" stroke-width=".13">
<path d="M54.1 139.2v.2M54.4 138.9v.7M54.7 138.7v1.2M54.9 138.4v1.8M54.9 139.3h.9M61.6 138.4h.9M62 138.4v.9M38.5 148.1h.9M39 147.3v.8M57.6 151.7h1.8M57.9 151.9h1.2M58.1 152.2h.7"/>
<path d="M58.4 152.5h.2M58.5 150.8v.9"/>
</g>
<g fill="none" stroke="#00f" stroke-width=".13">
<path d="M56.7 139.3h.3M57 138.5v1.6M57.3 139.3h.3M57.3 138.5v1.6M58.6 137.8h1.6M58.6 138.1h1.6M59.4 137.5v.3M59.4 138.1v.3M48.8 147.9h1.6M48.8 147.5h1.6M49.6 147.3v.2M49.6 147.9v.2"/>
<path d="M68.3 147.9h1.6M68.3 147.5h1.6M69.1 147.3v.2M69.1 147.9v.2"/>
</g>
<path d="M56.7 73.8h4.3v3.4h-4.3z" fill-rule="evenodd" fill="#ffffb0" stroke="#800000" stroke-width=".13"/>
<g fill="none" stroke="#000" stroke-width=".13">
<path d="M54.9 76.4h1.3M54.9 75.5h1.3M54.9 74.6h1.3M61.7 76.4h1.2M61.7 75.5h1.2M61.7 74.6h1.2M196.8 172.9h.9M200.4 172.9h.9"/>
<circle cx="56.4" cy="75.5" r=".22"/>
<circle cx="56.4" cy="76.4" r=".22"/>
<circle cx="56.4" cy="74.6" r=".22"/>
<circle cx="61.4" cy="75.5" r=".22"/>
<circle cx="61.4" cy="76.4" r=".22"/>
<circle cx="61.4" cy="74.6" r=".22"/>
</g>
<path d="M62.9 75.5h1.8M62.9 76.4h1.8M62.9 74.6h1.8M75.3 102.1v1.8M81.5 108.3v3.5M146.3 142.8h.9v.9M195 172.9h1.8M201.3 172.9h3.5" fill="none" stroke="#000080" stroke-width=".13"/>
<path d="M69.1 75.5h9.8v1.8h-9.8zM69.1 76.4h9.8M71.8 75.5v1.8M75.3 75.5v1.8" fill="none" stroke="#0000b4" stroke-width=".13"/>
<g fill="none" stroke="#800000" stroke-width=".13">
<path d="M127.2 40.1h.9M127.6 40.1v.9M52.3 75.1v.9M52.3 75.5h.9M64.2 73.8h.9M64.7 73.8v.8M132.1 93.7v.9M132.1 94.1h.9M194.2 173.8h1.7M194.4 174.1h1.3M194.7 174.3h.7M195 174.6h.1"/>
<path d="M195 172.9v.9"/>
</g>
<path d="M197.7 172.3h2.7v.1h-2.7zM197.9 172.7h.2l.1 .1v.2l-.1 .2h-.2l-.2-.2v-.2zM198.7 172.4v-.4h.7v.4M198.7 172.2h.7M198.7 172.1h.7M198.8 172v.4M198.9 172v.4M199 172v.4M199.1 172v.4M199.2 172v.4M199.3 172v.4M200 172.7h.2l.2 .1v.2l-.2 .2h-.2l-.2-.2v-.2z" fill="none" stroke="#00f" stroke-width=".13"/>
<path d="M97.5 84.4v25.7M173.8 84.4v43.4" fill="none" stroke="#00f" stroke-width=".44"/>
<path d="M197.7 114.5h4.4v7.9h-4.4z" fill-rule="evenodd" fill="#ffffb0" stroke="#800000" stroke-width=".13"/>
<g fill="none" stroke="#000" stroke-width=".13">
<path d="M185.3 57.8v.9M188 57.8v.9M188 59.6v.9M185.3 60.5v.9M241.2 70.2h.8M241.2 73.8h.8M244.7 70.2h.9M244.7 73.8h.9M252.7 70.2h.9M252.7 73.8h.9M256.2 70.2h.9M256.2 73.8h.9"/>
<path d="M195.9 115.4h1.3M195.9 116.3h1.3M195.9 117.1h1.3M195.9 118h1.3M195.9 118.9h1.3M195.9 119.8h1.3M202.7 115.4h1.2M202.7 116.3h1.2M202.7 117.1h1.2M202.7 118h1.2M202.7 118.9h1.2M202.7 119.8h1.2"/>
<path d="M195.9 120.7h1.3M195.9 121.6h1.3M202.7 120.7h1.2M202.7 121.6h1.2"/>
<circle cx="197.4" cy="118.9" r=".22"/>
<circle cx="197.4" cy="118" r=".22"/>
<circle cx="197.4" cy="115.3" r=".22"/>
<circle cx="197.4" cy="116.2" r=".22"/>
<circle cx="197.4" cy="117.1" r=".22"/>
<circle cx="197.4" cy="119.8" r=".22"/>
<circle cx="202.4" cy="117.1" r=".22"/>
<circle cx="202.4" cy="118" r=".22"/>
<circle cx="202.4" cy="118.9" r=".22"/>
<circle cx="202.4" cy="115.3" r=".22"/>
<circle cx="202.4" cy="116.2" r=".22"/>
<circle cx="202.4" cy="119.8" r=".22"/>
<circle cx="197.4" cy="121.5" r=".22"/>
<circle cx="197.4" cy="120.6" r=".22"/>
<circle cx="202.4" cy="121.5" r=".22"/>
<circle cx="202.4" cy="120.6" r=".22"/>
</g>
<path d="M192.4 119.8h3.5M192.4 118h3.5M195.9 115.4v1.7M203.9 118h3.6M203.9 117.1h3.6M203.9 116.3h3.6M203.9 115.4h3.6M195.9 120.7v.9M127.6 143.7h4.5" fill="none" stroke="#000080" stroke-width=".13"/>
<path d="M184.4 56.5v.9M184.4 56.9h.9M184.4 63.1h1.8M184.7 63.4h1.2M184.9 63.7h.7M185.2 63.9h.2M185.3 62.3v.8M194.2 121.5v.2M194.5 121.2v.7M194.8 121v1.2M195 120.7v1.8M195 121.6h.9" fill="none" stroke="#800000" stroke-width=".13"/>
<path d="M173.8 105.6h52.3M173.8 160.5v19.5" fill="none" stroke="#00f" stroke-width=".44"/>
<g fill="none" stroke="#00f" stroke-width=".13">
<path d="M184.5 59.3h1.6v.3h-1.6zM184.5 59.9h1.6M185.3 58.7v.6M185.3 59.9v.6M185.6 58.9h.3M185.7 58.7v.4M187.2 59.3h1.5M187.2 59h1.5M188 58.7v.3M188 59.3v.3M242 69.6h2.7v.1h-2.7zM242 73.1h2.7v.1h-2.7z"/>
<path d="M242.2 70h.2l.2 .1v.2l-.2 .2h-.2l-.2-.2v-.2zM242.2 73.5h.2l.2 .2v.2l-.2 .1h-.2l-.2-.1v-.2zM243 69.7v-.4h.7v.4M243 73.2v-.3h.7v.3M243 69.5h.7M243 69.4h.7M243 73.1h.7M243 73h.7M243.1 69.3v.4M243.1 72.9v.3M243.2 69.3v.4M243.2 72.9v.3"/>
<path d="M243.3 69.3v.4M243.3 72.9v.3M243.4 69.3v.4M243.4 72.9v.3M243.5 69.3v.4M243.5 72.9v.3M243.6 69.3v.4M243.6 72.9v.3M244.4 70h.1l.2 .1v.2l-.2 .2h-.1l-.2-.2v-.2zM244.4 73.5h.1l.2 .2v.2l-.2 .1h-.1l-.2-.1v-.2zM253.6 70.1l.2-.1h.1l.2 .1v.2l-.2 .2h-.1l-.2-.2zM253.6 69.6h2.6v.1h-2.6z"/>
<path d="M253.6 73.1h2.6v.1h-2.6zM253.8 73.5h.1l.2 .2v.2l-.2 .1h-.1l-.2-.1v-.2zM254.6 69.5h.7M254.6 69.4h.7M254.6 69.7v-.4h.7v.4M254.6 73.2v-.3h.7v.3M254.6 73.1h.7M254.6 73h.7M254.6 69.3v.4M254.6 72.9v.3M254.7 69.3v.4M254.7 72.9v.3"/>
<path d="M254.8 69.3v.4M254.8 72.9v.3M254.9 69.3v.4M254.9 72.9v.3M255 69.3v.4M255 72.9v.3M255.1 69.3v.4M255.1 72.9v.3M255.2 69.3v.4M255.2 72.9v.3M255.7 70.1l.2-.1h.2l.1 .1v.2l-.1 .2h-.2l-.2-.2zM255.9 73.5h.2l.1 .2v.2l-.1 .1h-.2l-.2-.1v-.2z"/>
</g>
<path d="M202.1 52.5h6.2v11.4h-6.2z" fill-rule="evenodd" fill="#ffffb0" stroke="#800000" stroke-width=".13"/>
<g fill="none" stroke="#000" stroke-width=".13">
<path d="M188 55.2h1.7M192.4 55.2h1.8M195 51.6v.9M195 54.3v.9M198.6 48.1v1.8M198.6 52.5v1.8M199.5 54.3h2.6M199.5 55.2h2.6M199.5 56.1h2.6M199.5 56.9h2.6M199.5 57.8h2.6M199.5 58.7h2.6"/>
<path d="M199.5 59.6h2.6M192.4 60.5v1.8M192.4 64.9v1.8M199.5 60.5h2.6M199.5 61.4h2.6M199.5 62.3h2.6M48.7 107.1v1.2M49.6 103v1.2M50.5 107.1v1.2M119.7 113.6h1.7M124.1 113.6h1.8M127.6 113.6v.9"/>
<path d="M127.6 115.4v.9M237.6 159.6h.9M240.3 159.6h.9M240.3 153.5h.9M242 153.5h.9M133.9 166.7h1.7M138.3 166.7h1.8M236.7 160.5v.9M236.7 162.3v.9M242 160.5v.9M242 162.3v.9"/>
<circle cx="48.7" cy="106.7" r=".22"/>
<circle cx="49.6" cy="104.4" r=".22"/>
<circle cx="50.5" cy="106.7" r=".22"/>
</g>
<g fill="none" stroke="#000080" stroke-width=".13">
<path d="M109 59.6h1.8M183.5 55.2h4.5M185.3 57.8v-.9h2.7v.9M188 56.9h11.5M192.4 58.7h7.1M193.3 56.1h6.2M193.3 57.8h6.2M193.3 59.6h6.2M194.2 55.2h5.3M198.6 54.3h.9M141.8 64.9h2.7M188 60.5v1.8h-2.7v-.9"/>
<path d="M192.4 60.5h7.1M195 61.4h4.5M198.6 62.3h.9M239.4 70.2h1.8M239.4 73.8h1.8M250.9 70.2h1.8M250.9 73.8h1.8M125.9 98.6h1.7M125.9 99.4h1.7M143.6 98.6h1.8M143.6 99.4h1.8M50.5 114.5h4.4"/>
<path d="M75.3 103.9v5.3M81.5 111.8v3.6h-6.2M125.9 100.3h1.7M125.9 101.2h1.7M125.9 102.1h1.7M125.9 103h1.7M125.9 103.9h1.7M125.9 104.8h1.7M125.9 108.3h1.7M125.9 109.2h1.7M125.9 113.6h1.7M125.9 111.8h1.7"/>
<path d="M125.9 111h1.7M125.9 107.4h1.7M125.9 106.5h1.7M125.9 105.6h1.7M143.6 100.3h1.8M143.6 101.2h1.8M143.6 102.1h1.8M143.6 103h1.8M143.6 103.9h1.8M143.6 104.8h1.8M143.6 108.3h1.8M143.6 109.2h1.8"/>
<path d="M36.3 142.8v3.6M237.6 159.6h-.9v.9M239.4 153.5h.9M241.2 159.6h.8M244.7 151.7v1.8h-1.8M244.7 157h-2.7v3.5M244.7 156.1h-8v3.5M244.7 153.5v1.7M133 165v1.7h.9M140.1 165v1.7M236.7 163.2h5.3"/>
</g>
<g fill="none" stroke="#800000" stroke-width=".13">
<path d="M190.7 58.6v.2M191 58.4v.7M191.2 58.1v1.2M191.5 57.8v1.8M191.5 58.7h.9M194.6 50.7h.9M195 50.7v.9M198.1 47.2h.9M198.6 47.2v.9M191.9 67.6h.9M192.4 66.7v.9M197.7 63.1h1.8"/>
<path d="M198 63.4h1.2M198.2 63.7h.7M198.5 63.9h.2M198.6 62.3v.8M244.7 71.1h1.8M244.7 74.6h1.8M245 71.4h1.2M245 74.9h1.2M245.2 71.6h.7M245.2 75.2h.7M245.5 71.9h.2M245.5 75.4h.2"/>
<path d="M245.6 70.2v.9M245.6 73.8v.8M256.2 71.1h1.8M256.2 74.6h1.8M256.5 71.4h1.2M256.5 74.9h1.2M256.8 71.6h.7M256.8 75.2h.7M257 71.9h.2M257 75.4h.2M257.1 70.2v.9M257.1 73.8v.8"/>
<path d="M119.2 112.7h.9M119.7 112.7v.9M126.8 117.1h1.7M127 117.4h1.3M127.3 117.7h.7M127.6 117.9h.1M127.6 116.3v.8M58.5 135.7h1.8M58.7 135.5h1.3M59 135.2h.7M59.3 134.9h.2M59.4 135.7v.9"/>
<path d="M65.5 167.6h1.8M65.7 167.4h1.3M66 167.1h.7M66.3 166.8h.2M66.4 167.6v.9M238.5 164.1h1.8M238.8 164.3h1.2M239 164.6h.7M239.3 164.9h.2M239.4 163.2v.9"/>
</g>
<path d="M226.1 33.9v50.5h-52.3M226.1 58.7h42.6M268.7 84.4h-42.6v43.4h-52.3v32.7h-76.3M97.5 105.6v22.2h-67.4M268.7 127.8h-42.6v32.7h-52.3M226.1 160.5v19.5" fill="none" stroke="#00f" stroke-width=".44"/>
<g fill="#800000" stroke="#800000" stroke-width=".13">
<circle cx="53.1" cy="61.3" r=".13"/>
<circle cx="61.1" cy="67.5" r=".13"/>
<circle cx="46" cy="49.8" r=".13"/>
<circle cx="60.2" cy="55.1" r=".13"/>
<circle cx="63.8" cy="55.1" r=".13"/>
<circle cx="70" cy="55.1" r=".13"/>
<circle cx="70" cy="48.9" r=".13"/>
<circle cx="56.7" cy="108.3" r=".13"/>
<circle cx="54.9" cy="99.4" r=".13"/>
<circle cx="83.3" cy="108.3" r=".13"/>
<circle cx="81.5" cy="99.4" r=".13"/>
<circle cx="81.5" cy="108.3" r=".13"/>
<circle cx="36.3" cy="142.8" r=".13"/>
<circle cx="135.6" cy="94.1" r=".13"/>
<circle cx="195.9" cy="116.2" r=".13"/>
<circle cx="195.9" cy="115.3" r=".13"/>
<circle cx="195.9" cy="121.5" r=".13"/>
<circle cx="185.2" cy="62.2" r=".13"/>
<circle cx="187.9" cy="56.9" r=".13"/>
<circle cx="140" cy="168.5" r=".13"/>
<circle cx="132.9" cy="168.5" r=".13"/>
<circle cx="250" cy="44.5" r=".13"/>
<circle cx="147.1" cy="143.7" r=".13"/>
<circle cx="127.6" cy="143.7" r=".13"/>
<circle cx="195" cy="55.1" r=".13"/>
<circle cx="185.2" cy="56.9" r=".13"/>
<circle cx="140" cy="166.7" r=".13"/>
<circle cx="132.9" cy="166.7" r=".13"/>
<circle cx="127.6" cy="113.6" r=".13"/>
<circle cx="203.9" cy="93.2" r=".13"/>
<circle cx="211" cy="93.2" r=".13"/>
<circle cx="54.9" cy="108.3" r=".13"/>
</g>
<g fill="none" stroke="#00f" stroke-width=".13">
<path d="M189.7 54.9h2.7v.5h-2.7zM194.8 52.5h.5v1.8h-.5zM198.3 49.9h.6v2.6h-.6zM192.1 62.3h.6v2.6h-.6zM49.6 104.8l.9 1.7M121.4 113.3h2.7v.6h-2.7zM126.9 114.8h.2v-.1h-.2v.5h.2v-.1h-.2M126.9 114.7v.5M127.6 114.5v.3h-.2v-.1h.2M127.6 115.2h-.2v-.1h.2v.3M238.5 159.6h.2M238.7 159.1v1.1"/>
<path d="M239 158.9h.7v1.5h-.7zM240.1 159.1v1.1M240.1 159.6h.2M241.2 153.5h.2M241.4 152.7v1.5M241.8 153.5h.2M241.8 152.7v1.5M135.6 166.5h2.7v.5h-2.7zM235.9 162h1.6M235.9 161.7h1.6M236.7 161.4v.3M236.7 162v.3"/>
<path d="M241.2 162h1.6M241.2 161.7h1.6M242 161.4v.3M242 162v.3"/>
</g>
<path d="M247.4 154.3h5.2v4.4h-5.2z" fill-rule="evenodd" fill="#ffffb0" stroke="#800000" stroke-width=".13"/>
<g fill="none" stroke="#000" stroke-width=".13">
<path d="M120.6 40.1h1.7M125 40.1h1.8M127.6 41h.9M129.4 41h.9M62 139.3h.9M63.8 139.3h.9M244.7 155.2h2.7M244.7 156.1h2.7M244.7 157h2.7M244.7 157.9h2.7M250 146.4h1.8M252.7 155.2h2.6"/>
<path d="M252.7 156.1h2.6M252.7 157h2.6M252.7 157.9h2.6M255.3 146.4h1.8M258 149.9v.9M258 151.7v.9"/>
</g>
<g fill="none" stroke="#00f" stroke-width=".13">
<path d="M122.3 39.8h2.7v.6h-2.7zM128.5 41h.3M128.8 40.2v1.6M129.2 41h.2M129.2 40.2v1.6M62.9 139.3h.3M63.2 138.5v1.6M63.5 139.3h.3M63.5 138.5v1.6M251.8 146.4h.8M252.6 146h.4v.7h-.4zM254.2 146h.4v.7h-.4z"/>
<path d="M254.6 146.4h.7M257.2 151.1h1.6M257.2 151.4h1.6M258 150.8v.3M258 151.4v.3"/>
<circle cx="253.5" cy="146.3" r="1.73"/>
</g>
<path d="M81.5 50.7v-1.7h2.7v1.7M127.6 41v1.8M193.3 61.4h1.7M60.3 139.3h1.7M244.7 157.9v.9M255.3 156.1h5.4M255.3 157h5.4M255.3 157.9h5.4M257.1 146.4h.9v3.5h-2.7v5.3" fill="none" stroke="#000080" stroke-width=".13"/>
<g fill="none" stroke="#800000" stroke-width=".13">
<path d="M119.1 39.8v.7M119.4 39.5v1.2M119.7 39.2v1.8M118.9 40v.2M119.7 40.1h.9M130.3 41h.9M131.2 40.1v1.8M131.5 40.4v1.2M131.7 40.6v.8M132 40.9v.2M64.7 139.3h.9M65.6 138.4v1.8"/>
<path d="M65.8 138.7v1.2M66.1 138.9v.7M66.4 139.2v.2M211.9 141.5v.9M211.9 141.9h.9M237.7 153.4v.1M238 153.1v.7M238.2 152.8v1.3M238.5 152.6v1.7M238.5 153.5h.9M243.8 159.6h1.8M244.1 159.9h1.2"/>
<path d="M244.3 150.8h.9M244.7 150.8v.9M244.7 158.8v.8M248.3 146.3v.2M248.6 146v.7M248.9 145.7v1.3M249.1 145.5v1.8M249.1 146.4h.9M257.1 153.5h1.8M257.4 153.7h1.2M257.7 154h.7M257.9 154.2h.2"/>
<path d="M258 152.6v.9M244.4 160.2h.7M244.6 160.4h.2"/>
</g>
<g fill="#800000" stroke="#800000" stroke-width=".13">
<circle cx="239.3" cy="163.1" r=".13"/>
<circle cx="242" cy="159.6" r=".13"/>
<circle cx="236.7" cy="159.6" r=".13"/>
<circle cx="244.7" cy="153.4" r=".13"/>
<circle cx="258" cy="149.9" r=".13"/>
<circle cx="244.7" cy="48" r=".13"/>
<circle cx="67.3" cy="61.3" r=".13"/>
<circle cx="67.3" cy="67.5" r=".13"/>
<circle cx="48.7" cy="46.3" r=".13"/>
<circle cx="48.7" cy="55.1" r=".13"/>
<circle cx="52.2" cy="46.3" r=".13"/>
<circle cx="52.2" cy="55.1" r=".13"/>
<circle cx="147.1" cy="142.8" r=".13"/>
<circle cx="81.5" cy="55.1" r=".13"/>
<circle cx="81.5" cy="48.9" r=".13"/>
<circle cx="84.2" cy="48.9" r=".13"/>
<circle cx="62" cy="139.2" r=".13"/>
<circle cx="126.7" cy="40.1" r=".13"/>
</g>
<path d="M113.5 48.1h25.6v25.6h-25.6z" fill-rule="evenodd" fill="#ffffb0" stroke="#800000" stroke-width=".13"/>
<g fill="none" stroke="#000" stroke-width=".13">
<path d="M110.8 56.1h2.7M110.8 56.9h2.7M110.8 57.8h2.7M110.8 58.7h2.7M110.8 59.6h2.7M121.4 45.4v2.7M122.3 45.4v2.7M123.2 45.4v2.7M124.1 45.4v2.7M125 45.4v2.7M125.9 45.4v2.7M126.8 45.4v2.7"/>
<path d="M127.6 45.4v2.7M128.5 45.4v2.7M129.4 45.4v2.7M130.3 45.4v2.7M131.2 45.4v2.7M139.2 56.1h2.6M139.2 56.9h2.6M139.2 57.8h2.6M139.2 58.7h2.6M139.2 59.6h2.6M110.8 60.5h2.7M110.8 61.4h2.7"/>
<path d="M110.8 62.3h2.7M110.8 63.1h2.7M110.8 64h2.7M110.8 64.9h2.7M110.8 65.8h2.7M121.4 73.8v2.6M122.3 73.8v2.6M123.2 73.8v2.6M124.1 73.8v2.6M125 73.8v2.6M125.9 73.8v2.6M126.8 73.8v2.6"/>
<path d="M127.6 73.8v2.6M128.5 73.8v2.6M129.4 73.8v2.6M130.3 73.8v2.6M131.2 73.8v2.6M139.2 60.5h2.6M139.2 61.4h2.6M139.2 62.3h2.6M139.2 63.1h2.6M139.2 64h2.6M139.2 64.9h2.6M139.2 65.8h2.6"/>
<path d="M148.9 142.8v.9M148.9 144.6v.9"/>
</g>
<g fill="#800000" stroke="#800000" stroke-width=".13">
<circle cx="127.6" cy="41" r=".13"/>
<circle cx="147.1" cy="145.4" r=".13"/>
</g>
<g fill="none" stroke="#f00" stroke-width=".13">
<path d="M110.4 55.7l.8 .7M110.4 58.4l.8 .7M111.2 55.7l-.8 .7M111.2 58.4l-.8 .7M51.9 143.4l.7 .7M51.9 145.1l.7 .7M52.6 143.4l-.7 .7M52.6 145.1l-.7 .7"/>
<circle cx="110.8" cy="56" r=".31"/>
<circle cx="110.8" cy="58.7" r=".31"/>
<circle cx="52.2" cy="145.4" r=".31"/>
<circle cx="52.2" cy="143.7" r=".31"/>
</g>
<path d="M148.1 144h1.6M148.1 144.3h1.6M148.9 143.7v.3M148.9 144.3v.3" fill="none" stroke="#00f" stroke-width=".13"/>
<path d="M147.2 145.5h1.7M147.2 142.8h1.7" fill="none" stroke="#000080" stroke-width=".13"/>
<use href="#words"/>
</svg>
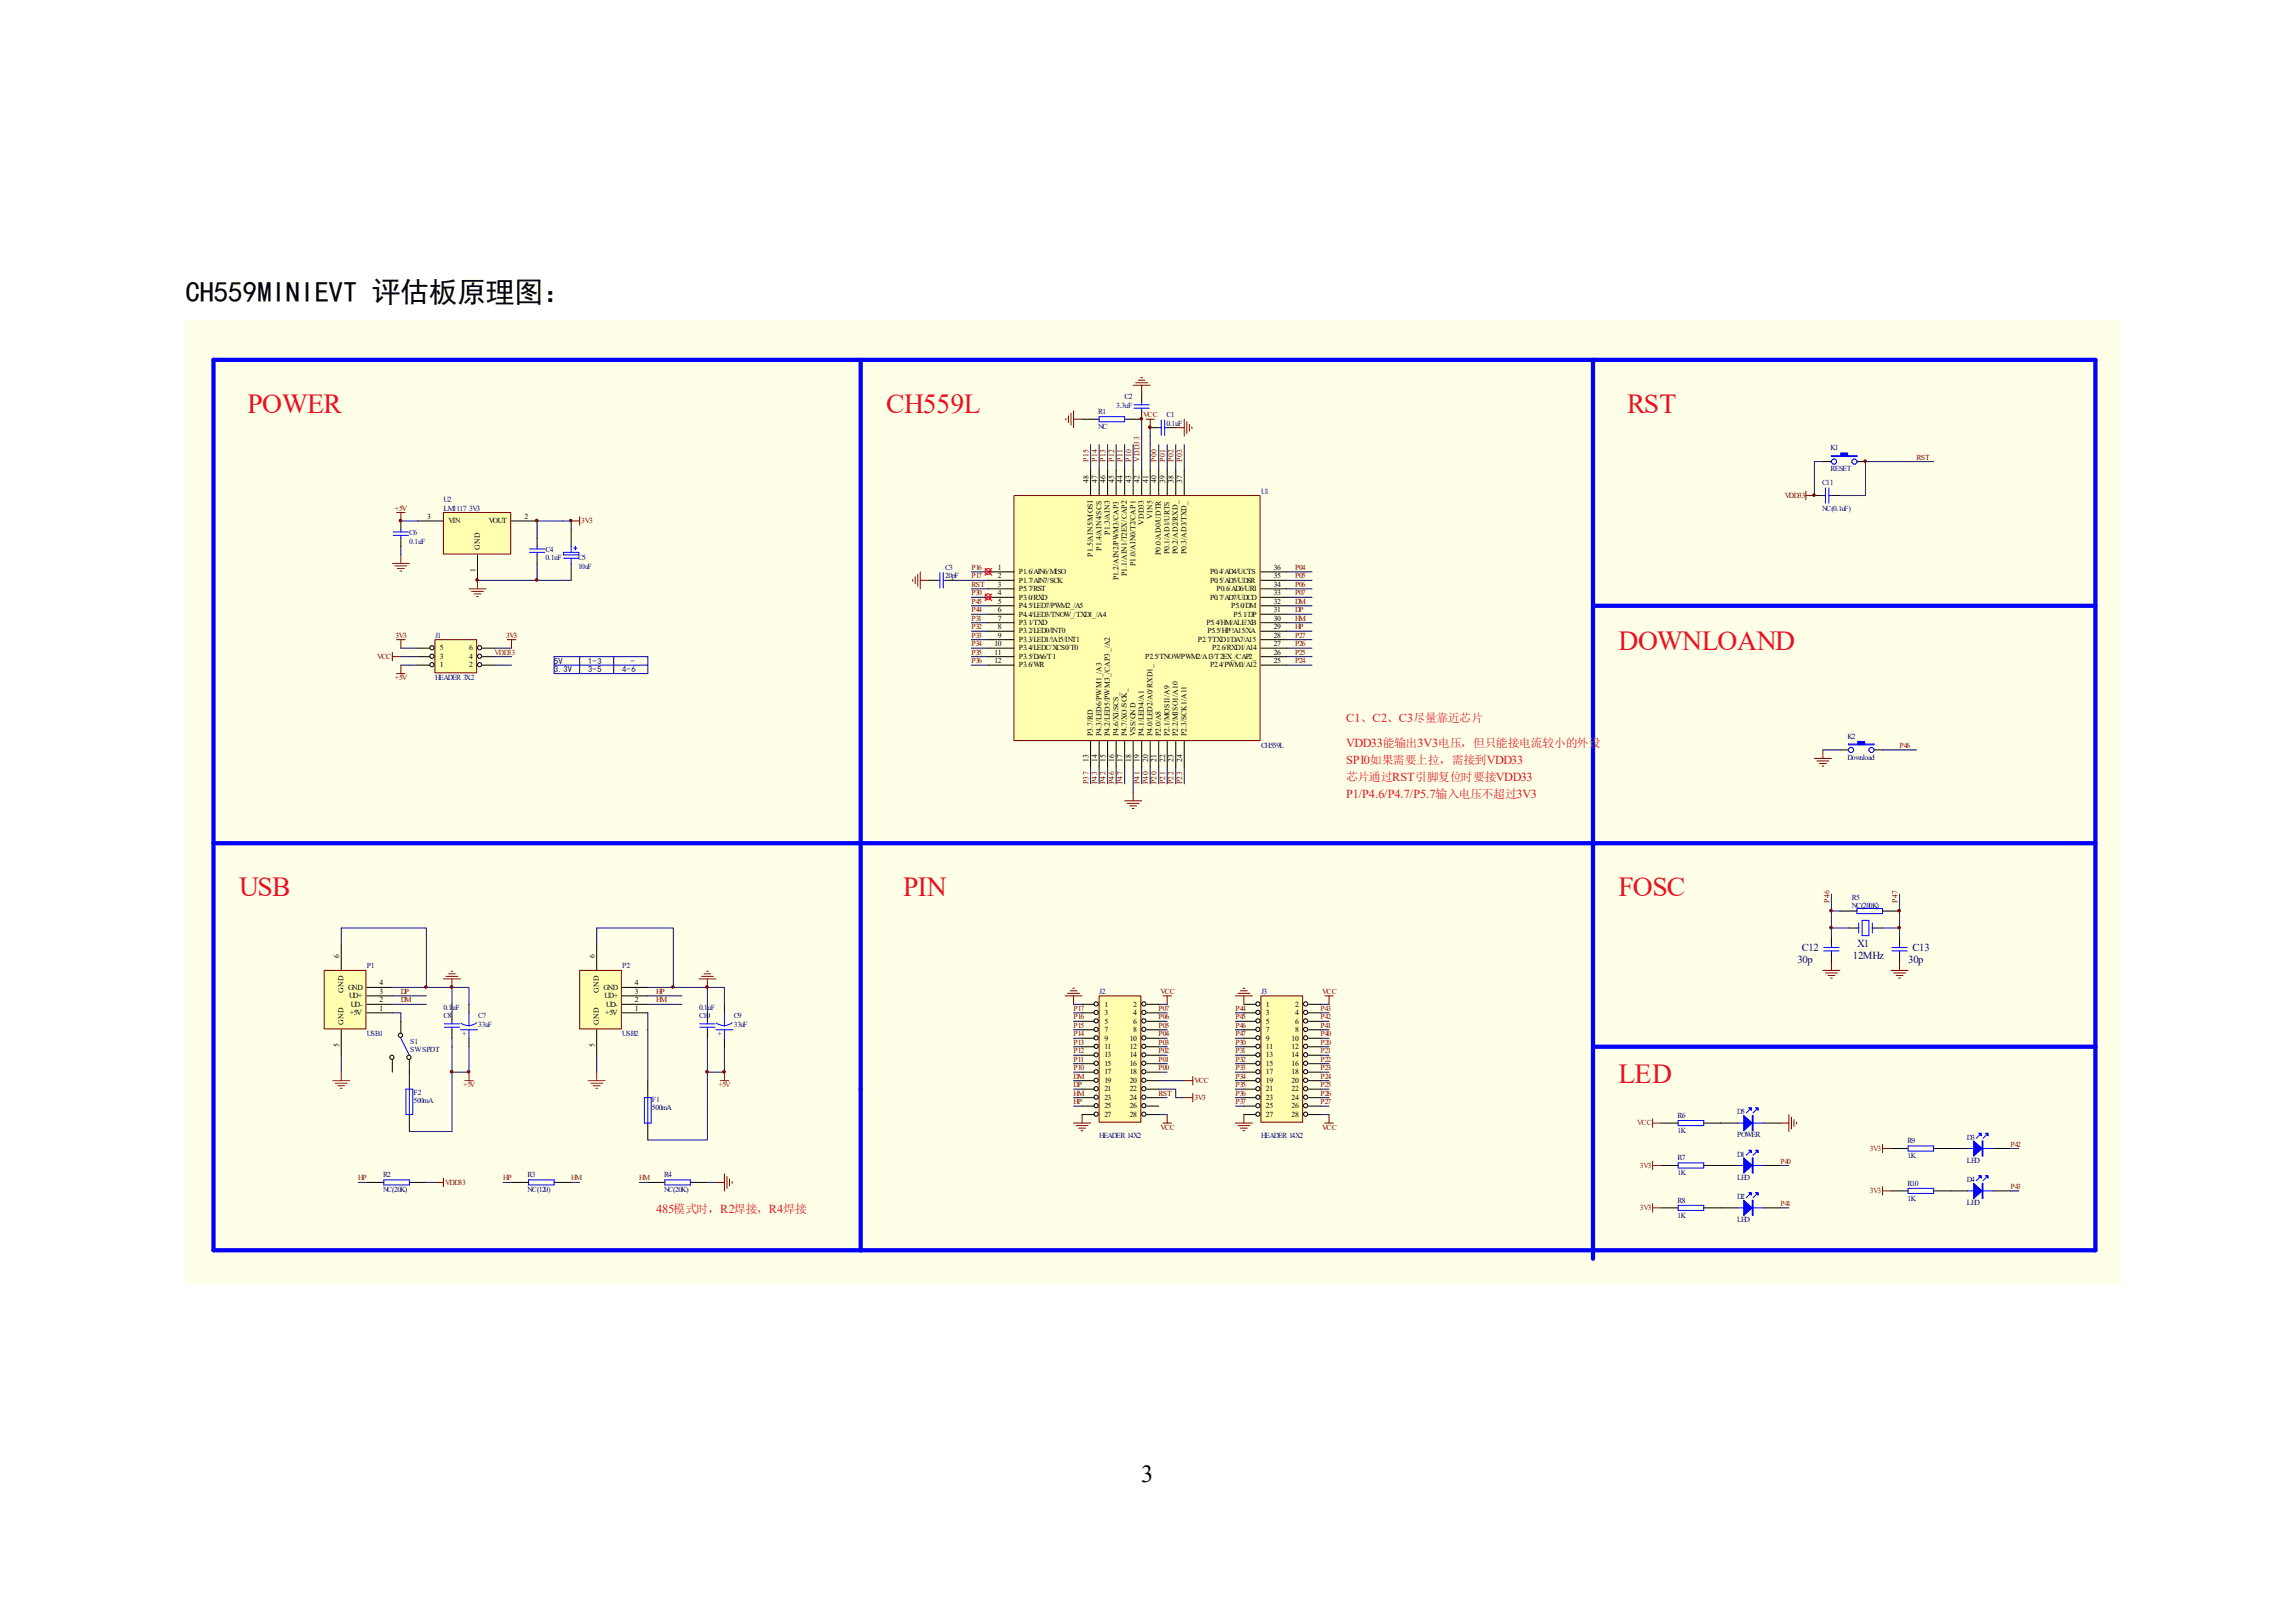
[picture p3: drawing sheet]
<svg xmlns="http://www.w3.org/2000/svg" width="297mm" height="210mm" viewBox="0 0 297 210" stroke-linecap="round" stroke-linejoin="round" font-family="sans-serif">
<defs><g id="words">
<text font-size="3.7" x="24" y="39.1">CH559MINIEVT 评估板原理图：</text>
<g font-size="3.6" fill="#ee0e22">
<text x="32" y="53.4">POWER</text>
<text x="114.7" y="53.4">CH559L</text>
<text x="210.6" y="53.4">RST</text>
<text x="209.5" y="84.1">DOWNLOAND</text>
<text x="30.9" y="115.9">USB</text>
<text x="116.9" y="115.9">PIN</text>
<text x="209.5" y="115.9">FOSC</text>
<text x="209.5" y="140.1">LED</text>
</g>
<text font-size="3.2" x="147.7" y="191.7">3</text>
<g font-size="1.6" fill="#ee0e22">
<text x="174.2" y="93.4">C1、C2、C3尽量靠近芯片</text>
<text x="174.2" y="96.6">VDD33能输出3V3电压，但只能接电流较小的外设</text>
<text x="174.2" y="98.8">SPI0如果需要上拉，需接到VDD33</text>
<text x="174.2" y="103.3">P1/P4.6/P4.7/P5.7输入电压不超过3V3</text>
<text x="84.9" y="157">485模式时，R2焊接，R4焊接</text>
</g>
<text font-size="1.5" fill="#ee0e22" x="174.2" y="101.1">芯片通过RST引脚复位时要接VDD33</text>
<g font-size="1.4" fill="#000080">
<text x="232.6" y="124.7">30p</text>
<text x="233.2" y="123">C12</text>
<text x="239.8" y="124.1">12MHz</text>
<text x="240.3" y="122.5">X1</text>
<text x="246.9" y="124.7">30p</text>
<text x="247.5" y="123">C13</text>
</g>
<g font-size="1.1" fill="#000080">
<text x="71.7" y="85.9">5V</text>
<text x="71.7" y="87">3.3V</text>
<text x="76.1" y="85.9">1-3</text>
<text x="76.1" y="87">3-5</text>
<text x="80.5" y="87">4-6</text>
<text x="81.6" y="85.9">-</text>
</g>
<g font-size="1" fill="#000080">
<text x="142.1" y="53.6">R1</text>
<text x="144.4" y="52.8">3.3uF</text>
<text x="145.5" y="51.7">C2</text>
<text x="151" y="54">C1</text>
<text x="142.1" y="55.5">NC</text>
<text x="151" y="55.1">0.1uF</text>
<text x="236.9" y="58.3">K1</text>
<text x="57.4" y="65">U2</text>
<text x="163.2" y="63.9">U1</text>
<text x="235.8" y="62.8">C11</text>
<text x="236.9" y="61">RESET</text>
<text x="53" y="69.3">C6</text>
<text x="53" y="70.4">0.1uF</text>
<text x="57.4" y="66.1">LM1117_3V3</text>
<text x="70.6" y="71.5">C4</text>
<text x="235.8" y="66.1">NC(0.1uF)</text>
<text x="70.6" y="72.5">0.1uF</text>
<text x="74.8" y="72.5">C5</text>
<text x="74.8" y="73.6">10uF</text>
<text x="122.3" y="73.7">C3</text>
<text x="122.3" y="74.8">20pF</text>
<text x="56.3" y="82.5">J1</text>
<text x="56.3" y="88">HEADER 3X2</text>
<text x="239.1" y="95.6">K2</text>
<text x="163.2" y="96.8">CH559L</text>
<text x="239.1" y="98.3">Download</text>
<text x="239.7" y="116.4">R5</text>
<text x="239.7" y="117.5">NC(200K)</text>
<text x="47.5" y="125.3">P1</text>
<text x="80.5" y="125.3">P2</text>
<text x="57.4" y="131.8">C8</text>
<text x="57.4" y="130.7">0.1uF</text>
<text x="61.9" y="131.8">C7</text>
<text x="90.5" y="131.8">C10</text>
<text x="90.5" y="130.7">0.1uF</text>
<text x="95" y="131.8">C9</text>
<text x="142.2" y="128.6">J2</text>
<text x="163.2" y="128.6">J3</text>
<text x="47.5" y="134.1">USB1</text>
<text x="53.1" y="135.1">S1</text>
<text x="53.1" y="136.2">SW SPDT</text>
<text x="60.4" y="133.5" transform="rotate(-180 60.4 133.5)">+</text>
<text x="61.9" y="132.9">33uF</text>
<text x="80.5" y="134.1">USB2</text>
<text x="93.4" y="133.5" transform="rotate(-180 93.4 133.5)">+</text>
<text x="95" y="132.9">33uF</text>
<text x="53.5" y="141.7">F2</text>
<text x="53.5" y="142.7">500mA</text>
<text x="84.4" y="142.7">F1</text>
<text x="84.4" y="143.6">500mA</text>
<text x="142.2" y="147.3">HEADER 14X2</text>
<text x="163.2" y="147.3">HEADER 14X2</text>
<text x="217.1" y="144.7">R6</text>
<text x="217.1" y="146.6">1K</text>
<text x="224.8" y="149.7">D1</text>
<text x="224.8" y="144.2">D5</text>
<text x="224.8" y="147.1">POWER</text>
<text x="246.9" y="147.9">R9</text>
<text x="246.9" y="149.9">1K</text>
<text x="254.6" y="147.5">D3</text>
<text x="49.6" y="152.3">R2</text>
<text x="49.6" y="154.3">NC(20K)</text>
<text x="68.3" y="152.3">R3</text>
<text x="68.3" y="154.3">NC(120)</text>
<text x="85.9" y="152.3">R4</text>
<text x="85.9" y="154.3">NC(20K)</text>
<text x="217.1" y="155.6">R8</text>
<text x="217.1" y="150.1">R7</text>
<text x="217.1" y="152.1">1K</text>
<text x="224.8" y="155.1">D2</text>
<text x="224.8" y="152.7">LED</text>
<text x="246.9" y="153.4">R10</text>
<text x="246.9" y="155.4">1K</text>
<text x="254.6" y="153">D4</text>
<text x="254.6" y="156">LED</text>
<text x="254.6" y="150.4">LED</text>
<text x="217.1" y="157.6">1K</text>
<text x="224.8" y="158.1">LED</text>
</g>
<g font-size="1" fill="#800000">
<text x="148" y="54">VCC</text>
<text x="140.9" y="59.7" transform="rotate(-90 140.9 59.7)">P15</text>
<text x="142" y="59.7" transform="rotate(-90 142 59.7)">P14</text>
<text x="143.1" y="59.7" transform="rotate(-90 143.1 59.7)">P13</text>
<text x="144.2" y="59.7" transform="rotate(-90 144.2 59.7)">P12</text>
<text x="145.3" y="59.7" transform="rotate(-90 145.3 59.7)">P11</text>
<text x="146.4" y="59.7" transform="rotate(-90 146.4 59.7)">P10</text>
<text x="149.7" y="59.7" transform="rotate(-90 149.7 59.7)">P00</text>
<text x="150.8" y="59.7" transform="rotate(-90 150.8 59.7)">P01</text>
<text x="151.9" y="59.7" transform="rotate(-90 151.9 59.7)">P02</text>
<text x="153" y="59.7" transform="rotate(-90 153 59.7)">P03</text>
<text x="248" y="59.5">RST</text>
<text x="231" y="64.4">VDD33</text>
<text x="51.1" y="66.1">+5V</text>
<text x="75.2" y="67.7">3V3</text>
<text x="125.7" y="73.7">P16</text>
<text x="125.7" y="74.8">P17</text>
<text x="125.7" y="77">P30</text>
<text x="125.7" y="75.9">RST</text>
<text x="167.6" y="73.7">P04</text>
<text x="167.6" y="74.8">P05</text>
<text x="167.6" y="75.9">P06</text>
<text x="167.6" y="77">P07</text>
<text x="51.2" y="82.5">3V3</text>
<text x="65.5" y="82.5">3V3</text>
<text x="125.7" y="80.3">P31</text>
<text x="125.7" y="81.4">P32</text>
<text x="125.7" y="82.5">P33</text>
<text x="125.7" y="83.6">P34</text>
<text x="125.7" y="79.2">P44</text>
<text x="125.7" y="78.1">P45</text>
<text x="167.6" y="83.6">P26</text>
<text x="167.6" y="82.5">P27</text>
<text x="167.6" y="78.1">DM</text>
<text x="167.6" y="79.2">DP</text>
<text x="167.6" y="80.3">HM</text>
<text x="167.6" y="81.4">HP</text>
<text x="48.8" y="85.3">VCC</text>
<text x="51.1" y="88">+5V</text>
<text x="125.7" y="84.7">P35</text>
<text x="125.7" y="85.8">P36</text>
<text x="167.6" y="85.8">P24</text>
<text x="167.6" y="84.7">P25</text>
<text x="140.9" y="101.4" transform="rotate(-90 140.9 101.4)">P37</text>
<text x="142" y="101.4" transform="rotate(-90 142 101.4)">P43</text>
<text x="143.1" y="101.4" transform="rotate(-90 143.1 101.4)">P42</text>
<text x="144.2" y="101.4" transform="rotate(-90 144.2 101.4)">P46</text>
<text x="145.3" y="101.4" transform="rotate(-90 145.3 101.4)">P47</text>
<text x="147.5" y="101.4" transform="rotate(-90 147.5 101.4)">P41</text>
<text x="148.6" y="101.4" transform="rotate(-90 148.6 101.4)">P40</text>
<text x="149.7" y="101.4" transform="rotate(-90 149.7 101.4)">P20</text>
<text x="150.8" y="101.4" transform="rotate(-90 150.8 101.4)">P21</text>
<text x="151.9" y="101.4" transform="rotate(-90 151.9 101.4)">P22</text>
<text x="153" y="101.4" transform="rotate(-90 153 101.4)">P23</text>
<text x="245.8" y="96.8">P46</text>
<text x="236.8" y="116.8" transform="rotate(-90 236.8 116.8)">P46</text>
<text x="245.6" y="116.8" transform="rotate(-90 245.6 116.8)">P47</text>
<text x="51.9" y="128.6">DP</text>
<text x="51.9" y="129.7">DM</text>
<text x="84.9" y="128.6">HP</text>
<text x="84.9" y="129.7">HM</text>
<text x="138.9" y="131.9">P16</text>
<text x="138.9" y="130.8">P17</text>
<text x="149.9" y="131.9">P06</text>
<text x="149.9" y="130.8">P07</text>
<text x="150.2" y="128.6">VCC</text>
<text x="159.9" y="130.8">P44</text>
<text x="159.9" y="131.9">P45</text>
<text x="171.1" y="128.6">VCC</text>
<text x="138.9" y="137.4">P11</text>
<text x="138.9" y="136.3">P12</text>
<text x="138.9" y="135.2">P13</text>
<text x="138.9" y="134.1">P14</text>
<text x="138.9" y="133">P15</text>
<text x="149.9" y="137.4">P01</text>
<text x="149.9" y="136.3">P02</text>
<text x="149.9" y="135.2">P03</text>
<text x="149.9" y="134.1">P04</text>
<text x="149.9" y="133">P05</text>
<text x="159.9" y="135.2">P30</text>
<text x="159.9" y="136.3">P31</text>
<text x="159.9" y="137.4">P32</text>
<text x="159.9" y="133">P46</text>
<text x="159.9" y="134.1">P47</text>
<text x="170.9" y="137.4">P22</text>
<text x="170.9" y="134.1">P40</text>
<text x="170.9" y="133">P41</text>
<text x="138.9" y="138.5">P10</text>
<text x="138.9" y="139.6">DM</text>
<text x="138.9" y="140.7">DP</text>
<text x="138.9" y="141.8">HM</text>
<text x="138.9" y="142.9">HP</text>
<text x="149.9" y="138.5">P00</text>
<text x="149.9" y="141.8">RST</text>
<text x="154.6" y="142.3">3V3</text>
<text x="154.6" y="140.1">VCC</text>
<text x="159.9" y="138.5">P33</text>
<text x="159.9" y="139.6">P34</text>
<text x="159.9" y="140.7">P35</text>
<text x="159.9" y="141.8">P36</text>
<text x="159.9" y="142.9">P37</text>
<text x="170.9" y="138.5">P23</text>
<text x="170.9" y="139.6">P24</text>
<text x="170.9" y="140.7">P25</text>
<text x="170.9" y="141.8">P26</text>
<text x="170.9" y="142.9">P27</text>
<text x="150.2" y="146.2">VCC</text>
<text x="171.1" y="146.2">VCC</text>
<text x="57.6" y="153.3">VDD33</text>
</g>
<g font-size="1" fill="#781915">
<text x="147.5" y="59.7" transform="rotate(-90 147.5 59.7)">VDD33</text>
<text x="64" y="84.7">VDD33</text>
<text x="170.9" y="131.9">P42</text>
<text x="170.9" y="130.8">P43</text>
<text x="170.9" y="135.2">P20</text>
<text x="170.9" y="136.3">P21</text>
<text x="59.9" y="140.7">+5V</text>
<text x="93" y="140.7">+5V</text>
<text x="211.9" y="145.6">VCC</text>
<text x="242" y="148.9">3V3</text>
<text x="260.2" y="148.4">P42</text>
<text x="46.4" y="152.7">HP</text>
<text x="65.1" y="152.7">HP</text>
<text x="73.9" y="152.7">HM</text>
<text x="82.7" y="152.7">HM</text>
<text x="212.2" y="151.1">3V3</text>
<text x="230.4" y="150.6">P40</text>
<text x="242" y="154.4">3V3</text>
<text x="260.2" y="153.8">P43</text>
<text x="212.2" y="156.6">3V3</text>
<text x="230.4" y="156">P41</text>
</g>
<g font-size="1">
<text x="140.9" y="62.5" transform="rotate(-90 140.9 62.5)">48</text>
<text x="142" y="62.5" transform="rotate(-90 142 62.5)">47</text>
<text x="143.1" y="62.5" transform="rotate(-90 143.1 62.5)">46</text>
<text x="144.2" y="62.5" transform="rotate(-90 144.2 62.5)">45</text>
<text x="145.3" y="62.5" transform="rotate(-90 145.3 62.5)">44</text>
<text x="146.4" y="62.5" transform="rotate(-90 146.4 62.5)">43</text>
<text x="147.5" y="62.5" transform="rotate(-90 147.5 62.5)">42</text>
<text x="148.6" y="62.5" transform="rotate(-90 148.6 62.5)">41</text>
<text x="149.7" y="62.5" transform="rotate(-90 149.7 62.5)">40</text>
<text x="150.8" y="62.5" transform="rotate(-90 150.8 62.5)">39</text>
<text x="151.9" y="62.5" transform="rotate(-90 151.9 62.5)">38</text>
<text x="153" y="62.5" transform="rotate(-90 153 62.5)">37</text>
<text x="55.3" y="67.1">3</text>
<text x="58" y="67.7">VIN</text>
<text x="62.1" y="71.2" transform="rotate(-90 62.1 71.2)">GND</text>
<text x="63.2" y="67.7">VOUT</text>
<text x="67.9" y="67.1">2</text>
<text x="142.5" y="71.2" transform="rotate(-90 142.5 71.2)">P1.4/AIN4/SCS</text>
<text x="143.6" y="69.2" transform="rotate(-90 143.6 69.2)">P1.3/AIN3</text>
<text x="148" y="67.9" transform="rotate(-90 148 67.9)">VDD33</text>
<text x="149.1" y="67.1" transform="rotate(-90 149.1 67.1)">VIN5</text>
<text x="150.2" y="71.8" transform="rotate(-90 150.2 71.8)">P0.0/AD0/UDTR</text>
<text x="151.3" y="71.7" transform="rotate(-90 151.3 71.7)">P0.1/AD1/URTS</text>
<text x="152.4" y="71.7" transform="rotate(-90 152.4 71.7)">P0.2/AD2/RXD_</text>
<text x="153.5" y="71.7" transform="rotate(-90 153.5 71.7)">P0.3/AD3/TXD_</text>
<text x="61.6" y="74" transform="rotate(-90 61.6 74)">1</text>
<text x="129.1" y="73.7">1</text>
<text x="129.1" y="74.8">2</text>
<text x="129.1" y="75.9">3</text>
<text x="129.1" y="77">4</text>
<text x="131.9" y="74.3">P1.6/AIN6/MISO</text>
<text x="131.9" y="75.4">P1.7/AIN7/SCK</text>
<text x="131.9" y="76.5">P5.7/RST</text>
<text x="131.9" y="77.6">P3.0/RXD</text>
<text x="141.4" y="72" transform="rotate(-90 141.4 72)">P1.5/AIN5/MOSI</text>
<text x="144.7" y="75.1" transform="rotate(-90 144.7 75.1)">P1.2/AIN2/PWM3/CAP3</text>
<text x="145.8" y="74.6" transform="rotate(-90 145.8 74.6)">P1.1/AIN1/T2EX/CAP2</text>
<text x="146.9" y="73.2" transform="rotate(-90 146.9 73.2)">P1.0/AIN0/T2/CAP1</text>
<text x="156.6" y="77.6">P0.7/AD7/UDCD</text>
<text x="156.6" y="75.4">P0.5/AD5/UDSR</text>
<text x="156.6" y="74.3">P0.4/AD4/UCTS</text>
<text x="157.4" y="76.5">P0.6/AD6/URI</text>
<text x="164.9" y="77">33</text>
<text x="164.9" y="75.9">34</text>
<text x="164.9" y="74.8">35</text>
<text x="164.9" y="73.7">36</text>
<text x="128.7" y="83.6">10</text>
<text x="129.1" y="79.2">6</text>
<text x="129.1" y="80.3">7</text>
<text x="129.1" y="81.4">8</text>
<text x="129.1" y="82.5">9</text>
<text x="129.1" y="78.1">5</text>
<text x="131.9" y="79.8">P4.4/LED3/TNOW_/TXD1_/A4</text>
<text x="131.9" y="80.9">P3.1/TXD</text>
<text x="131.9" y="82">P3.2/LED0/INT0</text>
<text x="131.9" y="83.1">P3.3/LED1/!A15/INT1</text>
<text x="131.9" y="78.7">P4.5/LED7/PWM2_/A5</text>
<text x="155" y="83.1">P2.7/TXD1/DA7/A15</text>
<text x="156.1" y="80.9">P5.4/HM/ALE/XB</text>
<text x="156.3" y="82">P5.5/HP/!A15/XA</text>
<text x="159.3" y="78.7">P5.0/DM</text>
<text x="159.6" y="79.8">P5.1/DP</text>
<text x="164.9" y="83.6">27</text>
<text x="164.9" y="82.5">28</text>
<text x="164.9" y="81.4">29</text>
<text x="164.9" y="80.3">30</text>
<text x="164.9" y="79.2">31</text>
<text x="164.9" y="78.1">32</text>
<text x="56.9" y="86.4">1</text>
<text x="56.9" y="85.3">3</text>
<text x="56.9" y="84.2">5</text>
<text x="60.7" y="86.4">2</text>
<text x="60.7" y="85.3">4</text>
<text x="60.7" y="84.2">6</text>
<text x="128.7" y="84.7">11</text>
<text x="128.7" y="85.8">12</text>
<text x="131.9" y="84.2">P3.4/LEDC/XCS0/T0</text>
<text x="131.9" y="85.3">P3.5/DA6/T1</text>
<text x="131.9" y="86.4">P3.6/WR</text>
<text x="148.2" y="85.3">P2.5/TNOW/PWM2/A13/T2EX_/CAP2_</text>
<text x="156.6" y="86.4">P2.4/PWM1/A12</text>
<text x="156.9" y="84.2">P2.6/RXD1/A14</text>
<text x="164.9" y="85.8">25</text>
<text x="164.9" y="84.7">26</text>
<text x="141.4" y="95.3" transform="rotate(-90 141.4 95.3)">P3.7/RD</text>
<text x="142.5" y="95.3" transform="rotate(-90 142.5 95.3)">P4.3/LED6/PWM1_/A3</text>
<text x="143.6" y="95.3" transform="rotate(-90 143.6 95.3)">P4.2/LED5/PWM3_/CAP3_/A2</text>
<text x="144.7" y="95.3" transform="rotate(-90 144.7 95.3)">P4.6/XI/SCS_</text>
<text x="145.8" y="95.3" transform="rotate(-90 145.8 95.3)">P4.7/XO/SCK_</text>
<text x="146.9" y="95.3" transform="rotate(-90 146.9 95.3)">VSS/GND</text>
<text x="148" y="95.3" transform="rotate(-90 148 95.3)">P4.1/LED4/A1</text>
<text x="149.1" y="95.3" transform="rotate(-90 149.1 95.3)">P4.0/LED2/A0/RXD1_</text>
<text x="150.2" y="95.3" transform="rotate(-90 150.2 95.3)">P2.0/A8</text>
<text x="151.3" y="95.3" transform="rotate(-90 151.3 95.3)">P2.1/MOSI1/A9</text>
<text x="152.4" y="95.3" transform="rotate(-90 152.4 95.3)">P2.2/MISO1/A10</text>
<text x="153.5" y="95.3" transform="rotate(-90 153.5 95.3)">P2.3/SCK1/A11</text>
<text x="140.9" y="98.6" transform="rotate(-90 140.9 98.6)">13</text>
<text x="142" y="98.6" transform="rotate(-90 142 98.6)">14</text>
<text x="143.1" y="98.6" transform="rotate(-90 143.1 98.6)">15</text>
<text x="144.2" y="98.6" transform="rotate(-90 144.2 98.6)">16</text>
<text x="145.3" y="98.6" transform="rotate(-90 145.3 98.6)">17</text>
<text x="146.4" y="98.6" transform="rotate(-90 146.4 98.6)">18</text>
<text x="147.5" y="98.6" transform="rotate(-90 147.5 98.6)">19</text>
<text x="148.6" y="98.6" transform="rotate(-90 148.6 98.6)">20</text>
<text x="149.7" y="98.6" transform="rotate(-90 149.7 98.6)">21</text>
<text x="150.8" y="98.6" transform="rotate(-90 150.8 98.6)">22</text>
<text x="151.9" y="98.6" transform="rotate(-90 151.9 98.6)">23</text>
<text x="153" y="98.6" transform="rotate(-90 153 98.6)">24</text>
<text x="43.9" y="123.9" transform="rotate(-90 43.9 123.9)">6</text>
<text x="77" y="123.9" transform="rotate(-90 77 123.9)">6</text>
<text x="44.4" y="128.4" transform="rotate(-90 44.4 128.4)">GND</text>
<text x="45" y="128.1">GND</text>
<text x="45.2" y="129.2">UD+</text>
<text x="45.3" y="131.4">+5V</text>
<text x="45.4" y="130.3">UD-</text>
<text x="49.1" y="130.8">1</text>
<text x="49.1" y="127.5">4</text>
<text x="49.1" y="128.6">3</text>
<text x="49.1" y="129.7">2</text>
<text x="77.5" y="128.4" transform="rotate(-90 77.5 128.4)">GND</text>
<text x="78.1" y="128.1">GND</text>
<text x="78.2" y="129.2">UD+</text>
<text x="78.3" y="131.4">+5V</text>
<text x="78.4" y="130.3">UD-</text>
<text x="82.2" y="130.8">1</text>
<text x="82.2" y="127.5">4</text>
<text x="82.2" y="128.6">3</text>
<text x="82.2" y="129.7">2</text>
<text x="142.9" y="130.3">1</text>
<text x="142.9" y="131.4">3</text>
<text x="146.6" y="130.3">2</text>
<text x="146.6" y="131.4">4</text>
<text x="163.8" y="130.3">1</text>
<text x="163.8" y="131.4">3</text>
<text x="167.6" y="130.3">2</text>
<text x="167.6" y="131.4">4</text>
<text x="43.9" y="135.5" transform="rotate(-90 43.9 135.5)">5</text>
<text x="44.4" y="132.6" transform="rotate(-90 44.4 132.6)">GND</text>
<text x="77" y="135.5" transform="rotate(-90 77 135.5)">5</text>
<text x="77.5" y="132.6" transform="rotate(-90 77.5 132.6)">GND</text>
<text x="142.9" y="132.5">5</text>
<text x="142.9" y="133.6">7</text>
<text x="142.9" y="134.7">9</text>
<text x="142.9" y="135.8">11</text>
<text x="142.9" y="136.8">13</text>
<text x="142.9" y="137.9">15</text>
<text x="146.2" y="134.7">10</text>
<text x="146.2" y="135.8">12</text>
<text x="146.2" y="136.8">14</text>
<text x="146.2" y="137.9">16</text>
<text x="146.6" y="132.5">6</text>
<text x="146.6" y="133.6">8</text>
<text x="163.8" y="132.5">5</text>
<text x="163.8" y="133.6">7</text>
<text x="163.8" y="134.7">9</text>
<text x="163.8" y="135.8">11</text>
<text x="163.8" y="136.8">13</text>
<text x="163.8" y="137.9">15</text>
<text x="167.1" y="134.7">10</text>
<text x="167.1" y="135.8">12</text>
<text x="167.1" y="136.8">14</text>
<text x="167.1" y="137.9">16</text>
<text x="167.6" y="132.5">6</text>
<text x="167.6" y="133.6">8</text>
<text x="142.9" y="139">17</text>
<text x="142.9" y="140.1">19</text>
<text x="142.9" y="141.2">21</text>
<text x="142.9" y="142.3">23</text>
<text x="142.9" y="143.4">25</text>
<text x="146.2" y="139">18</text>
<text x="146.2" y="140.1">20</text>
<text x="146.2" y="141.2">22</text>
<text x="146.2" y="142.3">24</text>
<text x="146.2" y="143.4">26</text>
<text x="163.8" y="139">17</text>
<text x="163.8" y="140.1">19</text>
<text x="163.8" y="141.2">21</text>
<text x="163.8" y="142.3">23</text>
<text x="163.8" y="143.4">25</text>
<text x="167.1" y="139">18</text>
<text x="167.1" y="140.1">20</text>
<text x="167.1" y="141.2">22</text>
<text x="167.1" y="142.3">24</text>
<text x="167.1" y="143.4">26</text>
<text x="142.9" y="144.5">27</text>
<text x="146.2" y="144.5">28</text>
<text x="163.8" y="144.5">27</text>
<text x="167.1" y="144.5">28</text>
</g>
</g></defs>
<path d="M24 41.4h250.4v124.8h-250.4z" fill-rule="evenodd" fill="#ffffe8"/>
<g fill="none" stroke="#800000" stroke-width=".13">
<path d="M145.5 103.6h2.3M145.9 104h1.5M146.2 104.3h.9M146.5 104.6h.3M146.7 102.5v1.1M235.9 125.6h2.2M236.2 125.9h1.6M236.6 126.2h.9M236.9 126.6h.2M237 124.5v1.1M244.7 125.6h2.2M245.1 125.9h1.5"/>
<path d="M245.4 126.2h.9M245.7 126.6h.2M245.8 124.5v1.1"/>
</g>
<g fill="none" stroke="#00f" stroke-width=".13">
<path d="M240.5 119.4v1.3M241 119.1h.9v2h-.9zM242.3 119.4v1.3M236 123h2M236 122.6h2M237 122.3v.3M237 123v.4M240.3 120.1h.2M242.3 120.1h.2M244.8 123h2M244.8 122.6h2M245.8 122.3v.3"/>
<path d="M245.8 123v.4"/>
</g>
<path d="M237 121.2v1.1M237 123.4v1.1M239.2 120.1h1.1M242.5 120.1h1.1M245.8 121.2v1.1M245.8 123.4v1.1" fill="none" stroke="#000" stroke-width=".13"/>
<path d="M42 125.6h5.4v7.5h-5.4z" fill-rule="evenodd" fill="#ffffb0" stroke="#800000" stroke-width=".13"/>
<path d="M44.2 122.3v3.3M44.2 133.3v3.2M47.5 131.1h3.3M47.5 127.8h3.3M47.5 128.9h3.3M47.5 130h3.3M53 138.7v2.2M58.5 131.1v1.1M58.5 133.3v1.1M60.7 130v1.1M60.7 134.4v1M53 144.2v2.2" fill="none" stroke="#000" stroke-width=".13"/>
<path d="M44.2 120.1v2.2M44.2 136.5v2.2M50.8 127.8h7.7v3.3M50.8 128.9h4.4M50.8 130h4.4M58.5 127.8h2.2v2.2M58.5 134.4v12M60.7 135.4v3.3h-2.2" fill="none" stroke="#000080" stroke-width=".13"/>
<path d="M43.1 139.8h2.2M44.2 138.7v1.1M57.4 126.7h2.2M57.7 126.3h1.6M58 126h.9M58.4 125.7h.2M58.5 126.7v1.1M60.1 139.8h1.1M60.7 138.7v1.1M43.4 140.2h1.5M43.7 140.5h.9M44.1 140.8h.2" fill="none" stroke="#781915" stroke-width=".13"/>
<path d="M57.5 132.9h2M57.5 132.5h2M58.5 132.2v.3M58.5 132.9v.4M59.6 133.3h2.2M60.7 131.1v1.7M60.7 133.3v1.1M61.7 132.3a1.72 1.72 0 0 1-2 .1M52.5 140.9h.9v3.3h-.9zM53 140.9v3.3" fill="none" stroke="#00f" stroke-width=".13"/>
<path d="M75 125.6h5.4v7.5h-5.4z" fill-rule="evenodd" fill="#ffffb0" stroke="#800000" stroke-width=".13"/>
<g fill="none" stroke="#000" stroke-width=".13">
<path d="M73.9 68.5v2.2M73.9 72.9v2.2M77.2 122.3v3.3M77.2 133.3v3.2M80.5 131.1h3.3M80.5 127.8h3.3M80.5 128.9h3.3M80.5 130h3.3M83.8 139.8v2.2M91.5 131.1v1.1M91.5 133.3v1.1M93.8 130v1.1"/>
<path d="M93.8 134.4v1M83.8 145.3v2.2"/>
</g>
<path d="M77.2 120.1v2.2M77.2 136.5v2.2M83.8 127.8h7.7v3.3M83.8 128.9h4.4M83.8 130h4.4M91.5 127.8h2.3v2.2M91.5 134.4v4.3h2.3v-3.3" fill="none" stroke="#000080" stroke-width=".13"/>
<path d="M76.1 139.8h2.2M77.2 138.7v1.1M90.4 126.7h2.3M90.8 126.3h1.5M91.1 126h.9M91.4 125.7h.3M91.5 126.7v1.1M93.2 139.8h1.1M93.8 138.7v1.1M76.5 140.2h1.5M76.8 140.5h.9M77.1 140.8h.2" fill="none" stroke="#781915" stroke-width=".13"/>
<g fill="none" stroke="#00f" stroke-width=".13">
<path d="M72.9 71.5h2v.3h-2zM72.9 72.2h2M73.9 70.7v.8M73.9 72.2v.7M74.2 70.9h.5M74.5 70.7v.4M90.6 132.9h1.9M90.6 132.5h1.9M91.5 132.2v.3M91.5 132.9v.4M92.7 133.3h2.2M93.8 131.1v1.7"/>
<path d="M93.8 133.3v1.1M94.7 132.3a1.72 1.72 0 0 1-2 .1M83.4 142h.9v3.3h-.9zM83.8 142v3.3"/>
</g>
<g fill="#800000" stroke="#800000" stroke-width=".13">
<circle cx="87.1" cy="127.7" r=".16"/>
<circle cx="55.1" cy="127.7" r=".16"/>
</g>
<path d="M51.3 66.3h1.1M51.9 66.3v1.1" fill="none" stroke="#800000" stroke-width=".13"/>
<path d="M57.4 66.3h8.7v5.4h-8.7z" fill-rule="evenodd" fill="#ffffb0" stroke="#800000" stroke-width=".13"/>
<g fill="none" stroke="#000" stroke-width=".13">
<path d="M147.8 51v1.1M147.8 53.1v1.1M235.9 59.7h1.1M240.3 59.7h1.1M51.9 67.4v1.1M51.9 69.6v1.1M54.1 67.4h3.3M61.8 71.8v3.3M66.2 67.4h3.3M69.5 69.6v1.1M69.5 71.8v1.1M215 156.3h2.2"/>
<path d="M215 150.8h2.2M215 145.3h2.2M220.5 156.3h4.4M220.5 150.8h4.4M220.5 145.3h4.4M228.2 156.3h2.2M228.2 150.8h2.2M228.2 145.3h2.2M244.7 154.1h2.2M244.7 148.6h2.2M250.2 154.1h4.5M250.2 148.6h4.5"/>
<path d="M258 154.1h2.2M258 148.6h2.2"/>
</g>
<g fill="none" stroke="#000080" stroke-width=".13">
<path d="M141.1 57.5v3.3M142.2 57.5v3.3M143.3 57.5v3.3M144.4 57.5v3.3M145.5 57.5v3.3M146.7 57.5v3.3M147.8 54.2v6.6M148.9 57.5v3.3M150 57.5v3.3M151.1 57.5v3.3M152.2 57.5v3.3M153.3 57.5v3.3"/>
<path d="M235.9 59.7h-1.1v4.4M246.9 59.7h-5.5v4.4M51.9 67.4h2.2M51.9 70.7v1.1M61.8 75.1h11M69.5 72.9v2.2M72.8 67.4h-3.3v2.2M73.9 67.4v1.1M125.7 75.1h2.2M125.7 74h2.2M125.7 76.2h2.2M125.7 77.3h2.2"/>
<path d="M125.7 79.5h2.2M166.5 75.1h3.3M166.5 74h3.3M166.5 76.2h3.3M166.5 77.3h3.3M166.5 79.5h3.3M166.5 78.4h3.3M238.1 64.1h2.2M125.7 80.6h2.2M125.7 81.7h2.2M125.7 82.8h2.2M125.7 83.9h2.2"/>
<path d="M125.7 85h2.2M125.7 86.1h2.2M141.1 99.2v2.2M142.2 99.2v2.2M143.3 99.2v2.2M144.4 99.2v2.2M145.5 99.2v2.2M146.7 99.2v3.3M147.8 99.2v2.2M148.9 99.2v2.2M150 99.2v2.2M151.1 99.2v2.2"/>
<path d="M152.2 99.2v2.2M153.3 99.2v2.2M166.5 80.6h3.3M166.5 81.7h3.3M166.5 82.8h3.3M166.5 83.9h3.3M166.5 86.1h3.3M237 117.9v2.2M245.8 117.9v2.2M138.9 131.1h1.1M138.9 132.2h1.1M138.9 133.3h1.1"/>
<path d="M138.9 134.4h1.1M138.9 139.8h1.1M138.9 138.7h1.1M138.9 137.6h1.1M138.9 136.5h1.1M138.9 130h1.1M138.9 135.4h1.1M150 131.1h1.1M150 132.2h1.1M150 133.3h1.1M150 134.4h1.1M150 138.7h1.1"/>
<path d="M150 137.6h1.1M150 136.5h1.1M150 130h1.1M150 135.4h1.1M159.9 131.1h1.1M159.9 132.2h1.1M159.9 133.3h1.1M159.9 134.4h1.1M159.9 139.8h1.1M159.9 138.7h1.1M159.9 137.6h1.1M159.9 136.5h1.1"/>
<path d="M159.9 135.4h1.1M170.9 131.1h1.1M170.9 132.2h1.1M170.9 133.3h1.1M170.9 134.4h1.1M170.9 139.8h1.1M170.9 138.7h1.1M170.9 137.6h1.1M170.9 136.5h1.1M170.9 130h1.1M170.9 135.4h1.1M239.2 120.1h-2.2v1.1"/>
<path d="M243.6 120.1h2.2v1.1M138.9 142h1.1M138.9 140.9h1.1M138.9 143.1h1.1M150 142h1.1M150 144.2h1.1M159.9 142h1.1M159.9 140.9h1.1M159.9 143.1h1.1M170.9 142h1.1M170.9 140.9h1.1M170.9 143.1h1.1"/>
<path d="M170.9 144.2h1.1M230.4 150.8h1.1M230.4 156.3h1.1M260.2 148.6h1.1M260.2 154.1h1.1"/>
</g>
<g fill="none" stroke="#00f" stroke-width=".13">
<path d="M146.8 52.4h1.9M146.8 52.8h1.9M147.8 52.1v.3M147.8 52.8v.3M237 59h3.3v.1h-3.3zM237 59.6l.2-.2h.3l.2 .2v.2l-.2 .3h-.3l-.2-.3zM238.2 59.1v-.5h.9v.5M238.2 58.9h.9M238.2 58.7h.9M238.3 58.6v.5M238.5 58.6v.5M238.6 58.6v.5"/>
<path d="M238.7 58.6v.5M238.8 58.6v.5M238.9 58.6v.5M239 58.6v.5M239.7 59.6l.2-.2h.2l.2 .2v.2l-.2 .3h-.2l-.2-.3zM50.9 69.3h2M50.9 68.8h2M51.9 68.5v.3M51.9 69.3v.3M68.5 71.5h2M68.5 71h2M69.5 70.7v.3"/>
<path d="M69.5 71.5v.3M217.2 145h3.3v.7h-3.3zM217.2 150.5h3.3v.6h-3.3zM217.2 156h3.3v.6h-3.3zM224.9 156.3h3.3M224.9 150.8h3.3M224.9 145.3h3.3M226.4 154.5l-.4 .5M226.4 149.1l-.4 .4M226.4 143.6l-.4 .4M227.3 154.5l-.4 .5M227.3 149.1l-.4 .4"/>
<path d="M227.3 143.6l-.4 .4M246.9 148.3h3.3v.6h-3.3zM246.9 153.8h3.3v.6h-3.3zM254.7 154.1h3.3M254.7 148.6h3.3M256.2 152.3l-.4 .5M256.2 146.9l-.4 .4M257.1 152.3l-.5 .5M257.1 146.9l-.5 .4"/>
</g>
<g fill="none" stroke="#781915" stroke-width=".13">
<path d="M50.8 72.9h2.2M51.1 73.2h1.5M51.4 73.6h.9M51.8 73.9h.2M51.9 71.8v1.1M213.9 144.8v1.1M213.9 150.3v1.1M213.9 155.7v1.1M213.9 156.3h1.1M213.9 150.8h1.1M213.9 145.3h1.1M243.6 148.1v1.1"/>
<path d="M243.6 153.6v1.1M243.6 154.1h1.1M243.6 148.6h1.1"/>
</g>
<circle cx="73.9" cy="67.4" r=".16" fill="#800000" stroke="#800000" stroke-width=".13"/>
<g fill="none" stroke="#800000" stroke-width=".13">
<path d="M146.7 49.9h2.2M147 49.5h1.5M147.3 49.2h.9M147.6 48.9h.3M147.8 49.9v1.1M233.7 63.6v1.1M233.7 64.1h1.1M137.8 128.9h2.2M138.2 128.5h1.5M138.5 128.2h.9M138.8 127.9h.2M138.9 128.9v1.1"/>
<path d="M150.5 128.9h1.1M151.1 128.9v1.1M159.9 128.9h2.2M160.2 128.5h1.5M160.5 128.2h.9M160.9 127.9h.2M161 128.9v1.1M171.4 128.9h1.1M172 128.9v1.1M138.9 145.3h2.2M139.3 145.7h1.5M139.6 146h.9"/>
<path d="M139.9 146.3h.2M140 144.2v1.1M150.5 145.3h1.1M151.1 144.2v1.1M159.9 145.3h2.2M160.2 145.7h1.5M160.5 146h.9M160.9 146.3h.2M161 144.2v1.1M171.4 145.3h1.1M172 144.2v1.1M230.4 145.3h1.1"/>
<path d="M231.5 144.2v2.2M231.8 144.6v1.5M232.2 144.9v.9M232.5 145.2v.2"/>
</g>
<g fill="#00f" stroke="#00f" stroke-width=".13">
<path d="M255.4 153.1l1.1 1-1.1 1z"/>
<path d="M257 152.1h.3v.4z"/>
<path d="M256.1 152.1h.3v.4z"/>
<path d="M255.4 147.6l1.1 1-1.1 1z"/>
<path d="M257 146.6h.3v.4z"/>
<path d="M256.1 146.6h.3v.4z"/>
<path d="M225.7 155.3l1.1 1-1.1 1z"/>
<path d="M227.2 154.3h.3v.4z"/>
<path d="M226.3 154.3h.4v.4z"/>
<path d="M225.7 149.8l1.1 1-1.1 1z"/>
<path d="M227.2 148.8h.3v.4z"/>
<path d="M226.3 148.8h.4v.4z"/>
<path d="M225.7 144.3l1.1 1-1.1 1z"/>
<path d="M227.2 143.3h.3v.4z"/>
<path d="M226.3 143.3h.4v.4z"/>
<path d="M256.5 153.1h.1v2h-.1z" fill-rule="evenodd"/>
<path d="M256.5 147.6h.1v2h-.1z" fill-rule="evenodd"/>
<path d="M226.8 155.3h.1v2h-.1z" fill-rule="evenodd"/>
<path d="M226.8 149.8h.1v2h-.1z" fill-rule="evenodd"/>
<path d="M226.8 144.3h.1v2h-.1z" fill-rule="evenodd"/>
</g>
<path d="M206.2 46.6v62.5h-94.8" fill="none" stroke="#00f" stroke-width=".55"/>
<path d="M142.2 128.9h5.4v16.3h-5.4z" fill-rule="evenodd" fill="#ffffb0" stroke="#800000" stroke-width=".13"/>
<g fill="none" stroke="#000" stroke-width=".13">
<path d="M140 130h1.6M140 131.1h1.6M140 132.2h1.6M140 133.3h1.6M140 134.4h1.6M140 135.4h1.6M140 136.5h1.6M140 137.6h1.6M140 138.7h1.6M140 139.8h1.6M148.4 130h1.6M148.4 131.1h1.6"/>
<path d="M148.4 132.2h1.6M148.4 133.3h1.6M148.4 134.4h1.6M148.4 135.4h1.6M148.4 136.5h1.6M148.4 137.6h1.6M148.4 138.7h1.6M148.4 139.8h1.6M140 140.9h1.6M140 142h1.6M140 143.1h1.6M140 144.2h1.6"/>
<path d="M148.4 140.9h1.6M148.4 142h1.6M148.4 143.1h1.6M148.4 144.2h1.6"/>
<circle cx="141.9" cy="139.8" r=".27"/>
<circle cx="141.9" cy="131" r=".27"/>
<circle cx="141.9" cy="129.9" r=".27"/>
<circle cx="141.9" cy="137.6" r=".27"/>
<circle cx="141.9" cy="132.1" r=".27"/>
<circle cx="141.9" cy="133.2" r=".27"/>
<circle cx="141.9" cy="136.5" r=".27"/>
<circle cx="141.9" cy="135.4" r=".27"/>
<circle cx="141.9" cy="138.7" r=".27"/>
<circle cx="141.9" cy="134.3" r=".27"/>
<circle cx="148" cy="134.3" r=".27"/>
<circle cx="148" cy="136.5" r=".27"/>
<circle cx="148" cy="137.6" r=".27"/>
<circle cx="148" cy="132.1" r=".27"/>
<circle cx="148" cy="138.7" r=".27"/>
<circle cx="148" cy="129.9" r=".27"/>
<circle cx="148" cy="131" r=".27"/>
<circle cx="148" cy="133.2" r=".27"/>
<circle cx="148" cy="139.8" r=".27"/>
<circle cx="148" cy="135.4" r=".27"/>
<circle cx="141.9" cy="142" r=".27"/>
<circle cx="141.9" cy="144.2" r=".27"/>
<circle cx="141.9" cy="143.1" r=".27"/>
<circle cx="141.9" cy="140.9" r=".27"/>
<circle cx="148" cy="144.2" r=".27"/>
<circle cx="148" cy="142" r=".27"/>
<circle cx="148" cy="143.1" r=".27"/>
<circle cx="148" cy="140.9" r=".27"/>
</g>
<path d="M163.2 128.9h5.4v16.3h-5.4z" fill-rule="evenodd" fill="#ffffb0" stroke="#800000" stroke-width=".13"/>
<g fill="none" stroke="#000" stroke-width=".13">
<path d="M234.8 64.1h1.1M237 64.1h1.1M161 130h1.5M161 131.1h1.5M161 132.2h1.5M161 133.3h1.5M161 134.4h1.5M161 135.4h1.5M161 136.5h1.5M161 137.6h1.5M161 138.7h1.5M161 139.8h1.5"/>
<path d="M169.4 130h1.5M169.4 131.1h1.5M169.4 132.2h1.5M169.4 133.3h1.5M169.4 134.4h1.5M169.4 135.4h1.5M169.4 136.5h1.5M169.4 137.6h1.5M169.4 138.7h1.5M169.4 139.8h1.5M161 140.9h1.5M161 142h1.5"/>
<path d="M161 143.1h1.5M161 144.2h1.5M169.4 140.9h1.5M169.4 142h1.5M169.4 143.1h1.5M169.4 144.2h1.5"/>
<circle cx="162.8" cy="131" r=".27"/>
<circle cx="162.8" cy="133.2" r=".27"/>
<circle cx="162.8" cy="134.3" r=".27"/>
<circle cx="162.8" cy="136.5" r=".27"/>
<circle cx="162.8" cy="137.6" r=".27"/>
<circle cx="162.8" cy="129.9" r=".27"/>
<circle cx="162.8" cy="139.8" r=".27"/>
<circle cx="162.8" cy="138.7" r=".27"/>
<circle cx="162.8" cy="132.1" r=".27"/>
<circle cx="162.8" cy="135.4" r=".27"/>
<circle cx="169" cy="129.9" r=".27"/>
<circle cx="169" cy="137.6" r=".27"/>
<circle cx="169" cy="134.3" r=".27"/>
<circle cx="169" cy="135.4" r=".27"/>
<circle cx="169" cy="138.7" r=".27"/>
<circle cx="169" cy="136.5" r=".27"/>
<circle cx="169" cy="132.1" r=".27"/>
<circle cx="169" cy="131" r=".27"/>
<circle cx="169" cy="133.2" r=".27"/>
<circle cx="169" cy="139.8" r=".27"/>
<circle cx="162.8" cy="140.9" r=".27"/>
<circle cx="162.8" cy="143.1" r=".27"/>
<circle cx="162.8" cy="142" r=".27"/>
<circle cx="162.8" cy="144.2" r=".27"/>
<circle cx="169" cy="142" r=".27"/>
<circle cx="169" cy="140.9" r=".27"/>
<circle cx="169" cy="144.2" r=".27"/>
<circle cx="169" cy="143.1" r=".27"/>
</g>
<path d="M235.9 64.1h.3M236.2 63.1v2M236.7 64.1h.3M236.7 63.1v2" fill="none" stroke="#00f" stroke-width=".13"/>
<path d="M246.9 59.7h3.3M72.8 67.4h1.1M72.8 75.1h1.1M240.3 64.1h1.1M51.9 86.1h2.2M51.9 85h2.2M51.9 83.9h2.2M44.2 120.1h11v7.7M50.8 131.1h1.1v1.1M77.2 120.1h9.9v7.7" fill="none" stroke="#000080" stroke-width=".13"/>
<path d="M111.4 46.6v62.5h-83.8" fill="none" stroke="#00f" stroke-width=".55"/>
<path d="M60.7 76.2h2.2M61 76.5h1.6M61.4 76.9h.8M61.7 77.2h.2M61.8 75.1v1.1" fill="none" stroke="#781915" stroke-width=".13"/>
<path d="M73.9 67.4h1.1M75 66.9v1.1M51.3 82.8h1.1M51.3 87.2h1.1M51.9 82.8v1.1M51.9 86.1v1.1" fill="none" stroke="#800000" stroke-width=".13"/>
<path d="M56.3 82.8h5.4v4.3h-5.4z" fill-rule="evenodd" fill="#ffffb0" stroke="#800000" stroke-width=".13"/>
<g fill="none" stroke="#000" stroke-width=".13">
<path d="M140 54.2h2.2M145.5 54.2h2.3M148.9 55.3h1.1M151.1 55.3h1.1M54.1 86.1h1.5M54.1 85h1.5M54.1 83.9h1.5M62.5 86.1h1.5M62.5 85h1.5M62.5 83.9h1.5M238.1 97h1.1M242.5 97h1.1"/>
<path d="M238.1 117.9h2.2M243.6 117.9h2.2M50.8 137.2v1.5M51.9 132.2v1.5M53 137.2v1.5"/>
<circle cx="55.9" cy="83.8" r=".27"/>
<circle cx="55.9" cy="84.9" r=".27"/>
<circle cx="55.9" cy="86" r=".27"/>
<circle cx="62.1" cy="83.8" r=".27"/>
<circle cx="62.1" cy="86" r=".27"/>
<circle cx="62.1" cy="84.9" r=".27"/>
<circle cx="50.7" cy="136.8" r=".27"/>
<circle cx="51.8" cy="134" r=".27"/>
<circle cx="52.9" cy="136.8" r=".27"/>
</g>
<g fill="none" stroke="#000080" stroke-width=".13">
<path d="M148.9 55.3v2.2M125.7 78.4h2.2M64 85h2.2M64 86.1h2.2M64 83.9h2.2M166.5 85h3.3M235.9 97h2.2M243.6 97h4.4M237 115.7v2.2h1.1M245.8 115.7v2.2M83.8 131.1v8.7M91.5 138.7v8.8h-7.7"/>
<path d="M53 146.4h5.5"/>
</g>
<path d="M71.7 85h12.1v2.2h-12.1zM71.7 86.1h12.1M75 85v2.2M79.4 85v2.2" fill="none" stroke="#0000b4" stroke-width=".13"/>
<g fill="none" stroke="#800000" stroke-width=".13">
<path d="M137.9 54.1v.3M138.3 53.8v.9M138.6 53.5v1.5M138.9 54.2h1.1M138.9 53.1v2.2M148.3 54.2h1.1M148.9 54.2v1.1M152.2 55.3h1.1M153.3 54.2v2.2M153.6 54.6v1.5M153.9 54.9v.9M154.3 55.2v.3"/>
<path d="M50.8 84.4v1.1M50.8 85h1.1M65.7 82.8h1.1M66.2 82.8v1.1M234.8 98.1h2.2M235.1 98.5h1.6M235.5 98.8h.9M235.8 99.1h.2M235.9 97v1.1M153.3 142h1.1M154.4 141.5v1.1"/>
</g>
<g fill="none" stroke="#00f" stroke-width=".13">
<path d="M142.2 53.9h3.3v.7h-3.3zM150 55.3h.3M150.3 54.4v1.9M150.7 55.3h.4M150.7 54.4v1.9M239.2 96.3h3.3v.1h-3.3zM239.2 96.9l.2-.2h.3l.2 .2v.3l-.2 .2h-.3l-.2-.2zM240.4 96.4v-.5h.9v.5M240.4 96.2h.9M240.4 96.1h.9M240.5 95.9v.5M240.7 95.9v.5"/>
<path d="M240.8 95.9v.5M240.9 95.9v.5M241 95.9v.5M241.1 95.9v.5M241.2 95.9v.5M242.1 96.7h.2l.2 .2v.3l-.2 .2h-.2l-.2-.2v-.3zM240.3 117.6h3.3v.6h-3.3zM51.9 134.4l1.1 2.1"/>
</g>
<path d="M271.2 46.6v62.5h-65v53.8M206.2 78.4h65M111.4 109.1v31.8M271.2 109.1v26.3h-65" fill="none" stroke="#00f" stroke-width=".55"/>
<path d="M131.2 64.1h31.9v31.7h-31.9z" fill-rule="evenodd" fill="#ffffb0" stroke="#800000" stroke-width=".13"/>
<g fill="none" stroke="#000" stroke-width=".13">
<path d="M120.2 75.1h1.1M122.4 75.1h1.1M127.9 74h3.3M127.9 75.1h3.3M127.9 76.2h3.3M127.9 77.3h3.3M127.9 79.5h3.3M127.9 78.4h3.3M141.1 60.8v3.3M142.2 60.8v3.3M143.3 60.8v3.3M144.4 60.8v3.3"/>
<path d="M145.5 60.8v3.3M146.7 60.8v3.3M147.8 60.8v3.3M148.9 60.8v3.3M150 60.8v3.3M151.1 60.8v3.3M152.2 60.8v3.3M153.3 60.8v3.3M163.2 74h3.3M163.2 75.1h3.3M163.2 76.2h3.3M163.2 77.3h3.3"/>
<path d="M163.2 79.5h3.3M163.2 78.4h3.3M127.9 80.6h3.3M127.9 81.7h3.3M127.9 82.8h3.3M127.9 83.9h3.3M127.9 85h3.3M127.9 86.1h3.3M141.1 95.9v3.3M142.2 95.9v3.3M143.3 95.9v3.3M144.4 95.9v3.3"/>
<path d="M145.5 95.9v3.3M146.7 95.9v3.3M147.8 95.9v3.3M148.9 95.9v3.3M150 95.9v3.3M151.1 95.9v3.3M152.2 95.9v3.3M153.3 95.9v3.3M163.2 80.6h3.3M163.2 81.7h3.3M163.2 82.8h3.3M163.2 83.9h3.3"/>
<path d="M163.2 85h3.3M163.2 86.1h3.3M47.5 153h2.2M53 153h2.2M66.2 153h2.2M71.7 153h2.2M83.8 153h2.2M89.3 153h2.2"/>
</g>
<g fill="none" stroke="#f00" stroke-width=".13">
<path d="M127.5 73.6l.9 .8M127.5 76.9l.9 .8M128.4 73.6l-.9 .8M128.4 76.9l-.9 .8"/>
<circle cx="127.9" cy="73.9" r=".38"/>
<circle cx="127.9" cy="77.2" r=".38"/>
</g>
<path d="M271.2 46.6h-243.6v115.2h243.6v-26.4M111.4 140.9v20.9" fill="none" stroke="#00f" stroke-width=".55"/>
<g fill="#800000" stroke="#800000" stroke-width=".13">
<circle cx="60.6" cy="138.7" r=".16"/>
<circle cx="58.4" cy="127.7" r=".16"/>
<circle cx="58.4" cy="138.7" r=".16"/>
<circle cx="93.7" cy="138.7" r=".16"/>
<circle cx="91.5" cy="127.7" r=".16"/>
<circle cx="91.5" cy="138.7" r=".16"/>
<circle cx="234.8" cy="64.1" r=".16"/>
<circle cx="245.8" cy="120" r=".16"/>
<circle cx="237" cy="120" r=".16"/>
<circle cx="237" cy="117.8" r=".16"/>
<circle cx="245.8" cy="117.8" r=".16"/>
<circle cx="147.7" cy="54.2" r=".16"/>
<circle cx="51.8" cy="67.4" r=".16"/>
<circle cx="61.7" cy="75" r=".16"/>
<circle cx="69.5" cy="67.4" r=".16"/>
<circle cx="69.5" cy="75" r=".16"/>
<circle cx="148.8" cy="55.3" r=".16"/>
<circle cx="241.4" cy="59.7" r=".16"/>
</g>
<path d="M121.3 75.1h.3M121.6 74.1v2M122.1 75.1h.3M122.1 74.1v2M49.7 152.7h3.3v.6h-3.3zM68.4 152.7h3.3v.6h-3.3zM86 152.7h3.3v.6h-3.3z" fill="none" stroke="#00f" stroke-width=".13"/>
<path d="M123.5 75.1h2.2M150 139.8h3.3M46.4 153h1.1M55.2 153h1.1M65.1 153h1.1M73.9 153h1.1M82.7 153h1.1M91.5 153h1.2M150 140.9h2.2v1.1h1.1" fill="none" stroke="#000080" stroke-width=".13"/>
<g fill="none" stroke="#800000" stroke-width=".13">
<path d="M118.1 75v.2M118.4 74.7v.8M118.8 74.3v1.6M119.1 74v2.2M119.1 75.1h1.1M153.3 139.8h1.1M154.4 139.3v1.1M56.3 153h1.1M57.4 152.5v1.1M92.7 153h1.1M93.8 151.9v2.2M94.1 152.2v1.6"/>
<path d="M94.4 152.6v.8M94.7 152.9v.2"/>
</g>
<use href="#words"/>
</svg>
